VERSION 5.8 ;
BUSBITCHARS "[]" ;
DIVIDERCHAR "/" ;
UNITS
    DATABASE MICRONS 1000 ;
END UNITS

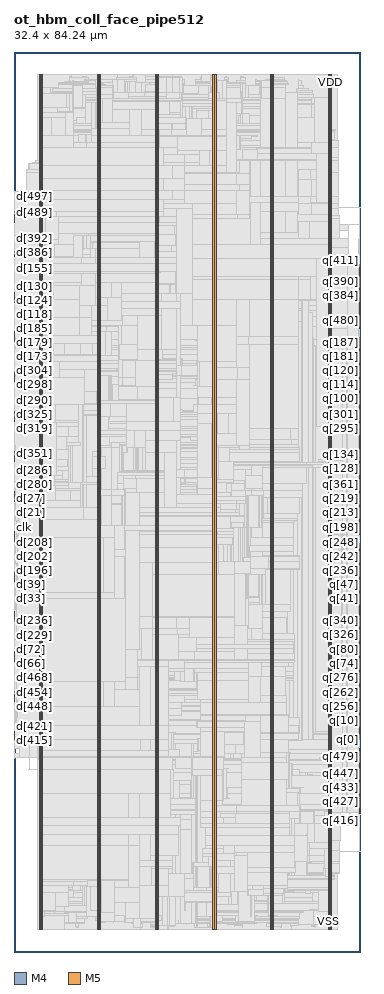
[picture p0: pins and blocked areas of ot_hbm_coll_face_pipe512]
MACRO ot_hbm_coll_face_pipe512
  FOREIGN ot_hbm_coll_face_pipe512 0 0 ;
  CLASS BLOCK ;
  SIZE 32.4 BY 84.24 ;
  PIN clk
    DIRECTION INPUT ;
    USE SIGNAL ;
    PORT
      LAYER M4 ;
        RECT  0 39.024 0.084 39.048 ;
    END
  END clk
  PIN d[0]
    DIRECTION INPUT ;
    USE SIGNAL ;
    PORT
      LAYER M4 ;
        RECT  0 39.12 0.084 39.144 ;
    END
  END d[0]
  PIN d[100]
    DIRECTION INPUT ;
    USE SIGNAL ;
    PORT
      LAYER M4 ;
        RECT  0 58.704 0.084 58.728 ;
    END
  END d[100]
  PIN d[101]
    DIRECTION INPUT ;
    USE SIGNAL ;
    PORT
      LAYER M4 ;
        RECT  0 58.8 0.084 58.824 ;
    END
  END d[101]
  PIN d[102]
    DIRECTION INPUT ;
    USE SIGNAL ;
    PORT
      LAYER M4 ;
        RECT  0 58.896 0.084 58.92 ;
    END
  END d[102]
  PIN d[103]
    DIRECTION INPUT ;
    USE SIGNAL ;
    PORT
      LAYER M4 ;
        RECT  0 58.992 0.084 59.016 ;
    END
  END d[103]
  PIN d[104]
    DIRECTION INPUT ;
    USE SIGNAL ;
    PORT
      LAYER M4 ;
        RECT  0 59.088 0.084 59.112 ;
    END
  END d[104]
  PIN d[105]
    DIRECTION INPUT ;
    USE SIGNAL ;
    PORT
      LAYER M4 ;
        RECT  0 59.184 0.084 59.208 ;
    END
  END d[105]
  PIN d[106]
    DIRECTION INPUT ;
    USE SIGNAL ;
    PORT
      LAYER M4 ;
        RECT  0 59.28 0.084 59.304 ;
    END
  END d[106]
  PIN d[107]
    DIRECTION INPUT ;
    USE SIGNAL ;
    PORT
      LAYER M4 ;
        RECT  0 59.376 0.084 59.4 ;
    END
  END d[107]
  PIN d[108]
    DIRECTION INPUT ;
    USE SIGNAL ;
    PORT
      LAYER M4 ;
        RECT  0 59.472 0.084 59.496 ;
    END
  END d[108]
  PIN d[109]
    DIRECTION INPUT ;
    USE SIGNAL ;
    PORT
      LAYER M4 ;
        RECT  0 59.568 0.084 59.592 ;
    END
  END d[109]
  PIN d[10]
    DIRECTION INPUT ;
    USE SIGNAL ;
    PORT
      LAYER M4 ;
        RECT  0 40.08 0.084 40.104 ;
    END
  END d[10]
  PIN d[110]
    DIRECTION INPUT ;
    USE SIGNAL ;
    PORT
      LAYER M4 ;
        RECT  0 59.664 0.084 59.688 ;
    END
  END d[110]
  PIN d[111]
    DIRECTION INPUT ;
    USE SIGNAL ;
    PORT
      LAYER M4 ;
        RECT  0 59.76 0.084 59.784 ;
    END
  END d[111]
  PIN d[112]
    DIRECTION INPUT ;
    USE SIGNAL ;
    PORT
      LAYER M4 ;
        RECT  0 59.856 0.084 59.88 ;
    END
  END d[112]
  PIN d[113]
    DIRECTION INPUT ;
    USE SIGNAL ;
    PORT
      LAYER M4 ;
        RECT  0 59.952 0.084 59.976 ;
    END
  END d[113]
  PIN d[114]
    DIRECTION INPUT ;
    USE SIGNAL ;
    PORT
      LAYER M4 ;
        RECT  0 60.048 0.084 60.072 ;
    END
  END d[114]
  PIN d[115]
    DIRECTION INPUT ;
    USE SIGNAL ;
    PORT
      LAYER M4 ;
        RECT  0 60.144 0.084 60.168 ;
    END
  END d[115]
  PIN d[116]
    DIRECTION INPUT ;
    USE SIGNAL ;
    PORT
      LAYER M4 ;
        RECT  0 60.24 0.084 60.264 ;
    END
  END d[116]
  PIN d[117]
    DIRECTION INPUT ;
    USE SIGNAL ;
    PORT
      LAYER M4 ;
        RECT  0 60.336 0.084 60.36 ;
    END
  END d[117]
  PIN d[118]
    DIRECTION INPUT ;
    USE SIGNAL ;
    PORT
      LAYER M4 ;
        RECT  0 60.432 0.084 60.456 ;
    END
  END d[118]
  PIN d[119]
    DIRECTION INPUT ;
    USE SIGNAL ;
    PORT
      LAYER M4 ;
        RECT  0 60.528 0.084 60.552 ;
    END
  END d[119]
  PIN d[11]
    DIRECTION INPUT ;
    USE SIGNAL ;
    PORT
      LAYER M4 ;
        RECT  0 40.176 0.084 40.2 ;
    END
  END d[11]
  PIN d[120]
    DIRECTION INPUT ;
    USE SIGNAL ;
    PORT
      LAYER M4 ;
        RECT  0 60.624 0.084 60.648 ;
    END
  END d[120]
  PIN d[121]
    DIRECTION INPUT ;
    USE SIGNAL ;
    PORT
      LAYER M4 ;
        RECT  0 60.72 0.084 60.744 ;
    END
  END d[121]
  PIN d[122]
    DIRECTION INPUT ;
    USE SIGNAL ;
    PORT
      LAYER M4 ;
        RECT  0 60.816 0.084 60.84 ;
    END
  END d[122]
  PIN d[123]
    DIRECTION INPUT ;
    USE SIGNAL ;
    PORT
      LAYER M4 ;
        RECT  0 60.912 0.084 60.936 ;
    END
  END d[123]
  PIN d[124]
    DIRECTION INPUT ;
    USE SIGNAL ;
    PORT
      LAYER M4 ;
        RECT  0 61.008 0.084 61.032 ;
    END
  END d[124]
  PIN d[125]
    DIRECTION INPUT ;
    USE SIGNAL ;
    PORT
      LAYER M4 ;
        RECT  0 61.104 0.084 61.128 ;
    END
  END d[125]
  PIN d[126]
    DIRECTION INPUT ;
    USE SIGNAL ;
    PORT
      LAYER M4 ;
        RECT  0 61.2 0.084 61.224 ;
    END
  END d[126]
  PIN d[127]
    DIRECTION INPUT ;
    USE SIGNAL ;
    PORT
      LAYER M4 ;
        RECT  0 61.296 0.084 61.32 ;
    END
  END d[127]
  PIN d[128]
    DIRECTION INPUT ;
    USE SIGNAL ;
    PORT
      LAYER M4 ;
        RECT  0 61.392 0.084 61.416 ;
    END
  END d[128]
  PIN d[129]
    DIRECTION INPUT ;
    USE SIGNAL ;
    PORT
      LAYER M4 ;
        RECT  0 61.488 0.084 61.512 ;
    END
  END d[129]
  PIN d[12]
    DIRECTION INPUT ;
    USE SIGNAL ;
    PORT
      LAYER M4 ;
        RECT  0 40.272 0.084 40.296 ;
    END
  END d[12]
  PIN d[130]
    DIRECTION INPUT ;
    USE SIGNAL ;
    PORT
      LAYER M4 ;
        RECT  0 61.584 0.084 61.608 ;
    END
  END d[130]
  PIN d[131]
    DIRECTION INPUT ;
    USE SIGNAL ;
    PORT
      LAYER M4 ;
        RECT  0 61.68 0.084 61.704 ;
    END
  END d[131]
  PIN d[132]
    DIRECTION INPUT ;
    USE SIGNAL ;
    PORT
      LAYER M4 ;
        RECT  0 61.776 0.084 61.8 ;
    END
  END d[132]
  PIN d[133]
    DIRECTION INPUT ;
    USE SIGNAL ;
    PORT
      LAYER M4 ;
        RECT  0 61.872 0.084 61.896 ;
    END
  END d[133]
  PIN d[134]
    DIRECTION INPUT ;
    USE SIGNAL ;
    PORT
      LAYER M4 ;
        RECT  0 61.968 0.084 61.992 ;
    END
  END d[134]
  PIN d[135]
    DIRECTION INPUT ;
    USE SIGNAL ;
    PORT
      LAYER M4 ;
        RECT  0 62.064 0.084 62.088 ;
    END
  END d[135]
  PIN d[136]
    DIRECTION INPUT ;
    USE SIGNAL ;
    PORT
      LAYER M4 ;
        RECT  0 62.16 0.084 62.184 ;
    END
  END d[136]
  PIN d[137]
    DIRECTION INPUT ;
    USE SIGNAL ;
    PORT
      LAYER M4 ;
        RECT  0 62.256 0.084 62.28 ;
    END
  END d[137]
  PIN d[138]
    DIRECTION INPUT ;
    USE SIGNAL ;
    PORT
      LAYER M4 ;
        RECT  0 62.352 0.084 62.376 ;
    END
  END d[138]
  PIN d[139]
    DIRECTION INPUT ;
    USE SIGNAL ;
    PORT
      LAYER M4 ;
        RECT  0 62.448 0.084 62.472 ;
    END
  END d[139]
  PIN d[13]
    DIRECTION INPUT ;
    USE SIGNAL ;
    PORT
      LAYER M4 ;
        RECT  0 40.368 0.084 40.392 ;
    END
  END d[13]
  PIN d[140]
    DIRECTION INPUT ;
    USE SIGNAL ;
    PORT
      LAYER M4 ;
        RECT  0 62.544 0.084 62.568 ;
    END
  END d[140]
  PIN d[141]
    DIRECTION INPUT ;
    USE SIGNAL ;
    PORT
      LAYER M4 ;
        RECT  0 62.64 0.084 62.664 ;
    END
  END d[141]
  PIN d[142]
    DIRECTION INPUT ;
    USE SIGNAL ;
    PORT
      LAYER M4 ;
        RECT  0 62.736 0.084 62.76 ;
    END
  END d[142]
  PIN d[143]
    DIRECTION INPUT ;
    USE SIGNAL ;
    PORT
      LAYER M4 ;
        RECT  0 62.832 0.084 62.856 ;
    END
  END d[143]
  PIN d[144]
    DIRECTION INPUT ;
    USE SIGNAL ;
    PORT
      LAYER M4 ;
        RECT  0 62.928 0.084 62.952 ;
    END
  END d[144]
  PIN d[145]
    DIRECTION INPUT ;
    USE SIGNAL ;
    PORT
      LAYER M4 ;
        RECT  0 63.024 0.084 63.048 ;
    END
  END d[145]
  PIN d[146]
    DIRECTION INPUT ;
    USE SIGNAL ;
    PORT
      LAYER M4 ;
        RECT  0 63.12 0.084 63.144 ;
    END
  END d[146]
  PIN d[147]
    DIRECTION INPUT ;
    USE SIGNAL ;
    PORT
      LAYER M4 ;
        RECT  0 63.216 0.084 63.24 ;
    END
  END d[147]
  PIN d[148]
    DIRECTION INPUT ;
    USE SIGNAL ;
    PORT
      LAYER M4 ;
        RECT  0 63.312 0.084 63.336 ;
    END
  END d[148]
  PIN d[149]
    DIRECTION INPUT ;
    USE SIGNAL ;
    PORT
      LAYER M4 ;
        RECT  0 63.408 0.084 63.432 ;
    END
  END d[149]
  PIN d[14]
    DIRECTION INPUT ;
    USE SIGNAL ;
    PORT
      LAYER M4 ;
        RECT  0 40.464 0.084 40.488 ;
    END
  END d[14]
  PIN d[150]
    DIRECTION INPUT ;
    USE SIGNAL ;
    PORT
      LAYER M4 ;
        RECT  0 63.504 0.084 63.528 ;
    END
  END d[150]
  PIN d[151]
    DIRECTION INPUT ;
    USE SIGNAL ;
    PORT
      LAYER M4 ;
        RECT  0 63.6 0.084 63.624 ;
    END
  END d[151]
  PIN d[152]
    DIRECTION INPUT ;
    USE SIGNAL ;
    PORT
      LAYER M4 ;
        RECT  0 63.696 0.084 63.72 ;
    END
  END d[152]
  PIN d[153]
    DIRECTION INPUT ;
    USE SIGNAL ;
    PORT
      LAYER M4 ;
        RECT  0 63.792 0.084 63.816 ;
    END
  END d[153]
  PIN d[154]
    DIRECTION INPUT ;
    USE SIGNAL ;
    PORT
      LAYER M4 ;
        RECT  0 63.888 0.084 63.912 ;
    END
  END d[154]
  PIN d[155]
    DIRECTION INPUT ;
    USE SIGNAL ;
    PORT
      LAYER M4 ;
        RECT  0 63.984 0.084 64.008 ;
    END
  END d[155]
  PIN d[156]
    DIRECTION INPUT ;
    USE SIGNAL ;
    PORT
      LAYER M4 ;
        RECT  0 64.08 0.084 64.104 ;
    END
  END d[156]
  PIN d[157]
    DIRECTION INPUT ;
    USE SIGNAL ;
    PORT
      LAYER M4 ;
        RECT  0 64.176 0.084 64.2 ;
    END
  END d[157]
  PIN d[158]
    DIRECTION INPUT ;
    USE SIGNAL ;
    PORT
      LAYER M4 ;
        RECT  0 64.272 0.084 64.296 ;
    END
  END d[158]
  PIN d[159]
    DIRECTION INPUT ;
    USE SIGNAL ;
    PORT
      LAYER M4 ;
        RECT  0 55.152 0.084 55.176 ;
    END
  END d[159]
  PIN d[15]
    DIRECTION INPUT ;
    USE SIGNAL ;
    PORT
      LAYER M4 ;
        RECT  0 40.56 0.084 40.584 ;
    END
  END d[15]
  PIN d[160]
    DIRECTION INPUT ;
    USE SIGNAL ;
    PORT
      LAYER M4 ;
        RECT  0 55.248 0.084 55.272 ;
    END
  END d[160]
  PIN d[161]
    DIRECTION INPUT ;
    USE SIGNAL ;
    PORT
      LAYER M4 ;
        RECT  0 55.344 0.084 55.368 ;
    END
  END d[161]
  PIN d[162]
    DIRECTION INPUT ;
    USE SIGNAL ;
    PORT
      LAYER M4 ;
        RECT  0 55.44 0.084 55.464 ;
    END
  END d[162]
  PIN d[163]
    DIRECTION INPUT ;
    USE SIGNAL ;
    PORT
      LAYER M4 ;
        RECT  0 55.536 0.084 55.56 ;
    END
  END d[163]
  PIN d[164]
    DIRECTION INPUT ;
    USE SIGNAL ;
    PORT
      LAYER M4 ;
        RECT  0 55.632 0.084 55.656 ;
    END
  END d[164]
  PIN d[165]
    DIRECTION INPUT ;
    USE SIGNAL ;
    PORT
      LAYER M4 ;
        RECT  0 55.728 0.084 55.752 ;
    END
  END d[165]
  PIN d[166]
    DIRECTION INPUT ;
    USE SIGNAL ;
    PORT
      LAYER M4 ;
        RECT  0 55.824 0.084 55.848 ;
    END
  END d[166]
  PIN d[167]
    DIRECTION INPUT ;
    USE SIGNAL ;
    PORT
      LAYER M4 ;
        RECT  0 55.92 0.084 55.944 ;
    END
  END d[167]
  PIN d[168]
    DIRECTION INPUT ;
    USE SIGNAL ;
    PORT
      LAYER M4 ;
        RECT  0 56.016 0.084 56.04 ;
    END
  END d[168]
  PIN d[169]
    DIRECTION INPUT ;
    USE SIGNAL ;
    PORT
      LAYER M4 ;
        RECT  0 56.112 0.084 56.136 ;
    END
  END d[169]
  PIN d[16]
    DIRECTION INPUT ;
    USE SIGNAL ;
    PORT
      LAYER M4 ;
        RECT  0 40.656 0.084 40.68 ;
    END
  END d[16]
  PIN d[170]
    DIRECTION INPUT ;
    USE SIGNAL ;
    PORT
      LAYER M4 ;
        RECT  0 56.208 0.084 56.232 ;
    END
  END d[170]
  PIN d[171]
    DIRECTION INPUT ;
    USE SIGNAL ;
    PORT
      LAYER M4 ;
        RECT  0 56.304 0.084 56.328 ;
    END
  END d[171]
  PIN d[172]
    DIRECTION INPUT ;
    USE SIGNAL ;
    PORT
      LAYER M4 ;
        RECT  0 56.4 0.084 56.424 ;
    END
  END d[172]
  PIN d[173]
    DIRECTION INPUT ;
    USE SIGNAL ;
    PORT
      LAYER M4 ;
        RECT  0 56.496 0.084 56.52 ;
    END
  END d[173]
  PIN d[174]
    DIRECTION INPUT ;
    USE SIGNAL ;
    PORT
      LAYER M4 ;
        RECT  0 56.592 0.084 56.616 ;
    END
  END d[174]
  PIN d[175]
    DIRECTION INPUT ;
    USE SIGNAL ;
    PORT
      LAYER M4 ;
        RECT  0 56.688 0.084 56.712 ;
    END
  END d[175]
  PIN d[176]
    DIRECTION INPUT ;
    USE SIGNAL ;
    PORT
      LAYER M4 ;
        RECT  0 56.784 0.084 56.808 ;
    END
  END d[176]
  PIN d[177]
    DIRECTION INPUT ;
    USE SIGNAL ;
    PORT
      LAYER M4 ;
        RECT  0 56.88 0.084 56.904 ;
    END
  END d[177]
  PIN d[178]
    DIRECTION INPUT ;
    USE SIGNAL ;
    PORT
      LAYER M4 ;
        RECT  0 56.976 0.084 57 ;
    END
  END d[178]
  PIN d[179]
    DIRECTION INPUT ;
    USE SIGNAL ;
    PORT
      LAYER M4 ;
        RECT  0 57.072 0.084 57.096 ;
    END
  END d[179]
  PIN d[17]
    DIRECTION INPUT ;
    USE SIGNAL ;
    PORT
      LAYER M4 ;
        RECT  0 40.752 0.084 40.776 ;
    END
  END d[17]
  PIN d[180]
    DIRECTION INPUT ;
    USE SIGNAL ;
    PORT
      LAYER M4 ;
        RECT  0 57.168 0.084 57.192 ;
    END
  END d[180]
  PIN d[181]
    DIRECTION INPUT ;
    USE SIGNAL ;
    PORT
      LAYER M4 ;
        RECT  0 57.264 0.084 57.288 ;
    END
  END d[181]
  PIN d[182]
    DIRECTION INPUT ;
    USE SIGNAL ;
    PORT
      LAYER M4 ;
        RECT  0 57.36 0.084 57.384 ;
    END
  END d[182]
  PIN d[183]
    DIRECTION INPUT ;
    USE SIGNAL ;
    PORT
      LAYER M4 ;
        RECT  0 57.456 0.084 57.48 ;
    END
  END d[183]
  PIN d[184]
    DIRECTION INPUT ;
    USE SIGNAL ;
    PORT
      LAYER M4 ;
        RECT  0 57.552 0.084 57.576 ;
    END
  END d[184]
  PIN d[185]
    DIRECTION INPUT ;
    USE SIGNAL ;
    PORT
      LAYER M4 ;
        RECT  0 57.648 0.084 57.672 ;
    END
  END d[185]
  PIN d[186]
    DIRECTION INPUT ;
    USE SIGNAL ;
    PORT
      LAYER M4 ;
        RECT  0 57.744 0.084 57.768 ;
    END
  END d[186]
  PIN d[187]
    DIRECTION INPUT ;
    USE SIGNAL ;
    PORT
      LAYER M4 ;
        RECT  0 57.84 0.084 57.864 ;
    END
  END d[187]
  PIN d[188]
    DIRECTION INPUT ;
    USE SIGNAL ;
    PORT
      LAYER M4 ;
        RECT  0 57.936 0.084 57.96 ;
    END
  END d[188]
  PIN d[189]
    DIRECTION INPUT ;
    USE SIGNAL ;
    PORT
      LAYER M4 ;
        RECT  0 58.032 0.084 58.056 ;
    END
  END d[189]
  PIN d[18]
    DIRECTION INPUT ;
    USE SIGNAL ;
    PORT
      LAYER M4 ;
        RECT  0 40.848 0.084 40.872 ;
    END
  END d[18]
  PIN d[190]
    DIRECTION INPUT ;
    USE SIGNAL ;
    PORT
      LAYER M4 ;
        RECT  0 58.128 0.084 58.152 ;
    END
  END d[190]
  PIN d[191]
    DIRECTION INPUT ;
    USE SIGNAL ;
    PORT
      LAYER M4 ;
        RECT  0 35.952 0.084 35.976 ;
    END
  END d[191]
  PIN d[192]
    DIRECTION INPUT ;
    USE SIGNAL ;
    PORT
      LAYER M4 ;
        RECT  0 36.048 0.084 36.072 ;
    END
  END d[192]
  PIN d[193]
    DIRECTION INPUT ;
    USE SIGNAL ;
    PORT
      LAYER M4 ;
        RECT  0 36.144 0.084 36.168 ;
    END
  END d[193]
  PIN d[194]
    DIRECTION INPUT ;
    USE SIGNAL ;
    PORT
      LAYER M4 ;
        RECT  0 36.24 0.084 36.264 ;
    END
  END d[194]
  PIN d[195]
    DIRECTION INPUT ;
    USE SIGNAL ;
    PORT
      LAYER M4 ;
        RECT  0 36.336 0.084 36.36 ;
    END
  END d[195]
  PIN d[196]
    DIRECTION INPUT ;
    USE SIGNAL ;
    PORT
      LAYER M4 ;
        RECT  0 36.432 0.084 36.456 ;
    END
  END d[196]
  PIN d[197]
    DIRECTION INPUT ;
    USE SIGNAL ;
    PORT
      LAYER M4 ;
        RECT  0 36.528 0.084 36.552 ;
    END
  END d[197]
  PIN d[198]
    DIRECTION INPUT ;
    USE SIGNAL ;
    PORT
      LAYER M4 ;
        RECT  0 36.624 0.084 36.648 ;
    END
  END d[198]
  PIN d[199]
    DIRECTION INPUT ;
    USE SIGNAL ;
    PORT
      LAYER M4 ;
        RECT  0 36.72 0.084 36.744 ;
    END
  END d[199]
  PIN d[19]
    DIRECTION INPUT ;
    USE SIGNAL ;
    PORT
      LAYER M4 ;
        RECT  0 40.944 0.084 40.968 ;
    END
  END d[19]
  PIN d[1]
    DIRECTION INPUT ;
    USE SIGNAL ;
    PORT
      LAYER M4 ;
        RECT  0 39.216 0.084 39.24 ;
    END
  END d[1]
  PIN d[200]
    DIRECTION INPUT ;
    USE SIGNAL ;
    PORT
      LAYER M4 ;
        RECT  0 36.816 0.084 36.84 ;
    END
  END d[200]
  PIN d[201]
    DIRECTION INPUT ;
    USE SIGNAL ;
    PORT
      LAYER M4 ;
        RECT  0 36.912 0.084 36.936 ;
    END
  END d[201]
  PIN d[202]
    DIRECTION INPUT ;
    USE SIGNAL ;
    PORT
      LAYER M4 ;
        RECT  0 37.008 0.084 37.032 ;
    END
  END d[202]
  PIN d[203]
    DIRECTION INPUT ;
    USE SIGNAL ;
    PORT
      LAYER M4 ;
        RECT  0 37.104 0.084 37.128 ;
    END
  END d[203]
  PIN d[204]
    DIRECTION INPUT ;
    USE SIGNAL ;
    PORT
      LAYER M4 ;
        RECT  0 37.2 0.084 37.224 ;
    END
  END d[204]
  PIN d[205]
    DIRECTION INPUT ;
    USE SIGNAL ;
    PORT
      LAYER M4 ;
        RECT  0 37.296 0.084 37.32 ;
    END
  END d[205]
  PIN d[206]
    DIRECTION INPUT ;
    USE SIGNAL ;
    PORT
      LAYER M4 ;
        RECT  0 37.392 0.084 37.416 ;
    END
  END d[206]
  PIN d[207]
    DIRECTION INPUT ;
    USE SIGNAL ;
    PORT
      LAYER M4 ;
        RECT  0 37.488 0.084 37.512 ;
    END
  END d[207]
  PIN d[208]
    DIRECTION INPUT ;
    USE SIGNAL ;
    PORT
      LAYER M4 ;
        RECT  0 37.584 0.084 37.608 ;
    END
  END d[208]
  PIN d[209]
    DIRECTION INPUT ;
    USE SIGNAL ;
    PORT
      LAYER M4 ;
        RECT  0 37.68 0.084 37.704 ;
    END
  END d[209]
  PIN d[20]
    DIRECTION INPUT ;
    USE SIGNAL ;
    PORT
      LAYER M4 ;
        RECT  0 41.04 0.084 41.064 ;
    END
  END d[20]
  PIN d[210]
    DIRECTION INPUT ;
    USE SIGNAL ;
    PORT
      LAYER M4 ;
        RECT  0 37.776 0.084 37.8 ;
    END
  END d[210]
  PIN d[211]
    DIRECTION INPUT ;
    USE SIGNAL ;
    PORT
      LAYER M4 ;
        RECT  0 37.872 0.084 37.896 ;
    END
  END d[211]
  PIN d[212]
    DIRECTION INPUT ;
    USE SIGNAL ;
    PORT
      LAYER M4 ;
        RECT  0 37.968 0.084 37.992 ;
    END
  END d[212]
  PIN d[213]
    DIRECTION INPUT ;
    USE SIGNAL ;
    PORT
      LAYER M4 ;
        RECT  0 38.064 0.084 38.088 ;
    END
  END d[213]
  PIN d[214]
    DIRECTION INPUT ;
    USE SIGNAL ;
    PORT
      LAYER M4 ;
        RECT  0 38.16 0.084 38.184 ;
    END
  END d[214]
  PIN d[215]
    DIRECTION INPUT ;
    USE SIGNAL ;
    PORT
      LAYER M4 ;
        RECT  0 38.256 0.084 38.28 ;
    END
  END d[215]
  PIN d[216]
    DIRECTION INPUT ;
    USE SIGNAL ;
    PORT
      LAYER M4 ;
        RECT  0 38.352 0.084 38.376 ;
    END
  END d[216]
  PIN d[217]
    DIRECTION INPUT ;
    USE SIGNAL ;
    PORT
      LAYER M4 ;
        RECT  0 38.448 0.084 38.472 ;
    END
  END d[217]
  PIN d[218]
    DIRECTION INPUT ;
    USE SIGNAL ;
    PORT
      LAYER M4 ;
        RECT  0 38.544 0.084 38.568 ;
    END
  END d[218]
  PIN d[219]
    DIRECTION INPUT ;
    USE SIGNAL ;
    PORT
      LAYER M4 ;
        RECT  0 38.64 0.084 38.664 ;
    END
  END d[219]
  PIN d[21]
    DIRECTION INPUT ;
    USE SIGNAL ;
    PORT
      LAYER M4 ;
        RECT  0 41.136 0.084 41.16 ;
    END
  END d[21]
  PIN d[220]
    DIRECTION INPUT ;
    USE SIGNAL ;
    PORT
      LAYER M4 ;
        RECT  0 38.736 0.084 38.76 ;
    END
  END d[220]
  PIN d[221]
    DIRECTION INPUT ;
    USE SIGNAL ;
    PORT
      LAYER M4 ;
        RECT  0 38.832 0.084 38.856 ;
    END
  END d[221]
  PIN d[222]
    DIRECTION INPUT ;
    USE SIGNAL ;
    PORT
      LAYER M4 ;
        RECT  0 38.928 0.084 38.952 ;
    END
  END d[222]
  PIN d[223]
    DIRECTION INPUT ;
    USE SIGNAL ;
    PORT
      LAYER M4 ;
        RECT  0 29.808 0.084 29.832 ;
    END
  END d[223]
  PIN d[224]
    DIRECTION INPUT ;
    USE SIGNAL ;
    PORT
      LAYER M4 ;
        RECT  0 29.904 0.084 29.928 ;
    END
  END d[224]
  PIN d[225]
    DIRECTION INPUT ;
    USE SIGNAL ;
    PORT
      LAYER M4 ;
        RECT  0 30 0.084 30.024 ;
    END
  END d[225]
  PIN d[226]
    DIRECTION INPUT ;
    USE SIGNAL ;
    PORT
      LAYER M4 ;
        RECT  0 30.096 0.084 30.12 ;
    END
  END d[226]
  PIN d[227]
    DIRECTION INPUT ;
    USE SIGNAL ;
    PORT
      LAYER M4 ;
        RECT  0 30.192 0.084 30.216 ;
    END
  END d[227]
  PIN d[228]
    DIRECTION INPUT ;
    USE SIGNAL ;
    PORT
      LAYER M4 ;
        RECT  0 30.288 0.084 30.312 ;
    END
  END d[228]
  PIN d[229]
    DIRECTION INPUT ;
    USE SIGNAL ;
    PORT
      LAYER M4 ;
        RECT  0 30.384 0.084 30.408 ;
    END
  END d[229]
  PIN d[22]
    DIRECTION INPUT ;
    USE SIGNAL ;
    PORT
      LAYER M4 ;
        RECT  0 41.232 0.084 41.256 ;
    END
  END d[22]
  PIN d[230]
    DIRECTION INPUT ;
    USE SIGNAL ;
    PORT
      LAYER M4 ;
        RECT  0 30.48 0.084 30.504 ;
    END
  END d[230]
  PIN d[231]
    DIRECTION INPUT ;
    USE SIGNAL ;
    PORT
      LAYER M4 ;
        RECT  0 30.576 0.084 30.6 ;
    END
  END d[231]
  PIN d[232]
    DIRECTION INPUT ;
    USE SIGNAL ;
    PORT
      LAYER M4 ;
        RECT  0 30.672 0.084 30.696 ;
    END
  END d[232]
  PIN d[233]
    DIRECTION INPUT ;
    USE SIGNAL ;
    PORT
      LAYER M4 ;
        RECT  0 30.768 0.084 30.792 ;
    END
  END d[233]
  PIN d[234]
    DIRECTION INPUT ;
    USE SIGNAL ;
    PORT
      LAYER M4 ;
        RECT  0 30.864 0.084 30.888 ;
    END
  END d[234]
  PIN d[235]
    DIRECTION INPUT ;
    USE SIGNAL ;
    PORT
      LAYER M4 ;
        RECT  0 30.96 0.084 30.984 ;
    END
  END d[235]
  PIN d[236]
    DIRECTION INPUT ;
    USE SIGNAL ;
    PORT
      LAYER M4 ;
        RECT  0 31.056 0.084 31.08 ;
    END
  END d[236]
  PIN d[237]
    DIRECTION INPUT ;
    USE SIGNAL ;
    PORT
      LAYER M4 ;
        RECT  0 31.152 0.084 31.176 ;
    END
  END d[237]
  PIN d[238]
    DIRECTION INPUT ;
    USE SIGNAL ;
    PORT
      LAYER M4 ;
        RECT  0 31.248 0.084 31.272 ;
    END
  END d[238]
  PIN d[239]
    DIRECTION INPUT ;
    USE SIGNAL ;
    PORT
      LAYER M4 ;
        RECT  0 31.344 0.084 31.368 ;
    END
  END d[239]
  PIN d[23]
    DIRECTION INPUT ;
    USE SIGNAL ;
    PORT
      LAYER M4 ;
        RECT  0 41.328 0.084 41.352 ;
    END
  END d[23]
  PIN d[240]
    DIRECTION INPUT ;
    USE SIGNAL ;
    PORT
      LAYER M4 ;
        RECT  0 31.44 0.084 31.464 ;
    END
  END d[240]
  PIN d[241]
    DIRECTION INPUT ;
    USE SIGNAL ;
    PORT
      LAYER M4 ;
        RECT  0 31.536 0.084 31.56 ;
    END
  END d[241]
  PIN d[242]
    DIRECTION INPUT ;
    USE SIGNAL ;
    PORT
      LAYER M4 ;
        RECT  0 31.632 0.084 31.656 ;
    END
  END d[242]
  PIN d[243]
    DIRECTION INPUT ;
    USE SIGNAL ;
    PORT
      LAYER M4 ;
        RECT  0 31.728 0.084 31.752 ;
    END
  END d[243]
  PIN d[244]
    DIRECTION INPUT ;
    USE SIGNAL ;
    PORT
      LAYER M4 ;
        RECT  0 31.824 0.084 31.848 ;
    END
  END d[244]
  PIN d[245]
    DIRECTION INPUT ;
    USE SIGNAL ;
    PORT
      LAYER M4 ;
        RECT  0 31.92 0.084 31.944 ;
    END
  END d[245]
  PIN d[246]
    DIRECTION INPUT ;
    USE SIGNAL ;
    PORT
      LAYER M4 ;
        RECT  0 32.016 0.084 32.04 ;
    END
  END d[246]
  PIN d[247]
    DIRECTION INPUT ;
    USE SIGNAL ;
    PORT
      LAYER M4 ;
        RECT  0 32.112 0.084 32.136 ;
    END
  END d[247]
  PIN d[248]
    DIRECTION INPUT ;
    USE SIGNAL ;
    PORT
      LAYER M4 ;
        RECT  0 32.208 0.084 32.232 ;
    END
  END d[248]
  PIN d[249]
    DIRECTION INPUT ;
    USE SIGNAL ;
    PORT
      LAYER M4 ;
        RECT  0 32.304 0.084 32.328 ;
    END
  END d[249]
  PIN d[24]
    DIRECTION INPUT ;
    USE SIGNAL ;
    PORT
      LAYER M4 ;
        RECT  0 41.424 0.084 41.448 ;
    END
  END d[24]
  PIN d[250]
    DIRECTION INPUT ;
    USE SIGNAL ;
    PORT
      LAYER M4 ;
        RECT  0 32.4 0.084 32.424 ;
    END
  END d[250]
  PIN d[251]
    DIRECTION INPUT ;
    USE SIGNAL ;
    PORT
      LAYER M4 ;
        RECT  0 32.496 0.084 32.52 ;
    END
  END d[251]
  PIN d[252]
    DIRECTION INPUT ;
    USE SIGNAL ;
    PORT
      LAYER M4 ;
        RECT  0 32.592 0.084 32.616 ;
    END
  END d[252]
  PIN d[253]
    DIRECTION INPUT ;
    USE SIGNAL ;
    PORT
      LAYER M4 ;
        RECT  0 32.688 0.084 32.712 ;
    END
  END d[253]
  PIN d[254]
    DIRECTION INPUT ;
    USE SIGNAL ;
    PORT
      LAYER M4 ;
        RECT  0 32.784 0.084 32.808 ;
    END
  END d[254]
  PIN d[255]
    DIRECTION INPUT ;
    USE SIGNAL ;
    PORT
      LAYER M4 ;
        RECT  0 42.096 0.084 42.12 ;
    END
  END d[255]
  PIN d[256]
    DIRECTION INPUT ;
    USE SIGNAL ;
    PORT
      LAYER M4 ;
        RECT  0 42.192 0.084 42.216 ;
    END
  END d[256]
  PIN d[257]
    DIRECTION INPUT ;
    USE SIGNAL ;
    PORT
      LAYER M4 ;
        RECT  0 42.288 0.084 42.312 ;
    END
  END d[257]
  PIN d[258]
    DIRECTION INPUT ;
    USE SIGNAL ;
    PORT
      LAYER M4 ;
        RECT  0 42.384 0.084 42.408 ;
    END
  END d[258]
  PIN d[259]
    DIRECTION INPUT ;
    USE SIGNAL ;
    PORT
      LAYER M4 ;
        RECT  0 42.48 0.084 42.504 ;
    END
  END d[259]
  PIN d[25]
    DIRECTION INPUT ;
    USE SIGNAL ;
    PORT
      LAYER M4 ;
        RECT  0 41.52 0.084 41.544 ;
    END
  END d[25]
  PIN d[260]
    DIRECTION INPUT ;
    USE SIGNAL ;
    PORT
      LAYER M4 ;
        RECT  0 42.576 0.084 42.6 ;
    END
  END d[260]
  PIN d[261]
    DIRECTION INPUT ;
    USE SIGNAL ;
    PORT
      LAYER M4 ;
        RECT  0 42.672 0.084 42.696 ;
    END
  END d[261]
  PIN d[262]
    DIRECTION INPUT ;
    USE SIGNAL ;
    PORT
      LAYER M4 ;
        RECT  0 42.768 0.084 42.792 ;
    END
  END d[262]
  PIN d[263]
    DIRECTION INPUT ;
    USE SIGNAL ;
    PORT
      LAYER M4 ;
        RECT  0 42.864 0.084 42.888 ;
    END
  END d[263]
  PIN d[264]
    DIRECTION INPUT ;
    USE SIGNAL ;
    PORT
      LAYER M4 ;
        RECT  0 42.96 0.084 42.984 ;
    END
  END d[264]
  PIN d[265]
    DIRECTION INPUT ;
    USE SIGNAL ;
    PORT
      LAYER M4 ;
        RECT  0 43.056 0.084 43.08 ;
    END
  END d[265]
  PIN d[266]
    DIRECTION INPUT ;
    USE SIGNAL ;
    PORT
      LAYER M4 ;
        RECT  0 43.152 0.084 43.176 ;
    END
  END d[266]
  PIN d[267]
    DIRECTION INPUT ;
    USE SIGNAL ;
    PORT
      LAYER M4 ;
        RECT  0 43.248 0.084 43.272 ;
    END
  END d[267]
  PIN d[268]
    DIRECTION INPUT ;
    USE SIGNAL ;
    PORT
      LAYER M4 ;
        RECT  0 43.344 0.084 43.368 ;
    END
  END d[268]
  PIN d[269]
    DIRECTION INPUT ;
    USE SIGNAL ;
    PORT
      LAYER M4 ;
        RECT  0 43.44 0.084 43.464 ;
    END
  END d[269]
  PIN d[26]
    DIRECTION INPUT ;
    USE SIGNAL ;
    PORT
      LAYER M4 ;
        RECT  0 41.616 0.084 41.64 ;
    END
  END d[26]
  PIN d[270]
    DIRECTION INPUT ;
    USE SIGNAL ;
    PORT
      LAYER M4 ;
        RECT  0 43.536 0.084 43.56 ;
    END
  END d[270]
  PIN d[271]
    DIRECTION INPUT ;
    USE SIGNAL ;
    PORT
      LAYER M4 ;
        RECT  0 43.632 0.084 43.656 ;
    END
  END d[271]
  PIN d[272]
    DIRECTION INPUT ;
    USE SIGNAL ;
    PORT
      LAYER M4 ;
        RECT  0 43.728 0.084 43.752 ;
    END
  END d[272]
  PIN d[273]
    DIRECTION INPUT ;
    USE SIGNAL ;
    PORT
      LAYER M4 ;
        RECT  0 43.824 0.084 43.848 ;
    END
  END d[273]
  PIN d[274]
    DIRECTION INPUT ;
    USE SIGNAL ;
    PORT
      LAYER M4 ;
        RECT  0 43.92 0.084 43.944 ;
    END
  END d[274]
  PIN d[275]
    DIRECTION INPUT ;
    USE SIGNAL ;
    PORT
      LAYER M4 ;
        RECT  0 44.016 0.084 44.04 ;
    END
  END d[275]
  PIN d[276]
    DIRECTION INPUT ;
    USE SIGNAL ;
    PORT
      LAYER M4 ;
        RECT  0 44.112 0.084 44.136 ;
    END
  END d[276]
  PIN d[277]
    DIRECTION INPUT ;
    USE SIGNAL ;
    PORT
      LAYER M4 ;
        RECT  0 44.208 0.084 44.232 ;
    END
  END d[277]
  PIN d[278]
    DIRECTION INPUT ;
    USE SIGNAL ;
    PORT
      LAYER M4 ;
        RECT  0 44.304 0.084 44.328 ;
    END
  END d[278]
  PIN d[279]
    DIRECTION INPUT ;
    USE SIGNAL ;
    PORT
      LAYER M4 ;
        RECT  0 44.4 0.084 44.424 ;
    END
  END d[279]
  PIN d[27]
    DIRECTION INPUT ;
    USE SIGNAL ;
    PORT
      LAYER M4 ;
        RECT  0 41.712 0.084 41.736 ;
    END
  END d[27]
  PIN d[280]
    DIRECTION INPUT ;
    USE SIGNAL ;
    PORT
      LAYER M4 ;
        RECT  0 44.496 0.084 44.52 ;
    END
  END d[280]
  PIN d[281]
    DIRECTION INPUT ;
    USE SIGNAL ;
    PORT
      LAYER M4 ;
        RECT  0 44.592 0.084 44.616 ;
    END
  END d[281]
  PIN d[282]
    DIRECTION INPUT ;
    USE SIGNAL ;
    PORT
      LAYER M4 ;
        RECT  0 44.688 0.084 44.712 ;
    END
  END d[282]
  PIN d[283]
    DIRECTION INPUT ;
    USE SIGNAL ;
    PORT
      LAYER M4 ;
        RECT  0 44.784 0.084 44.808 ;
    END
  END d[283]
  PIN d[284]
    DIRECTION INPUT ;
    USE SIGNAL ;
    PORT
      LAYER M4 ;
        RECT  0 44.88 0.084 44.904 ;
    END
  END d[284]
  PIN d[285]
    DIRECTION INPUT ;
    USE SIGNAL ;
    PORT
      LAYER M4 ;
        RECT  0 44.976 0.084 45 ;
    END
  END d[285]
  PIN d[286]
    DIRECTION INPUT ;
    USE SIGNAL ;
    PORT
      LAYER M4 ;
        RECT  0 45.072 0.084 45.096 ;
    END
  END d[286]
  PIN d[287]
    DIRECTION INPUT ;
    USE SIGNAL ;
    PORT
      LAYER M4 ;
        RECT  0 52.08 0.084 52.104 ;
    END
  END d[287]
  PIN d[288]
    DIRECTION INPUT ;
    USE SIGNAL ;
    PORT
      LAYER M4 ;
        RECT  0 52.176 0.084 52.2 ;
    END
  END d[288]
  PIN d[289]
    DIRECTION INPUT ;
    USE SIGNAL ;
    PORT
      LAYER M4 ;
        RECT  0 52.272 0.084 52.296 ;
    END
  END d[289]
  PIN d[28]
    DIRECTION INPUT ;
    USE SIGNAL ;
    PORT
      LAYER M4 ;
        RECT  0 41.808 0.084 41.832 ;
    END
  END d[28]
  PIN d[290]
    DIRECTION INPUT ;
    USE SIGNAL ;
    PORT
      LAYER M4 ;
        RECT  0 52.368 0.084 52.392 ;
    END
  END d[290]
  PIN d[291]
    DIRECTION INPUT ;
    USE SIGNAL ;
    PORT
      LAYER M4 ;
        RECT  0 52.464 0.084 52.488 ;
    END
  END d[291]
  PIN d[292]
    DIRECTION INPUT ;
    USE SIGNAL ;
    PORT
      LAYER M4 ;
        RECT  0 52.56 0.084 52.584 ;
    END
  END d[292]
  PIN d[293]
    DIRECTION INPUT ;
    USE SIGNAL ;
    PORT
      LAYER M4 ;
        RECT  0 52.656 0.084 52.68 ;
    END
  END d[293]
  PIN d[294]
    DIRECTION INPUT ;
    USE SIGNAL ;
    PORT
      LAYER M4 ;
        RECT  0 52.752 0.084 52.776 ;
    END
  END d[294]
  PIN d[295]
    DIRECTION INPUT ;
    USE SIGNAL ;
    PORT
      LAYER M4 ;
        RECT  0 52.848 0.084 52.872 ;
    END
  END d[295]
  PIN d[296]
    DIRECTION INPUT ;
    USE SIGNAL ;
    PORT
      LAYER M4 ;
        RECT  0 52.944 0.084 52.968 ;
    END
  END d[296]
  PIN d[297]
    DIRECTION INPUT ;
    USE SIGNAL ;
    PORT
      LAYER M4 ;
        RECT  0 53.04 0.084 53.064 ;
    END
  END d[297]
  PIN d[298]
    DIRECTION INPUT ;
    USE SIGNAL ;
    PORT
      LAYER M4 ;
        RECT  0 53.136 0.084 53.16 ;
    END
  END d[298]
  PIN d[299]
    DIRECTION INPUT ;
    USE SIGNAL ;
    PORT
      LAYER M4 ;
        RECT  0 53.232 0.084 53.256 ;
    END
  END d[299]
  PIN d[29]
    DIRECTION INPUT ;
    USE SIGNAL ;
    PORT
      LAYER M4 ;
        RECT  0 41.904 0.084 41.928 ;
    END
  END d[29]
  PIN d[2]
    DIRECTION INPUT ;
    USE SIGNAL ;
    PORT
      LAYER M4 ;
        RECT  0 39.312 0.084 39.336 ;
    END
  END d[2]
  PIN d[300]
    DIRECTION INPUT ;
    USE SIGNAL ;
    PORT
      LAYER M4 ;
        RECT  0 53.328 0.084 53.352 ;
    END
  END d[300]
  PIN d[301]
    DIRECTION INPUT ;
    USE SIGNAL ;
    PORT
      LAYER M4 ;
        RECT  0 53.424 0.084 53.448 ;
    END
  END d[301]
  PIN d[302]
    DIRECTION INPUT ;
    USE SIGNAL ;
    PORT
      LAYER M4 ;
        RECT  0 53.52 0.084 53.544 ;
    END
  END d[302]
  PIN d[303]
    DIRECTION INPUT ;
    USE SIGNAL ;
    PORT
      LAYER M4 ;
        RECT  0 53.616 0.084 53.64 ;
    END
  END d[303]
  PIN d[304]
    DIRECTION INPUT ;
    USE SIGNAL ;
    PORT
      LAYER M4 ;
        RECT  0 53.712 0.084 53.736 ;
    END
  END d[304]
  PIN d[305]
    DIRECTION INPUT ;
    USE SIGNAL ;
    PORT
      LAYER M4 ;
        RECT  0 53.808 0.084 53.832 ;
    END
  END d[305]
  PIN d[306]
    DIRECTION INPUT ;
    USE SIGNAL ;
    PORT
      LAYER M4 ;
        RECT  0 53.904 0.084 53.928 ;
    END
  END d[306]
  PIN d[307]
    DIRECTION INPUT ;
    USE SIGNAL ;
    PORT
      LAYER M4 ;
        RECT  0 54 0.084 54.024 ;
    END
  END d[307]
  PIN d[308]
    DIRECTION INPUT ;
    USE SIGNAL ;
    PORT
      LAYER M4 ;
        RECT  0 54.096 0.084 54.12 ;
    END
  END d[308]
  PIN d[309]
    DIRECTION INPUT ;
    USE SIGNAL ;
    PORT
      LAYER M4 ;
        RECT  0 54.192 0.084 54.216 ;
    END
  END d[309]
  PIN d[30]
    DIRECTION INPUT ;
    USE SIGNAL ;
    PORT
      LAYER M4 ;
        RECT  0 42 0.084 42.024 ;
    END
  END d[30]
  PIN d[310]
    DIRECTION INPUT ;
    USE SIGNAL ;
    PORT
      LAYER M4 ;
        RECT  0 54.288 0.084 54.312 ;
    END
  END d[310]
  PIN d[311]
    DIRECTION INPUT ;
    USE SIGNAL ;
    PORT
      LAYER M4 ;
        RECT  0 54.384 0.084 54.408 ;
    END
  END d[311]
  PIN d[312]
    DIRECTION INPUT ;
    USE SIGNAL ;
    PORT
      LAYER M4 ;
        RECT  0 54.48 0.084 54.504 ;
    END
  END d[312]
  PIN d[313]
    DIRECTION INPUT ;
    USE SIGNAL ;
    PORT
      LAYER M4 ;
        RECT  0 54.576 0.084 54.6 ;
    END
  END d[313]
  PIN d[314]
    DIRECTION INPUT ;
    USE SIGNAL ;
    PORT
      LAYER M4 ;
        RECT  0 54.672 0.084 54.696 ;
    END
  END d[314]
  PIN d[315]
    DIRECTION INPUT ;
    USE SIGNAL ;
    PORT
      LAYER M4 ;
        RECT  0 54.768 0.084 54.792 ;
    END
  END d[315]
  PIN d[316]
    DIRECTION INPUT ;
    USE SIGNAL ;
    PORT
      LAYER M4 ;
        RECT  0 54.864 0.084 54.888 ;
    END
  END d[316]
  PIN d[317]
    DIRECTION INPUT ;
    USE SIGNAL ;
    PORT
      LAYER M4 ;
        RECT  0 54.96 0.084 54.984 ;
    END
  END d[317]
  PIN d[318]
    DIRECTION INPUT ;
    USE SIGNAL ;
    PORT
      LAYER M4 ;
        RECT  0 55.056 0.084 55.08 ;
    END
  END d[318]
  PIN d[319]
    DIRECTION INPUT ;
    USE SIGNAL ;
    PORT
      LAYER M4 ;
        RECT  0 49.008 0.084 49.032 ;
    END
  END d[319]
  PIN d[31]
    DIRECTION INPUT ;
    USE SIGNAL ;
    PORT
      LAYER M4 ;
        RECT  0 32.88 0.084 32.904 ;
    END
  END d[31]
  PIN d[320]
    DIRECTION INPUT ;
    USE SIGNAL ;
    PORT
      LAYER M4 ;
        RECT  0 49.104 0.084 49.128 ;
    END
  END d[320]
  PIN d[321]
    DIRECTION INPUT ;
    USE SIGNAL ;
    PORT
      LAYER M4 ;
        RECT  0 49.2 0.084 49.224 ;
    END
  END d[321]
  PIN d[322]
    DIRECTION INPUT ;
    USE SIGNAL ;
    PORT
      LAYER M4 ;
        RECT  0 49.296 0.084 49.32 ;
    END
  END d[322]
  PIN d[323]
    DIRECTION INPUT ;
    USE SIGNAL ;
    PORT
      LAYER M4 ;
        RECT  0 49.392 0.084 49.416 ;
    END
  END d[323]
  PIN d[324]
    DIRECTION INPUT ;
    USE SIGNAL ;
    PORT
      LAYER M4 ;
        RECT  0 49.488 0.084 49.512 ;
    END
  END d[324]
  PIN d[325]
    DIRECTION INPUT ;
    USE SIGNAL ;
    PORT
      LAYER M4 ;
        RECT  0 49.584 0.084 49.608 ;
    END
  END d[325]
  PIN d[326]
    DIRECTION INPUT ;
    USE SIGNAL ;
    PORT
      LAYER M4 ;
        RECT  0 49.68 0.084 49.704 ;
    END
  END d[326]
  PIN d[327]
    DIRECTION INPUT ;
    USE SIGNAL ;
    PORT
      LAYER M4 ;
        RECT  0 49.776 0.084 49.8 ;
    END
  END d[327]
  PIN d[328]
    DIRECTION INPUT ;
    USE SIGNAL ;
    PORT
      LAYER M4 ;
        RECT  0 49.872 0.084 49.896 ;
    END
  END d[328]
  PIN d[329]
    DIRECTION INPUT ;
    USE SIGNAL ;
    PORT
      LAYER M4 ;
        RECT  0 49.968 0.084 49.992 ;
    END
  END d[329]
  PIN d[32]
    DIRECTION INPUT ;
    USE SIGNAL ;
    PORT
      LAYER M4 ;
        RECT  0 32.976 0.084 33 ;
    END
  END d[32]
  PIN d[330]
    DIRECTION INPUT ;
    USE SIGNAL ;
    PORT
      LAYER M4 ;
        RECT  0 50.064 0.084 50.088 ;
    END
  END d[330]
  PIN d[331]
    DIRECTION INPUT ;
    USE SIGNAL ;
    PORT
      LAYER M4 ;
        RECT  0 50.16 0.084 50.184 ;
    END
  END d[331]
  PIN d[332]
    DIRECTION INPUT ;
    USE SIGNAL ;
    PORT
      LAYER M4 ;
        RECT  0 50.256 0.084 50.28 ;
    END
  END d[332]
  PIN d[333]
    DIRECTION INPUT ;
    USE SIGNAL ;
    PORT
      LAYER M4 ;
        RECT  0 50.352 0.084 50.376 ;
    END
  END d[333]
  PIN d[334]
    DIRECTION INPUT ;
    USE SIGNAL ;
    PORT
      LAYER M4 ;
        RECT  0 50.448 0.084 50.472 ;
    END
  END d[334]
  PIN d[335]
    DIRECTION INPUT ;
    USE SIGNAL ;
    PORT
      LAYER M4 ;
        RECT  0 50.544 0.084 50.568 ;
    END
  END d[335]
  PIN d[336]
    DIRECTION INPUT ;
    USE SIGNAL ;
    PORT
      LAYER M4 ;
        RECT  0 50.64 0.084 50.664 ;
    END
  END d[336]
  PIN d[337]
    DIRECTION INPUT ;
    USE SIGNAL ;
    PORT
      LAYER M4 ;
        RECT  0 50.736 0.084 50.76 ;
    END
  END d[337]
  PIN d[338]
    DIRECTION INPUT ;
    USE SIGNAL ;
    PORT
      LAYER M4 ;
        RECT  0 50.832 0.084 50.856 ;
    END
  END d[338]
  PIN d[339]
    DIRECTION INPUT ;
    USE SIGNAL ;
    PORT
      LAYER M4 ;
        RECT  0 50.928 0.084 50.952 ;
    END
  END d[339]
  PIN d[33]
    DIRECTION INPUT ;
    USE SIGNAL ;
    PORT
      LAYER M4 ;
        RECT  0 33.072 0.084 33.096 ;
    END
  END d[33]
  PIN d[340]
    DIRECTION INPUT ;
    USE SIGNAL ;
    PORT
      LAYER M4 ;
        RECT  0 51.024 0.084 51.048 ;
    END
  END d[340]
  PIN d[341]
    DIRECTION INPUT ;
    USE SIGNAL ;
    PORT
      LAYER M4 ;
        RECT  0 51.12 0.084 51.144 ;
    END
  END d[341]
  PIN d[342]
    DIRECTION INPUT ;
    USE SIGNAL ;
    PORT
      LAYER M4 ;
        RECT  0 51.216 0.084 51.24 ;
    END
  END d[342]
  PIN d[343]
    DIRECTION INPUT ;
    USE SIGNAL ;
    PORT
      LAYER M4 ;
        RECT  0 51.312 0.084 51.336 ;
    END
  END d[343]
  PIN d[344]
    DIRECTION INPUT ;
    USE SIGNAL ;
    PORT
      LAYER M4 ;
        RECT  0 51.408 0.084 51.432 ;
    END
  END d[344]
  PIN d[345]
    DIRECTION INPUT ;
    USE SIGNAL ;
    PORT
      LAYER M4 ;
        RECT  0 51.504 0.084 51.528 ;
    END
  END d[345]
  PIN d[346]
    DIRECTION INPUT ;
    USE SIGNAL ;
    PORT
      LAYER M4 ;
        RECT  0 51.6 0.084 51.624 ;
    END
  END d[346]
  PIN d[347]
    DIRECTION INPUT ;
    USE SIGNAL ;
    PORT
      LAYER M4 ;
        RECT  0 51.696 0.084 51.72 ;
    END
  END d[347]
  PIN d[348]
    DIRECTION INPUT ;
    USE SIGNAL ;
    PORT
      LAYER M4 ;
        RECT  0 51.792 0.084 51.816 ;
    END
  END d[348]
  PIN d[349]
    DIRECTION INPUT ;
    USE SIGNAL ;
    PORT
      LAYER M4 ;
        RECT  0 51.888 0.084 51.912 ;
    END
  END d[349]
  PIN d[34]
    DIRECTION INPUT ;
    USE SIGNAL ;
    PORT
      LAYER M4 ;
        RECT  0 33.168 0.084 33.192 ;
    END
  END d[34]
  PIN d[350]
    DIRECTION INPUT ;
    USE SIGNAL ;
    PORT
      LAYER M4 ;
        RECT  0 51.984 0.084 52.008 ;
    END
  END d[350]
  PIN d[351]
    DIRECTION INPUT ;
    USE SIGNAL ;
    PORT
      LAYER M4 ;
        RECT  0 45.936 0.084 45.96 ;
    END
  END d[351]
  PIN d[352]
    DIRECTION INPUT ;
    USE SIGNAL ;
    PORT
      LAYER M4 ;
        RECT  0 46.032 0.084 46.056 ;
    END
  END d[352]
  PIN d[353]
    DIRECTION INPUT ;
    USE SIGNAL ;
    PORT
      LAYER M4 ;
        RECT  0 46.128 0.084 46.152 ;
    END
  END d[353]
  PIN d[354]
    DIRECTION INPUT ;
    USE SIGNAL ;
    PORT
      LAYER M4 ;
        RECT  0 46.224 0.084 46.248 ;
    END
  END d[354]
  PIN d[355]
    DIRECTION INPUT ;
    USE SIGNAL ;
    PORT
      LAYER M4 ;
        RECT  0 46.32 0.084 46.344 ;
    END
  END d[355]
  PIN d[356]
    DIRECTION INPUT ;
    USE SIGNAL ;
    PORT
      LAYER M4 ;
        RECT  0 46.416 0.084 46.44 ;
    END
  END d[356]
  PIN d[357]
    DIRECTION INPUT ;
    USE SIGNAL ;
    PORT
      LAYER M4 ;
        RECT  0 46.512 0.084 46.536 ;
    END
  END d[357]
  PIN d[358]
    DIRECTION INPUT ;
    USE SIGNAL ;
    PORT
      LAYER M4 ;
        RECT  0 46.608 0.084 46.632 ;
    END
  END d[358]
  PIN d[359]
    DIRECTION INPUT ;
    USE SIGNAL ;
    PORT
      LAYER M4 ;
        RECT  0 46.704 0.084 46.728 ;
    END
  END d[359]
  PIN d[35]
    DIRECTION INPUT ;
    USE SIGNAL ;
    PORT
      LAYER M4 ;
        RECT  0 33.264 0.084 33.288 ;
    END
  END d[35]
  PIN d[360]
    DIRECTION INPUT ;
    USE SIGNAL ;
    PORT
      LAYER M4 ;
        RECT  0 46.8 0.084 46.824 ;
    END
  END d[360]
  PIN d[361]
    DIRECTION INPUT ;
    USE SIGNAL ;
    PORT
      LAYER M4 ;
        RECT  0 46.896 0.084 46.92 ;
    END
  END d[361]
  PIN d[362]
    DIRECTION INPUT ;
    USE SIGNAL ;
    PORT
      LAYER M4 ;
        RECT  0 46.992 0.084 47.016 ;
    END
  END d[362]
  PIN d[363]
    DIRECTION INPUT ;
    USE SIGNAL ;
    PORT
      LAYER M4 ;
        RECT  0 47.088 0.084 47.112 ;
    END
  END d[363]
  PIN d[364]
    DIRECTION INPUT ;
    USE SIGNAL ;
    PORT
      LAYER M4 ;
        RECT  0 47.184 0.084 47.208 ;
    END
  END d[364]
  PIN d[365]
    DIRECTION INPUT ;
    USE SIGNAL ;
    PORT
      LAYER M4 ;
        RECT  0 47.28 0.084 47.304 ;
    END
  END d[365]
  PIN d[366]
    DIRECTION INPUT ;
    USE SIGNAL ;
    PORT
      LAYER M4 ;
        RECT  0 47.376 0.084 47.4 ;
    END
  END d[366]
  PIN d[367]
    DIRECTION INPUT ;
    USE SIGNAL ;
    PORT
      LAYER M4 ;
        RECT  0 47.472 0.084 47.496 ;
    END
  END d[367]
  PIN d[368]
    DIRECTION INPUT ;
    USE SIGNAL ;
    PORT
      LAYER M4 ;
        RECT  0 47.568 0.084 47.592 ;
    END
  END d[368]
  PIN d[369]
    DIRECTION INPUT ;
    USE SIGNAL ;
    PORT
      LAYER M4 ;
        RECT  0 47.664 0.084 47.688 ;
    END
  END d[369]
  PIN d[36]
    DIRECTION INPUT ;
    USE SIGNAL ;
    PORT
      LAYER M4 ;
        RECT  0 33.36 0.084 33.384 ;
    END
  END d[36]
  PIN d[370]
    DIRECTION INPUT ;
    USE SIGNAL ;
    PORT
      LAYER M4 ;
        RECT  0 47.76 0.084 47.784 ;
    END
  END d[370]
  PIN d[371]
    DIRECTION INPUT ;
    USE SIGNAL ;
    PORT
      LAYER M4 ;
        RECT  0 47.856 0.084 47.88 ;
    END
  END d[371]
  PIN d[372]
    DIRECTION INPUT ;
    USE SIGNAL ;
    PORT
      LAYER M4 ;
        RECT  0 47.952 0.084 47.976 ;
    END
  END d[372]
  PIN d[373]
    DIRECTION INPUT ;
    USE SIGNAL ;
    PORT
      LAYER M4 ;
        RECT  0 48.048 0.084 48.072 ;
    END
  END d[373]
  PIN d[374]
    DIRECTION INPUT ;
    USE SIGNAL ;
    PORT
      LAYER M4 ;
        RECT  0 48.144 0.084 48.168 ;
    END
  END d[374]
  PIN d[375]
    DIRECTION INPUT ;
    USE SIGNAL ;
    PORT
      LAYER M4 ;
        RECT  0 48.24 0.084 48.264 ;
    END
  END d[375]
  PIN d[376]
    DIRECTION INPUT ;
    USE SIGNAL ;
    PORT
      LAYER M4 ;
        RECT  0 48.336 0.084 48.36 ;
    END
  END d[376]
  PIN d[377]
    DIRECTION INPUT ;
    USE SIGNAL ;
    PORT
      LAYER M4 ;
        RECT  0 48.432 0.084 48.456 ;
    END
  END d[377]
  PIN d[378]
    DIRECTION INPUT ;
    USE SIGNAL ;
    PORT
      LAYER M4 ;
        RECT  0 48.528 0.084 48.552 ;
    END
  END d[378]
  PIN d[379]
    DIRECTION INPUT ;
    USE SIGNAL ;
    PORT
      LAYER M4 ;
        RECT  0 48.624 0.084 48.648 ;
    END
  END d[379]
  PIN d[37]
    DIRECTION INPUT ;
    USE SIGNAL ;
    PORT
      LAYER M4 ;
        RECT  0 33.456 0.084 33.48 ;
    END
  END d[37]
  PIN d[380]
    DIRECTION INPUT ;
    USE SIGNAL ;
    PORT
      LAYER M4 ;
        RECT  0 48.72 0.084 48.744 ;
    END
  END d[380]
  PIN d[381]
    DIRECTION INPUT ;
    USE SIGNAL ;
    PORT
      LAYER M4 ;
        RECT  0 48.816 0.084 48.84 ;
    END
  END d[381]
  PIN d[382]
    DIRECTION INPUT ;
    USE SIGNAL ;
    PORT
      LAYER M4 ;
        RECT  0 48.912 0.084 48.936 ;
    END
  END d[382]
  PIN d[383]
    DIRECTION INPUT ;
    USE SIGNAL ;
    PORT
      LAYER M4 ;
        RECT  0 65.136 0.084 65.16 ;
    END
  END d[383]
  PIN d[384]
    DIRECTION INPUT ;
    USE SIGNAL ;
    PORT
      LAYER M4 ;
        RECT  0 65.232 0.084 65.256 ;
    END
  END d[384]
  PIN d[385]
    DIRECTION INPUT ;
    USE SIGNAL ;
    PORT
      LAYER M4 ;
        RECT  0 65.328 0.084 65.352 ;
    END
  END d[385]
  PIN d[386]
    DIRECTION INPUT ;
    USE SIGNAL ;
    PORT
      LAYER M4 ;
        RECT  0 65.424 0.084 65.448 ;
    END
  END d[386]
  PIN d[387]
    DIRECTION INPUT ;
    USE SIGNAL ;
    PORT
      LAYER M4 ;
        RECT  0 65.52 0.084 65.544 ;
    END
  END d[387]
  PIN d[388]
    DIRECTION INPUT ;
    USE SIGNAL ;
    PORT
      LAYER M4 ;
        RECT  0 65.616 0.084 65.64 ;
    END
  END d[388]
  PIN d[389]
    DIRECTION INPUT ;
    USE SIGNAL ;
    PORT
      LAYER M4 ;
        RECT  0 65.712 0.084 65.736 ;
    END
  END d[389]
  PIN d[38]
    DIRECTION INPUT ;
    USE SIGNAL ;
    PORT
      LAYER M4 ;
        RECT  0 33.552 0.084 33.576 ;
    END
  END d[38]
  PIN d[390]
    DIRECTION INPUT ;
    USE SIGNAL ;
    PORT
      LAYER M4 ;
        RECT  0 65.808 0.084 65.832 ;
    END
  END d[390]
  PIN d[391]
    DIRECTION INPUT ;
    USE SIGNAL ;
    PORT
      LAYER M4 ;
        RECT  0 65.904 0.084 65.928 ;
    END
  END d[391]
  PIN d[392]
    DIRECTION INPUT ;
    USE SIGNAL ;
    PORT
      LAYER M4 ;
        RECT  0 66 0.084 66.024 ;
    END
  END d[392]
  PIN d[393]
    DIRECTION INPUT ;
    USE SIGNAL ;
    PORT
      LAYER M4 ;
        RECT  0 66.096 0.084 66.12 ;
    END
  END d[393]
  PIN d[394]
    DIRECTION INPUT ;
    USE SIGNAL ;
    PORT
      LAYER M4 ;
        RECT  0 66.192 0.084 66.216 ;
    END
  END d[394]
  PIN d[395]
    DIRECTION INPUT ;
    USE SIGNAL ;
    PORT
      LAYER M4 ;
        RECT  0 66.288 0.084 66.312 ;
    END
  END d[395]
  PIN d[396]
    DIRECTION INPUT ;
    USE SIGNAL ;
    PORT
      LAYER M4 ;
        RECT  0 66.384 0.084 66.408 ;
    END
  END d[396]
  PIN d[397]
    DIRECTION INPUT ;
    USE SIGNAL ;
    PORT
      LAYER M4 ;
        RECT  0 66.48 0.084 66.504 ;
    END
  END d[397]
  PIN d[398]
    DIRECTION INPUT ;
    USE SIGNAL ;
    PORT
      LAYER M4 ;
        RECT  0 66.576 0.084 66.6 ;
    END
  END d[398]
  PIN d[399]
    DIRECTION INPUT ;
    USE SIGNAL ;
    PORT
      LAYER M4 ;
        RECT  0 66.672 0.084 66.696 ;
    END
  END d[399]
  PIN d[39]
    DIRECTION INPUT ;
    USE SIGNAL ;
    PORT
      LAYER M4 ;
        RECT  0 33.648 0.084 33.672 ;
    END
  END d[39]
  PIN d[3]
    DIRECTION INPUT ;
    USE SIGNAL ;
    PORT
      LAYER M4 ;
        RECT  0 39.408 0.084 39.432 ;
    END
  END d[3]
  PIN d[400]
    DIRECTION INPUT ;
    USE SIGNAL ;
    PORT
      LAYER M4 ;
        RECT  0 66.768 0.084 66.792 ;
    END
  END d[400]
  PIN d[401]
    DIRECTION INPUT ;
    USE SIGNAL ;
    PORT
      LAYER M4 ;
        RECT  0 66.864 0.084 66.888 ;
    END
  END d[401]
  PIN d[402]
    DIRECTION INPUT ;
    USE SIGNAL ;
    PORT
      LAYER M4 ;
        RECT  0 66.96 0.084 66.984 ;
    END
  END d[402]
  PIN d[403]
    DIRECTION INPUT ;
    USE SIGNAL ;
    PORT
      LAYER M4 ;
        RECT  0 67.056 0.084 67.08 ;
    END
  END d[403]
  PIN d[404]
    DIRECTION INPUT ;
    USE SIGNAL ;
    PORT
      LAYER M4 ;
        RECT  0 67.152 0.084 67.176 ;
    END
  END d[404]
  PIN d[405]
    DIRECTION INPUT ;
    USE SIGNAL ;
    PORT
      LAYER M4 ;
        RECT  0 67.248 0.084 67.272 ;
    END
  END d[405]
  PIN d[406]
    DIRECTION INPUT ;
    USE SIGNAL ;
    PORT
      LAYER M4 ;
        RECT  0 67.344 0.084 67.368 ;
    END
  END d[406]
  PIN d[407]
    DIRECTION INPUT ;
    USE SIGNAL ;
    PORT
      LAYER M4 ;
        RECT  0 67.44 0.084 67.464 ;
    END
  END d[407]
  PIN d[408]
    DIRECTION INPUT ;
    USE SIGNAL ;
    PORT
      LAYER M4 ;
        RECT  0 67.536 0.084 67.56 ;
    END
  END d[408]
  PIN d[409]
    DIRECTION INPUT ;
    USE SIGNAL ;
    PORT
      LAYER M4 ;
        RECT  0 67.632 0.084 67.656 ;
    END
  END d[409]
  PIN d[40]
    DIRECTION INPUT ;
    USE SIGNAL ;
    PORT
      LAYER M4 ;
        RECT  0 33.744 0.084 33.768 ;
    END
  END d[40]
  PIN d[410]
    DIRECTION INPUT ;
    USE SIGNAL ;
    PORT
      LAYER M4 ;
        RECT  0 67.728 0.084 67.752 ;
    END
  END d[410]
  PIN d[411]
    DIRECTION INPUT ;
    USE SIGNAL ;
    PORT
      LAYER M4 ;
        RECT  0 67.824 0.084 67.848 ;
    END
  END d[411]
  PIN d[412]
    DIRECTION INPUT ;
    USE SIGNAL ;
    PORT
      LAYER M4 ;
        RECT  0 67.92 0.084 67.944 ;
    END
  END d[412]
  PIN d[413]
    DIRECTION INPUT ;
    USE SIGNAL ;
    PORT
      LAYER M4 ;
        RECT  0 68.016 0.084 68.04 ;
    END
  END d[413]
  PIN d[414]
    DIRECTION INPUT ;
    USE SIGNAL ;
    PORT
      LAYER M4 ;
        RECT  0 68.112 0.084 68.136 ;
    END
  END d[414]
  PIN d[415]
    DIRECTION INPUT ;
    USE SIGNAL ;
    PORT
      LAYER M4 ;
        RECT  0 19.824 0.084 19.848 ;
    END
  END d[415]
  PIN d[416]
    DIRECTION INPUT ;
    USE SIGNAL ;
    PORT
      LAYER M4 ;
        RECT  0 19.92 0.084 19.944 ;
    END
  END d[416]
  PIN d[417]
    DIRECTION INPUT ;
    USE SIGNAL ;
    PORT
      LAYER M4 ;
        RECT  0 20.016 0.084 20.04 ;
    END
  END d[417]
  PIN d[418]
    DIRECTION INPUT ;
    USE SIGNAL ;
    PORT
      LAYER M4 ;
        RECT  0 20.112 0.084 20.136 ;
    END
  END d[418]
  PIN d[419]
    DIRECTION INPUT ;
    USE SIGNAL ;
    PORT
      LAYER M4 ;
        RECT  0 20.208 0.084 20.232 ;
    END
  END d[419]
  PIN d[41]
    DIRECTION INPUT ;
    USE SIGNAL ;
    PORT
      LAYER M4 ;
        RECT  0 33.84 0.084 33.864 ;
    END
  END d[41]
  PIN d[420]
    DIRECTION INPUT ;
    USE SIGNAL ;
    PORT
      LAYER M4 ;
        RECT  0 20.304 0.084 20.328 ;
    END
  END d[420]
  PIN d[421]
    DIRECTION INPUT ;
    USE SIGNAL ;
    PORT
      LAYER M4 ;
        RECT  0 20.4 0.084 20.424 ;
    END
  END d[421]
  PIN d[422]
    DIRECTION INPUT ;
    USE SIGNAL ;
    PORT
      LAYER M4 ;
        RECT  0 20.496 0.084 20.52 ;
    END
  END d[422]
  PIN d[423]
    DIRECTION INPUT ;
    USE SIGNAL ;
    PORT
      LAYER M4 ;
        RECT  0 20.592 0.084 20.616 ;
    END
  END d[423]
  PIN d[424]
    DIRECTION INPUT ;
    USE SIGNAL ;
    PORT
      LAYER M4 ;
        RECT  0 20.688 0.084 20.712 ;
    END
  END d[424]
  PIN d[425]
    DIRECTION INPUT ;
    USE SIGNAL ;
    PORT
      LAYER M4 ;
        RECT  0 20.784 0.084 20.808 ;
    END
  END d[425]
  PIN d[426]
    DIRECTION INPUT ;
    USE SIGNAL ;
    PORT
      LAYER M4 ;
        RECT  0 20.88 0.084 20.904 ;
    END
  END d[426]
  PIN d[427]
    DIRECTION INPUT ;
    USE SIGNAL ;
    PORT
      LAYER M4 ;
        RECT  0 20.976 0.084 21 ;
    END
  END d[427]
  PIN d[428]
    DIRECTION INPUT ;
    USE SIGNAL ;
    PORT
      LAYER M4 ;
        RECT  0 21.072 0.084 21.096 ;
    END
  END d[428]
  PIN d[429]
    DIRECTION INPUT ;
    USE SIGNAL ;
    PORT
      LAYER M4 ;
        RECT  0 21.168 0.084 21.192 ;
    END
  END d[429]
  PIN d[42]
    DIRECTION INPUT ;
    USE SIGNAL ;
    PORT
      LAYER M4 ;
        RECT  0 33.936 0.084 33.96 ;
    END
  END d[42]
  PIN d[430]
    DIRECTION INPUT ;
    USE SIGNAL ;
    PORT
      LAYER M4 ;
        RECT  0 21.264 0.084 21.288 ;
    END
  END d[430]
  PIN d[431]
    DIRECTION INPUT ;
    USE SIGNAL ;
    PORT
      LAYER M4 ;
        RECT  0 21.36 0.084 21.384 ;
    END
  END d[431]
  PIN d[432]
    DIRECTION INPUT ;
    USE SIGNAL ;
    PORT
      LAYER M4 ;
        RECT  0 21.456 0.084 21.48 ;
    END
  END d[432]
  PIN d[433]
    DIRECTION INPUT ;
    USE SIGNAL ;
    PORT
      LAYER M4 ;
        RECT  0 21.552 0.084 21.576 ;
    END
  END d[433]
  PIN d[434]
    DIRECTION INPUT ;
    USE SIGNAL ;
    PORT
      LAYER M4 ;
        RECT  0 21.648 0.084 21.672 ;
    END
  END d[434]
  PIN d[435]
    DIRECTION INPUT ;
    USE SIGNAL ;
    PORT
      LAYER M4 ;
        RECT  0 21.744 0.084 21.768 ;
    END
  END d[435]
  PIN d[436]
    DIRECTION INPUT ;
    USE SIGNAL ;
    PORT
      LAYER M4 ;
        RECT  0 21.84 0.084 21.864 ;
    END
  END d[436]
  PIN d[437]
    DIRECTION INPUT ;
    USE SIGNAL ;
    PORT
      LAYER M4 ;
        RECT  0 21.936 0.084 21.96 ;
    END
  END d[437]
  PIN d[438]
    DIRECTION INPUT ;
    USE SIGNAL ;
    PORT
      LAYER M4 ;
        RECT  0 22.032 0.084 22.056 ;
    END
  END d[438]
  PIN d[439]
    DIRECTION INPUT ;
    USE SIGNAL ;
    PORT
      LAYER M4 ;
        RECT  0 22.128 0.084 22.152 ;
    END
  END d[439]
  PIN d[43]
    DIRECTION INPUT ;
    USE SIGNAL ;
    PORT
      LAYER M4 ;
        RECT  0 34.032 0.084 34.056 ;
    END
  END d[43]
  PIN d[440]
    DIRECTION INPUT ;
    USE SIGNAL ;
    PORT
      LAYER M4 ;
        RECT  0 22.224 0.084 22.248 ;
    END
  END d[440]
  PIN d[441]
    DIRECTION INPUT ;
    USE SIGNAL ;
    PORT
      LAYER M4 ;
        RECT  0 22.32 0.084 22.344 ;
    END
  END d[441]
  PIN d[442]
    DIRECTION INPUT ;
    USE SIGNAL ;
    PORT
      LAYER M4 ;
        RECT  0 22.416 0.084 22.44 ;
    END
  END d[442]
  PIN d[443]
    DIRECTION INPUT ;
    USE SIGNAL ;
    PORT
      LAYER M4 ;
        RECT  0 22.512 0.084 22.536 ;
    END
  END d[443]
  PIN d[444]
    DIRECTION INPUT ;
    USE SIGNAL ;
    PORT
      LAYER M4 ;
        RECT  0 22.608 0.084 22.632 ;
    END
  END d[444]
  PIN d[445]
    DIRECTION INPUT ;
    USE SIGNAL ;
    PORT
      LAYER M4 ;
        RECT  0 22.704 0.084 22.728 ;
    END
  END d[445]
  PIN d[446]
    DIRECTION INPUT ;
    USE SIGNAL ;
    PORT
      LAYER M4 ;
        RECT  0 22.8 0.084 22.824 ;
    END
  END d[446]
  PIN d[447]
    DIRECTION INPUT ;
    USE SIGNAL ;
    PORT
      LAYER M4 ;
        RECT  0 22.896 0.084 22.92 ;
    END
  END d[447]
  PIN d[448]
    DIRECTION INPUT ;
    USE SIGNAL ;
    PORT
      LAYER M4 ;
        RECT  0 22.992 0.084 23.016 ;
    END
  END d[448]
  PIN d[449]
    DIRECTION INPUT ;
    USE SIGNAL ;
    PORT
      LAYER M4 ;
        RECT  0 23.088 0.084 23.112 ;
    END
  END d[449]
  PIN d[44]
    DIRECTION INPUT ;
    USE SIGNAL ;
    PORT
      LAYER M4 ;
        RECT  0 34.128 0.084 34.152 ;
    END
  END d[44]
  PIN d[450]
    DIRECTION INPUT ;
    USE SIGNAL ;
    PORT
      LAYER M4 ;
        RECT  0 23.184 0.084 23.208 ;
    END
  END d[450]
  PIN d[451]
    DIRECTION INPUT ;
    USE SIGNAL ;
    PORT
      LAYER M4 ;
        RECT  0 23.28 0.084 23.304 ;
    END
  END d[451]
  PIN d[452]
    DIRECTION INPUT ;
    USE SIGNAL ;
    PORT
      LAYER M4 ;
        RECT  0 23.376 0.084 23.4 ;
    END
  END d[452]
  PIN d[453]
    DIRECTION INPUT ;
    USE SIGNAL ;
    PORT
      LAYER M4 ;
        RECT  0 23.472 0.084 23.496 ;
    END
  END d[453]
  PIN d[454]
    DIRECTION INPUT ;
    USE SIGNAL ;
    PORT
      LAYER M4 ;
        RECT  0 23.568 0.084 23.592 ;
    END
  END d[454]
  PIN d[455]
    DIRECTION INPUT ;
    USE SIGNAL ;
    PORT
      LAYER M4 ;
        RECT  0 23.664 0.084 23.688 ;
    END
  END d[455]
  PIN d[456]
    DIRECTION INPUT ;
    USE SIGNAL ;
    PORT
      LAYER M4 ;
        RECT  0 23.76 0.084 23.784 ;
    END
  END d[456]
  PIN d[457]
    DIRECTION INPUT ;
    USE SIGNAL ;
    PORT
      LAYER M4 ;
        RECT  0 23.856 0.084 23.88 ;
    END
  END d[457]
  PIN d[458]
    DIRECTION INPUT ;
    USE SIGNAL ;
    PORT
      LAYER M4 ;
        RECT  0 23.952 0.084 23.976 ;
    END
  END d[458]
  PIN d[459]
    DIRECTION INPUT ;
    USE SIGNAL ;
    PORT
      LAYER M4 ;
        RECT  0 24.048 0.084 24.072 ;
    END
  END d[459]
  PIN d[45]
    DIRECTION INPUT ;
    USE SIGNAL ;
    PORT
      LAYER M4 ;
        RECT  0 34.224 0.084 34.248 ;
    END
  END d[45]
  PIN d[460]
    DIRECTION INPUT ;
    USE SIGNAL ;
    PORT
      LAYER M4 ;
        RECT  0 24.144 0.084 24.168 ;
    END
  END d[460]
  PIN d[461]
    DIRECTION INPUT ;
    USE SIGNAL ;
    PORT
      LAYER M4 ;
        RECT  0 24.24 0.084 24.264 ;
    END
  END d[461]
  PIN d[462]
    DIRECTION INPUT ;
    USE SIGNAL ;
    PORT
      LAYER M4 ;
        RECT  0 24.336 0.084 24.36 ;
    END
  END d[462]
  PIN d[463]
    DIRECTION INPUT ;
    USE SIGNAL ;
    PORT
      LAYER M4 ;
        RECT  0 24.432 0.084 24.456 ;
    END
  END d[463]
  PIN d[464]
    DIRECTION INPUT ;
    USE SIGNAL ;
    PORT
      LAYER M4 ;
        RECT  0 24.528 0.084 24.552 ;
    END
  END d[464]
  PIN d[465]
    DIRECTION INPUT ;
    USE SIGNAL ;
    PORT
      LAYER M4 ;
        RECT  0 24.624 0.084 24.648 ;
    END
  END d[465]
  PIN d[466]
    DIRECTION INPUT ;
    USE SIGNAL ;
    PORT
      LAYER M4 ;
        RECT  0 24.72 0.084 24.744 ;
    END
  END d[466]
  PIN d[467]
    DIRECTION INPUT ;
    USE SIGNAL ;
    PORT
      LAYER M4 ;
        RECT  0 24.816 0.084 24.84 ;
    END
  END d[467]
  PIN d[468]
    DIRECTION INPUT ;
    USE SIGNAL ;
    PORT
      LAYER M4 ;
        RECT  0 24.912 0.084 24.936 ;
    END
  END d[468]
  PIN d[469]
    DIRECTION INPUT ;
    USE SIGNAL ;
    PORT
      LAYER M4 ;
        RECT  0 25.008 0.084 25.032 ;
    END
  END d[469]
  PIN d[46]
    DIRECTION INPUT ;
    USE SIGNAL ;
    PORT
      LAYER M4 ;
        RECT  0 34.32 0.084 34.344 ;
    END
  END d[46]
  PIN d[470]
    DIRECTION INPUT ;
    USE SIGNAL ;
    PORT
      LAYER M4 ;
        RECT  0 25.104 0.084 25.128 ;
    END
  END d[470]
  PIN d[471]
    DIRECTION INPUT ;
    USE SIGNAL ;
    PORT
      LAYER M4 ;
        RECT  0 25.2 0.084 25.224 ;
    END
  END d[471]
  PIN d[472]
    DIRECTION INPUT ;
    USE SIGNAL ;
    PORT
      LAYER M4 ;
        RECT  0 25.296 0.084 25.32 ;
    END
  END d[472]
  PIN d[473]
    DIRECTION INPUT ;
    USE SIGNAL ;
    PORT
      LAYER M4 ;
        RECT  0 25.392 0.084 25.416 ;
    END
  END d[473]
  PIN d[474]
    DIRECTION INPUT ;
    USE SIGNAL ;
    PORT
      LAYER M4 ;
        RECT  0 25.488 0.084 25.512 ;
    END
  END d[474]
  PIN d[475]
    DIRECTION INPUT ;
    USE SIGNAL ;
    PORT
      LAYER M4 ;
        RECT  0 25.584 0.084 25.608 ;
    END
  END d[475]
  PIN d[476]
    DIRECTION INPUT ;
    USE SIGNAL ;
    PORT
      LAYER M4 ;
        RECT  0 25.68 0.084 25.704 ;
    END
  END d[476]
  PIN d[477]
    DIRECTION INPUT ;
    USE SIGNAL ;
    PORT
      LAYER M4 ;
        RECT  0 25.776 0.084 25.8 ;
    END
  END d[477]
  PIN d[478]
    DIRECTION INPUT ;
    USE SIGNAL ;
    PORT
      LAYER M4 ;
        RECT  0 25.872 0.084 25.896 ;
    END
  END d[478]
  PIN d[479]
    DIRECTION INPUT ;
    USE SIGNAL ;
    PORT
      LAYER M4 ;
        RECT  0 68.208 0.084 68.232 ;
    END
  END d[479]
  PIN d[47]
    DIRECTION INPUT ;
    USE SIGNAL ;
    PORT
      LAYER M4 ;
        RECT  0 34.416 0.084 34.44 ;
    END
  END d[47]
  PIN d[480]
    DIRECTION INPUT ;
    USE SIGNAL ;
    PORT
      LAYER M4 ;
        RECT  0 68.304 0.084 68.328 ;
    END
  END d[480]
  PIN d[481]
    DIRECTION INPUT ;
    USE SIGNAL ;
    PORT
      LAYER M4 ;
        RECT  0 68.4 0.084 68.424 ;
    END
  END d[481]
  PIN d[482]
    DIRECTION INPUT ;
    USE SIGNAL ;
    PORT
      LAYER M4 ;
        RECT  0 68.496 0.084 68.52 ;
    END
  END d[482]
  PIN d[483]
    DIRECTION INPUT ;
    USE SIGNAL ;
    PORT
      LAYER M4 ;
        RECT  0 68.592 0.084 68.616 ;
    END
  END d[483]
  PIN d[484]
    DIRECTION INPUT ;
    USE SIGNAL ;
    PORT
      LAYER M4 ;
        RECT  0 68.688 0.084 68.712 ;
    END
  END d[484]
  PIN d[485]
    DIRECTION INPUT ;
    USE SIGNAL ;
    PORT
      LAYER M4 ;
        RECT  0 68.784 0.084 68.808 ;
    END
  END d[485]
  PIN d[486]
    DIRECTION INPUT ;
    USE SIGNAL ;
    PORT
      LAYER M4 ;
        RECT  0 68.88 0.084 68.904 ;
    END
  END d[486]
  PIN d[487]
    DIRECTION INPUT ;
    USE SIGNAL ;
    PORT
      LAYER M4 ;
        RECT  0 68.976 0.084 69 ;
    END
  END d[487]
  PIN d[488]
    DIRECTION INPUT ;
    USE SIGNAL ;
    PORT
      LAYER M4 ;
        RECT  0 69.072 0.084 69.096 ;
    END
  END d[488]
  PIN d[489]
    DIRECTION INPUT ;
    USE SIGNAL ;
    PORT
      LAYER M4 ;
        RECT  0 69.168 0.084 69.192 ;
    END
  END d[489]
  PIN d[48]
    DIRECTION INPUT ;
    USE SIGNAL ;
    PORT
      LAYER M4 ;
        RECT  0 34.512 0.084 34.536 ;
    END
  END d[48]
  PIN d[490]
    DIRECTION INPUT ;
    USE SIGNAL ;
    PORT
      LAYER M4 ;
        RECT  0 69.264 0.084 69.288 ;
    END
  END d[490]
  PIN d[491]
    DIRECTION INPUT ;
    USE SIGNAL ;
    PORT
      LAYER M4 ;
        RECT  0 69.36 0.084 69.384 ;
    END
  END d[491]
  PIN d[492]
    DIRECTION INPUT ;
    USE SIGNAL ;
    PORT
      LAYER M4 ;
        RECT  0 69.456 0.084 69.48 ;
    END
  END d[492]
  PIN d[493]
    DIRECTION INPUT ;
    USE SIGNAL ;
    PORT
      LAYER M4 ;
        RECT  0 69.552 0.084 69.576 ;
    END
  END d[493]
  PIN d[494]
    DIRECTION INPUT ;
    USE SIGNAL ;
    PORT
      LAYER M4 ;
        RECT  0 69.648 0.084 69.672 ;
    END
  END d[494]
  PIN d[495]
    DIRECTION INPUT ;
    USE SIGNAL ;
    PORT
      LAYER M4 ;
        RECT  0 69.744 0.084 69.768 ;
    END
  END d[495]
  PIN d[496]
    DIRECTION INPUT ;
    USE SIGNAL ;
    PORT
      LAYER M4 ;
        RECT  0 69.84 0.084 69.864 ;
    END
  END d[496]
  PIN d[497]
    DIRECTION INPUT ;
    USE SIGNAL ;
    PORT
      LAYER M4 ;
        RECT  0 69.936 0.084 69.96 ;
    END
  END d[497]
  PIN d[498]
    DIRECTION INPUT ;
    USE SIGNAL ;
    PORT
      LAYER M4 ;
        RECT  0 70.032 0.084 70.056 ;
    END
  END d[498]
  PIN d[499]
    DIRECTION INPUT ;
    USE SIGNAL ;
    PORT
      LAYER M4 ;
        RECT  0 70.128 0.084 70.152 ;
    END
  END d[499]
  PIN d[49]
    DIRECTION INPUT ;
    USE SIGNAL ;
    PORT
      LAYER M4 ;
        RECT  0 34.608 0.084 34.632 ;
    END
  END d[49]
  PIN d[4]
    DIRECTION INPUT ;
    USE SIGNAL ;
    PORT
      LAYER M4 ;
        RECT  0 39.504 0.084 39.528 ;
    END
  END d[4]
  PIN d[500]
    DIRECTION INPUT ;
    USE SIGNAL ;
    PORT
      LAYER M4 ;
        RECT  0 70.224 0.084 70.248 ;
    END
  END d[500]
  PIN d[501]
    DIRECTION INPUT ;
    USE SIGNAL ;
    PORT
      LAYER M4 ;
        RECT  0 70.32 0.084 70.344 ;
    END
  END d[501]
  PIN d[502]
    DIRECTION INPUT ;
    USE SIGNAL ;
    PORT
      LAYER M4 ;
        RECT  0 70.416 0.084 70.44 ;
    END
  END d[502]
  PIN d[503]
    DIRECTION INPUT ;
    USE SIGNAL ;
    PORT
      LAYER M4 ;
        RECT  0 70.512 0.084 70.536 ;
    END
  END d[503]
  PIN d[504]
    DIRECTION INPUT ;
    USE SIGNAL ;
    PORT
      LAYER M4 ;
        RECT  0 70.608 0.084 70.632 ;
    END
  END d[504]
  PIN d[505]
    DIRECTION INPUT ;
    USE SIGNAL ;
    PORT
      LAYER M4 ;
        RECT  0 70.704 0.084 70.728 ;
    END
  END d[505]
  PIN d[506]
    DIRECTION INPUT ;
    USE SIGNAL ;
    PORT
      LAYER M4 ;
        RECT  0 70.8 0.084 70.824 ;
    END
  END d[506]
  PIN d[507]
    DIRECTION INPUT ;
    USE SIGNAL ;
    PORT
      LAYER M4 ;
        RECT  0 70.896 0.084 70.92 ;
    END
  END d[507]
  PIN d[508]
    DIRECTION INPUT ;
    USE SIGNAL ;
    PORT
      LAYER M4 ;
        RECT  0 70.992 0.084 71.016 ;
    END
  END d[508]
  PIN d[509]
    DIRECTION INPUT ;
    USE SIGNAL ;
    PORT
      LAYER M4 ;
        RECT  0 71.088 0.084 71.112 ;
    END
  END d[509]
  PIN d[50]
    DIRECTION INPUT ;
    USE SIGNAL ;
    PORT
      LAYER M4 ;
        RECT  0 34.704 0.084 34.728 ;
    END
  END d[50]
  PIN d[510]
    DIRECTION INPUT ;
    USE SIGNAL ;
    PORT
      LAYER M4 ;
        RECT  0 71.184 0.084 71.208 ;
    END
  END d[510]
  PIN d[511]
    DIRECTION INPUT ;
    USE SIGNAL ;
    PORT
      LAYER M4 ;
        RECT  0 26.64 0.084 26.664 ;
    END
  END d[511]
  PIN d[51]
    DIRECTION INPUT ;
    USE SIGNAL ;
    PORT
      LAYER M4 ;
        RECT  0 34.8 0.084 34.824 ;
    END
  END d[51]
  PIN d[52]
    DIRECTION INPUT ;
    USE SIGNAL ;
    PORT
      LAYER M4 ;
        RECT  0 34.896 0.084 34.92 ;
    END
  END d[52]
  PIN d[53]
    DIRECTION INPUT ;
    USE SIGNAL ;
    PORT
      LAYER M4 ;
        RECT  0 34.992 0.084 35.016 ;
    END
  END d[53]
  PIN d[54]
    DIRECTION INPUT ;
    USE SIGNAL ;
    PORT
      LAYER M4 ;
        RECT  0 35.088 0.084 35.112 ;
    END
  END d[54]
  PIN d[55]
    DIRECTION INPUT ;
    USE SIGNAL ;
    PORT
      LAYER M4 ;
        RECT  0 35.184 0.084 35.208 ;
    END
  END d[55]
  PIN d[56]
    DIRECTION INPUT ;
    USE SIGNAL ;
    PORT
      LAYER M4 ;
        RECT  0 35.28 0.084 35.304 ;
    END
  END d[56]
  PIN d[57]
    DIRECTION INPUT ;
    USE SIGNAL ;
    PORT
      LAYER M4 ;
        RECT  0 35.376 0.084 35.4 ;
    END
  END d[57]
  PIN d[58]
    DIRECTION INPUT ;
    USE SIGNAL ;
    PORT
      LAYER M4 ;
        RECT  0 35.472 0.084 35.496 ;
    END
  END d[58]
  PIN d[59]
    DIRECTION INPUT ;
    USE SIGNAL ;
    PORT
      LAYER M4 ;
        RECT  0 35.568 0.084 35.592 ;
    END
  END d[59]
  PIN d[5]
    DIRECTION INPUT ;
    USE SIGNAL ;
    PORT
      LAYER M4 ;
        RECT  0 39.6 0.084 39.624 ;
    END
  END d[5]
  PIN d[60]
    DIRECTION INPUT ;
    USE SIGNAL ;
    PORT
      LAYER M4 ;
        RECT  0 35.664 0.084 35.688 ;
    END
  END d[60]
  PIN d[61]
    DIRECTION INPUT ;
    USE SIGNAL ;
    PORT
      LAYER M4 ;
        RECT  0 35.76 0.084 35.784 ;
    END
  END d[61]
  PIN d[62]
    DIRECTION INPUT ;
    USE SIGNAL ;
    PORT
      LAYER M4 ;
        RECT  0 35.856 0.084 35.88 ;
    END
  END d[62]
  PIN d[63]
    DIRECTION INPUT ;
    USE SIGNAL ;
    PORT
      LAYER M4 ;
        RECT  0 26.736 0.084 26.76 ;
    END
  END d[63]
  PIN d[64]
    DIRECTION INPUT ;
    USE SIGNAL ;
    PORT
      LAYER M4 ;
        RECT  0 26.832 0.084 26.856 ;
    END
  END d[64]
  PIN d[65]
    DIRECTION INPUT ;
    USE SIGNAL ;
    PORT
      LAYER M4 ;
        RECT  0 26.928 0.084 26.952 ;
    END
  END d[65]
  PIN d[66]
    DIRECTION INPUT ;
    USE SIGNAL ;
    PORT
      LAYER M4 ;
        RECT  0 27.024 0.084 27.048 ;
    END
  END d[66]
  PIN d[67]
    DIRECTION INPUT ;
    USE SIGNAL ;
    PORT
      LAYER M4 ;
        RECT  0 27.12 0.084 27.144 ;
    END
  END d[67]
  PIN d[68]
    DIRECTION INPUT ;
    USE SIGNAL ;
    PORT
      LAYER M4 ;
        RECT  0 27.216 0.084 27.24 ;
    END
  END d[68]
  PIN d[69]
    DIRECTION INPUT ;
    USE SIGNAL ;
    PORT
      LAYER M4 ;
        RECT  0 27.312 0.084 27.336 ;
    END
  END d[69]
  PIN d[6]
    DIRECTION INPUT ;
    USE SIGNAL ;
    PORT
      LAYER M4 ;
        RECT  0 39.696 0.084 39.72 ;
    END
  END d[6]
  PIN d[70]
    DIRECTION INPUT ;
    USE SIGNAL ;
    PORT
      LAYER M4 ;
        RECT  0 27.408 0.084 27.432 ;
    END
  END d[70]
  PIN d[71]
    DIRECTION INPUT ;
    USE SIGNAL ;
    PORT
      LAYER M4 ;
        RECT  0 27.504 0.084 27.528 ;
    END
  END d[71]
  PIN d[72]
    DIRECTION INPUT ;
    USE SIGNAL ;
    PORT
      LAYER M4 ;
        RECT  0 27.6 0.084 27.624 ;
    END
  END d[72]
  PIN d[73]
    DIRECTION INPUT ;
    USE SIGNAL ;
    PORT
      LAYER M4 ;
        RECT  0 27.696 0.084 27.72 ;
    END
  END d[73]
  PIN d[74]
    DIRECTION INPUT ;
    USE SIGNAL ;
    PORT
      LAYER M4 ;
        RECT  0 27.792 0.084 27.816 ;
    END
  END d[74]
  PIN d[75]
    DIRECTION INPUT ;
    USE SIGNAL ;
    PORT
      LAYER M4 ;
        RECT  0 27.888 0.084 27.912 ;
    END
  END d[75]
  PIN d[76]
    DIRECTION INPUT ;
    USE SIGNAL ;
    PORT
      LAYER M4 ;
        RECT  0 27.984 0.084 28.008 ;
    END
  END d[76]
  PIN d[77]
    DIRECTION INPUT ;
    USE SIGNAL ;
    PORT
      LAYER M4 ;
        RECT  0 28.08 0.084 28.104 ;
    END
  END d[77]
  PIN d[78]
    DIRECTION INPUT ;
    USE SIGNAL ;
    PORT
      LAYER M4 ;
        RECT  0 28.176 0.084 28.2 ;
    END
  END d[78]
  PIN d[79]
    DIRECTION INPUT ;
    USE SIGNAL ;
    PORT
      LAYER M4 ;
        RECT  0 28.272 0.084 28.296 ;
    END
  END d[79]
  PIN d[7]
    DIRECTION INPUT ;
    USE SIGNAL ;
    PORT
      LAYER M4 ;
        RECT  0 39.792 0.084 39.816 ;
    END
  END d[7]
  PIN d[80]
    DIRECTION INPUT ;
    USE SIGNAL ;
    PORT
      LAYER M4 ;
        RECT  0 28.368 0.084 28.392 ;
    END
  END d[80]
  PIN d[81]
    DIRECTION INPUT ;
    USE SIGNAL ;
    PORT
      LAYER M4 ;
        RECT  0 28.464 0.084 28.488 ;
    END
  END d[81]
  PIN d[82]
    DIRECTION INPUT ;
    USE SIGNAL ;
    PORT
      LAYER M4 ;
        RECT  0 28.56 0.084 28.584 ;
    END
  END d[82]
  PIN d[83]
    DIRECTION INPUT ;
    USE SIGNAL ;
    PORT
      LAYER M4 ;
        RECT  0 28.656 0.084 28.68 ;
    END
  END d[83]
  PIN d[84]
    DIRECTION INPUT ;
    USE SIGNAL ;
    PORT
      LAYER M4 ;
        RECT  0 28.752 0.084 28.776 ;
    END
  END d[84]
  PIN d[85]
    DIRECTION INPUT ;
    USE SIGNAL ;
    PORT
      LAYER M4 ;
        RECT  0 28.848 0.084 28.872 ;
    END
  END d[85]
  PIN d[86]
    DIRECTION INPUT ;
    USE SIGNAL ;
    PORT
      LAYER M4 ;
        RECT  0 28.944 0.084 28.968 ;
    END
  END d[86]
  PIN d[87]
    DIRECTION INPUT ;
    USE SIGNAL ;
    PORT
      LAYER M4 ;
        RECT  0 29.04 0.084 29.064 ;
    END
  END d[87]
  PIN d[88]
    DIRECTION INPUT ;
    USE SIGNAL ;
    PORT
      LAYER M4 ;
        RECT  0 29.136 0.084 29.16 ;
    END
  END d[88]
  PIN d[89]
    DIRECTION INPUT ;
    USE SIGNAL ;
    PORT
      LAYER M4 ;
        RECT  0 29.232 0.084 29.256 ;
    END
  END d[89]
  PIN d[8]
    DIRECTION INPUT ;
    USE SIGNAL ;
    PORT
      LAYER M4 ;
        RECT  0 39.888 0.084 39.912 ;
    END
  END d[8]
  PIN d[90]
    DIRECTION INPUT ;
    USE SIGNAL ;
    PORT
      LAYER M4 ;
        RECT  0 29.328 0.084 29.352 ;
    END
  END d[90]
  PIN d[91]
    DIRECTION INPUT ;
    USE SIGNAL ;
    PORT
      LAYER M4 ;
        RECT  0 29.424 0.084 29.448 ;
    END
  END d[91]
  PIN d[92]
    DIRECTION INPUT ;
    USE SIGNAL ;
    PORT
      LAYER M4 ;
        RECT  0 29.52 0.084 29.544 ;
    END
  END d[92]
  PIN d[93]
    DIRECTION INPUT ;
    USE SIGNAL ;
    PORT
      LAYER M4 ;
        RECT  0 29.616 0.084 29.64 ;
    END
  END d[93]
  PIN d[94]
    DIRECTION INPUT ;
    USE SIGNAL ;
    PORT
      LAYER M4 ;
        RECT  0 29.712 0.084 29.736 ;
    END
  END d[94]
  PIN d[95]
    DIRECTION INPUT ;
    USE SIGNAL ;
    PORT
      LAYER M4 ;
        RECT  0 58.224 0.084 58.248 ;
    END
  END d[95]
  PIN d[96]
    DIRECTION INPUT ;
    USE SIGNAL ;
    PORT
      LAYER M4 ;
        RECT  0 58.32 0.084 58.344 ;
    END
  END d[96]
  PIN d[97]
    DIRECTION INPUT ;
    USE SIGNAL ;
    PORT
      LAYER M4 ;
        RECT  0 58.416 0.084 58.44 ;
    END
  END d[97]
  PIN d[98]
    DIRECTION INPUT ;
    USE SIGNAL ;
    PORT
      LAYER M4 ;
        RECT  0 58.512 0.084 58.536 ;
    END
  END d[98]
  PIN d[99]
    DIRECTION INPUT ;
    USE SIGNAL ;
    PORT
      LAYER M4 ;
        RECT  0 58.608 0.084 58.632 ;
    END
  END d[99]
  PIN d[9]
    DIRECTION INPUT ;
    USE SIGNAL ;
    PORT
      LAYER M4 ;
        RECT  0 39.984 0.084 40.008 ;
    END
  END d[9]
  PIN q[0]
    DIRECTION OUTPUT ;
    USE SIGNAL ;
    PORT
      LAYER M4 ;
        RECT  32.316 19.92 32.4 19.944 ;
    END
  END q[0]
  PIN q[100]
    DIRECTION OUTPUT ;
    USE SIGNAL ;
    PORT
      LAYER M4 ;
        RECT  32.316 51.792 32.4 51.816 ;
    END
  END q[100]
  PIN q[101]
    DIRECTION OUTPUT ;
    USE SIGNAL ;
    PORT
      LAYER M4 ;
        RECT  32.316 51.888 32.4 51.912 ;
    END
  END q[101]
  PIN q[102]
    DIRECTION OUTPUT ;
    USE SIGNAL ;
    PORT
      LAYER M4 ;
        RECT  32.316 51.984 32.4 52.008 ;
    END
  END q[102]
  PIN q[103]
    DIRECTION OUTPUT ;
    USE SIGNAL ;
    PORT
      LAYER M4 ;
        RECT  32.316 52.08 32.4 52.104 ;
    END
  END q[103]
  PIN q[104]
    DIRECTION OUTPUT ;
    USE SIGNAL ;
    PORT
      LAYER M4 ;
        RECT  32.316 52.176 32.4 52.2 ;
    END
  END q[104]
  PIN q[105]
    DIRECTION OUTPUT ;
    USE SIGNAL ;
    PORT
      LAYER M4 ;
        RECT  32.316 52.272 32.4 52.296 ;
    END
  END q[105]
  PIN q[106]
    DIRECTION OUTPUT ;
    USE SIGNAL ;
    PORT
      LAYER M4 ;
        RECT  32.316 52.368 32.4 52.392 ;
    END
  END q[106]
  PIN q[107]
    DIRECTION OUTPUT ;
    USE SIGNAL ;
    PORT
      LAYER M4 ;
        RECT  32.316 52.464 32.4 52.488 ;
    END
  END q[107]
  PIN q[108]
    DIRECTION OUTPUT ;
    USE SIGNAL ;
    PORT
      LAYER M4 ;
        RECT  32.316 52.56 32.4 52.584 ;
    END
  END q[108]
  PIN q[109]
    DIRECTION OUTPUT ;
    USE SIGNAL ;
    PORT
      LAYER M4 ;
        RECT  32.316 52.656 32.4 52.68 ;
    END
  END q[109]
  PIN q[10]
    DIRECTION OUTPUT ;
    USE SIGNAL ;
    PORT
      LAYER M4 ;
        RECT  32.316 20.88 32.4 20.904 ;
    END
  END q[10]
  PIN q[110]
    DIRECTION OUTPUT ;
    USE SIGNAL ;
    PORT
      LAYER M4 ;
        RECT  32.316 52.752 32.4 52.776 ;
    END
  END q[110]
  PIN q[111]
    DIRECTION OUTPUT ;
    USE SIGNAL ;
    PORT
      LAYER M4 ;
        RECT  32.316 52.848 32.4 52.872 ;
    END
  END q[111]
  PIN q[112]
    DIRECTION OUTPUT ;
    USE SIGNAL ;
    PORT
      LAYER M4 ;
        RECT  32.316 52.944 32.4 52.968 ;
    END
  END q[112]
  PIN q[113]
    DIRECTION OUTPUT ;
    USE SIGNAL ;
    PORT
      LAYER M4 ;
        RECT  32.316 53.04 32.4 53.064 ;
    END
  END q[113]
  PIN q[114]
    DIRECTION OUTPUT ;
    USE SIGNAL ;
    PORT
      LAYER M4 ;
        RECT  32.316 53.136 32.4 53.16 ;
    END
  END q[114]
  PIN q[115]
    DIRECTION OUTPUT ;
    USE SIGNAL ;
    PORT
      LAYER M4 ;
        RECT  32.316 53.232 32.4 53.256 ;
    END
  END q[115]
  PIN q[116]
    DIRECTION OUTPUT ;
    USE SIGNAL ;
    PORT
      LAYER M4 ;
        RECT  32.316 53.328 32.4 53.352 ;
    END
  END q[116]
  PIN q[117]
    DIRECTION OUTPUT ;
    USE SIGNAL ;
    PORT
      LAYER M4 ;
        RECT  32.316 53.424 32.4 53.448 ;
    END
  END q[117]
  PIN q[118]
    DIRECTION OUTPUT ;
    USE SIGNAL ;
    PORT
      LAYER M4 ;
        RECT  32.316 53.52 32.4 53.544 ;
    END
  END q[118]
  PIN q[119]
    DIRECTION OUTPUT ;
    USE SIGNAL ;
    PORT
      LAYER M4 ;
        RECT  32.316 53.616 32.4 53.64 ;
    END
  END q[119]
  PIN q[11]
    DIRECTION OUTPUT ;
    USE SIGNAL ;
    PORT
      LAYER M4 ;
        RECT  32.316 20.976 32.4 21 ;
    END
  END q[11]
  PIN q[120]
    DIRECTION OUTPUT ;
    USE SIGNAL ;
    PORT
      LAYER M4 ;
        RECT  32.316 53.712 32.4 53.736 ;
    END
  END q[120]
  PIN q[121]
    DIRECTION OUTPUT ;
    USE SIGNAL ;
    PORT
      LAYER M4 ;
        RECT  32.316 53.808 32.4 53.832 ;
    END
  END q[121]
  PIN q[122]
    DIRECTION OUTPUT ;
    USE SIGNAL ;
    PORT
      LAYER M4 ;
        RECT  32.316 53.904 32.4 53.928 ;
    END
  END q[122]
  PIN q[123]
    DIRECTION OUTPUT ;
    USE SIGNAL ;
    PORT
      LAYER M4 ;
        RECT  32.316 54 32.4 54.024 ;
    END
  END q[123]
  PIN q[124]
    DIRECTION OUTPUT ;
    USE SIGNAL ;
    PORT
      LAYER M4 ;
        RECT  32.316 54.096 32.4 54.12 ;
    END
  END q[124]
  PIN q[125]
    DIRECTION OUTPUT ;
    USE SIGNAL ;
    PORT
      LAYER M4 ;
        RECT  32.316 54.192 32.4 54.216 ;
    END
  END q[125]
  PIN q[126]
    DIRECTION OUTPUT ;
    USE SIGNAL ;
    PORT
      LAYER M4 ;
        RECT  32.316 54.288 32.4 54.312 ;
    END
  END q[126]
  PIN q[127]
    DIRECTION OUTPUT ;
    USE SIGNAL ;
    PORT
      LAYER M4 ;
        RECT  32.316 54.384 32.4 54.408 ;
    END
  END q[127]
  PIN q[128]
    DIRECTION OUTPUT ;
    USE SIGNAL ;
    PORT
      LAYER M4 ;
        RECT  32.316 45.264 32.4 45.288 ;
    END
  END q[128]
  PIN q[129]
    DIRECTION OUTPUT ;
    USE SIGNAL ;
    PORT
      LAYER M4 ;
        RECT  32.316 45.36 32.4 45.384 ;
    END
  END q[129]
  PIN q[12]
    DIRECTION OUTPUT ;
    USE SIGNAL ;
    PORT
      LAYER M4 ;
        RECT  32.316 21.072 32.4 21.096 ;
    END
  END q[12]
  PIN q[130]
    DIRECTION OUTPUT ;
    USE SIGNAL ;
    PORT
      LAYER M4 ;
        RECT  32.316 45.456 32.4 45.48 ;
    END
  END q[130]
  PIN q[131]
    DIRECTION OUTPUT ;
    USE SIGNAL ;
    PORT
      LAYER M4 ;
        RECT  32.316 45.552 32.4 45.576 ;
    END
  END q[131]
  PIN q[132]
    DIRECTION OUTPUT ;
    USE SIGNAL ;
    PORT
      LAYER M4 ;
        RECT  32.316 45.648 32.4 45.672 ;
    END
  END q[132]
  PIN q[133]
    DIRECTION OUTPUT ;
    USE SIGNAL ;
    PORT
      LAYER M4 ;
        RECT  32.316 45.744 32.4 45.768 ;
    END
  END q[133]
  PIN q[134]
    DIRECTION OUTPUT ;
    USE SIGNAL ;
    PORT
      LAYER M4 ;
        RECT  32.316 45.84 32.4 45.864 ;
    END
  END q[134]
  PIN q[135]
    DIRECTION OUTPUT ;
    USE SIGNAL ;
    PORT
      LAYER M4 ;
        RECT  32.316 45.936 32.4 45.96 ;
    END
  END q[135]
  PIN q[136]
    DIRECTION OUTPUT ;
    USE SIGNAL ;
    PORT
      LAYER M4 ;
        RECT  32.316 46.032 32.4 46.056 ;
    END
  END q[136]
  PIN q[137]
    DIRECTION OUTPUT ;
    USE SIGNAL ;
    PORT
      LAYER M4 ;
        RECT  32.316 46.128 32.4 46.152 ;
    END
  END q[137]
  PIN q[138]
    DIRECTION OUTPUT ;
    USE SIGNAL ;
    PORT
      LAYER M4 ;
        RECT  32.316 46.224 32.4 46.248 ;
    END
  END q[138]
  PIN q[139]
    DIRECTION OUTPUT ;
    USE SIGNAL ;
    PORT
      LAYER M4 ;
        RECT  32.316 46.32 32.4 46.344 ;
    END
  END q[139]
  PIN q[13]
    DIRECTION OUTPUT ;
    USE SIGNAL ;
    PORT
      LAYER M4 ;
        RECT  32.316 21.168 32.4 21.192 ;
    END
  END q[13]
  PIN q[140]
    DIRECTION OUTPUT ;
    USE SIGNAL ;
    PORT
      LAYER M4 ;
        RECT  32.316 46.416 32.4 46.44 ;
    END
  END q[140]
  PIN q[141]
    DIRECTION OUTPUT ;
    USE SIGNAL ;
    PORT
      LAYER M4 ;
        RECT  32.316 46.512 32.4 46.536 ;
    END
  END q[141]
  PIN q[142]
    DIRECTION OUTPUT ;
    USE SIGNAL ;
    PORT
      LAYER M4 ;
        RECT  32.316 46.608 32.4 46.632 ;
    END
  END q[142]
  PIN q[143]
    DIRECTION OUTPUT ;
    USE SIGNAL ;
    PORT
      LAYER M4 ;
        RECT  32.316 46.704 32.4 46.728 ;
    END
  END q[143]
  PIN q[144]
    DIRECTION OUTPUT ;
    USE SIGNAL ;
    PORT
      LAYER M4 ;
        RECT  32.316 46.8 32.4 46.824 ;
    END
  END q[144]
  PIN q[145]
    DIRECTION OUTPUT ;
    USE SIGNAL ;
    PORT
      LAYER M4 ;
        RECT  32.316 46.896 32.4 46.92 ;
    END
  END q[145]
  PIN q[146]
    DIRECTION OUTPUT ;
    USE SIGNAL ;
    PORT
      LAYER M4 ;
        RECT  32.316 46.992 32.4 47.016 ;
    END
  END q[146]
  PIN q[147]
    DIRECTION OUTPUT ;
    USE SIGNAL ;
    PORT
      LAYER M4 ;
        RECT  32.316 47.088 32.4 47.112 ;
    END
  END q[147]
  PIN q[148]
    DIRECTION OUTPUT ;
    USE SIGNAL ;
    PORT
      LAYER M4 ;
        RECT  32.316 47.184 32.4 47.208 ;
    END
  END q[148]
  PIN q[149]
    DIRECTION OUTPUT ;
    USE SIGNAL ;
    PORT
      LAYER M4 ;
        RECT  32.316 47.28 32.4 47.304 ;
    END
  END q[149]
  PIN q[14]
    DIRECTION OUTPUT ;
    USE SIGNAL ;
    PORT
      LAYER M4 ;
        RECT  32.316 21.264 32.4 21.288 ;
    END
  END q[14]
  PIN q[150]
    DIRECTION OUTPUT ;
    USE SIGNAL ;
    PORT
      LAYER M4 ;
        RECT  32.316 47.376 32.4 47.4 ;
    END
  END q[150]
  PIN q[151]
    DIRECTION OUTPUT ;
    USE SIGNAL ;
    PORT
      LAYER M4 ;
        RECT  32.316 47.472 32.4 47.496 ;
    END
  END q[151]
  PIN q[152]
    DIRECTION OUTPUT ;
    USE SIGNAL ;
    PORT
      LAYER M4 ;
        RECT  32.316 47.568 32.4 47.592 ;
    END
  END q[152]
  PIN q[153]
    DIRECTION OUTPUT ;
    USE SIGNAL ;
    PORT
      LAYER M4 ;
        RECT  32.316 47.664 32.4 47.688 ;
    END
  END q[153]
  PIN q[154]
    DIRECTION OUTPUT ;
    USE SIGNAL ;
    PORT
      LAYER M4 ;
        RECT  32.316 47.76 32.4 47.784 ;
    END
  END q[154]
  PIN q[155]
    DIRECTION OUTPUT ;
    USE SIGNAL ;
    PORT
      LAYER M4 ;
        RECT  32.316 47.856 32.4 47.88 ;
    END
  END q[155]
  PIN q[156]
    DIRECTION OUTPUT ;
    USE SIGNAL ;
    PORT
      LAYER M4 ;
        RECT  32.316 47.952 32.4 47.976 ;
    END
  END q[156]
  PIN q[157]
    DIRECTION OUTPUT ;
    USE SIGNAL ;
    PORT
      LAYER M4 ;
        RECT  32.316 48.048 32.4 48.072 ;
    END
  END q[157]
  PIN q[158]
    DIRECTION OUTPUT ;
    USE SIGNAL ;
    PORT
      LAYER M4 ;
        RECT  32.316 48.144 32.4 48.168 ;
    END
  END q[158]
  PIN q[159]
    DIRECTION OUTPUT ;
    USE SIGNAL ;
    PORT
      LAYER M4 ;
        RECT  32.316 48.24 32.4 48.264 ;
    END
  END q[159]
  PIN q[15]
    DIRECTION OUTPUT ;
    USE SIGNAL ;
    PORT
      LAYER M4 ;
        RECT  32.316 21.36 32.4 21.384 ;
    END
  END q[15]
  PIN q[160]
    DIRECTION OUTPUT ;
    USE SIGNAL ;
    PORT
      LAYER M4 ;
        RECT  32.316 54.48 32.4 54.504 ;
    END
  END q[160]
  PIN q[161]
    DIRECTION OUTPUT ;
    USE SIGNAL ;
    PORT
      LAYER M4 ;
        RECT  32.316 54.576 32.4 54.6 ;
    END
  END q[161]
  PIN q[162]
    DIRECTION OUTPUT ;
    USE SIGNAL ;
    PORT
      LAYER M4 ;
        RECT  32.316 54.672 32.4 54.696 ;
    END
  END q[162]
  PIN q[163]
    DIRECTION OUTPUT ;
    USE SIGNAL ;
    PORT
      LAYER M4 ;
        RECT  32.316 54.768 32.4 54.792 ;
    END
  END q[163]
  PIN q[164]
    DIRECTION OUTPUT ;
    USE SIGNAL ;
    PORT
      LAYER M4 ;
        RECT  32.316 54.864 32.4 54.888 ;
    END
  END q[164]
  PIN q[165]
    DIRECTION OUTPUT ;
    USE SIGNAL ;
    PORT
      LAYER M4 ;
        RECT  32.316 54.96 32.4 54.984 ;
    END
  END q[165]
  PIN q[166]
    DIRECTION OUTPUT ;
    USE SIGNAL ;
    PORT
      LAYER M4 ;
        RECT  32.316 55.056 32.4 55.08 ;
    END
  END q[166]
  PIN q[167]
    DIRECTION OUTPUT ;
    USE SIGNAL ;
    PORT
      LAYER M4 ;
        RECT  32.316 55.152 32.4 55.176 ;
    END
  END q[167]
  PIN q[168]
    DIRECTION OUTPUT ;
    USE SIGNAL ;
    PORT
      LAYER M4 ;
        RECT  32.316 55.248 32.4 55.272 ;
    END
  END q[168]
  PIN q[169]
    DIRECTION OUTPUT ;
    USE SIGNAL ;
    PORT
      LAYER M4 ;
        RECT  32.316 55.344 32.4 55.368 ;
    END
  END q[169]
  PIN q[16]
    DIRECTION OUTPUT ;
    USE SIGNAL ;
    PORT
      LAYER M4 ;
        RECT  32.316 21.456 32.4 21.48 ;
    END
  END q[16]
  PIN q[170]
    DIRECTION OUTPUT ;
    USE SIGNAL ;
    PORT
      LAYER M4 ;
        RECT  32.316 55.44 32.4 55.464 ;
    END
  END q[170]
  PIN q[171]
    DIRECTION OUTPUT ;
    USE SIGNAL ;
    PORT
      LAYER M4 ;
        RECT  32.316 55.536 32.4 55.56 ;
    END
  END q[171]
  PIN q[172]
    DIRECTION OUTPUT ;
    USE SIGNAL ;
    PORT
      LAYER M4 ;
        RECT  32.316 55.632 32.4 55.656 ;
    END
  END q[172]
  PIN q[173]
    DIRECTION OUTPUT ;
    USE SIGNAL ;
    PORT
      LAYER M4 ;
        RECT  32.316 55.728 32.4 55.752 ;
    END
  END q[173]
  PIN q[174]
    DIRECTION OUTPUT ;
    USE SIGNAL ;
    PORT
      LAYER M4 ;
        RECT  32.316 55.824 32.4 55.848 ;
    END
  END q[174]
  PIN q[175]
    DIRECTION OUTPUT ;
    USE SIGNAL ;
    PORT
      LAYER M4 ;
        RECT  32.316 55.92 32.4 55.944 ;
    END
  END q[175]
  PIN q[176]
    DIRECTION OUTPUT ;
    USE SIGNAL ;
    PORT
      LAYER M4 ;
        RECT  32.316 56.016 32.4 56.04 ;
    END
  END q[176]
  PIN q[177]
    DIRECTION OUTPUT ;
    USE SIGNAL ;
    PORT
      LAYER M4 ;
        RECT  32.316 56.112 32.4 56.136 ;
    END
  END q[177]
  PIN q[178]
    DIRECTION OUTPUT ;
    USE SIGNAL ;
    PORT
      LAYER M4 ;
        RECT  32.316 56.208 32.4 56.232 ;
    END
  END q[178]
  PIN q[179]
    DIRECTION OUTPUT ;
    USE SIGNAL ;
    PORT
      LAYER M4 ;
        RECT  32.316 56.304 32.4 56.328 ;
    END
  END q[179]
  PIN q[17]
    DIRECTION OUTPUT ;
    USE SIGNAL ;
    PORT
      LAYER M4 ;
        RECT  32.316 21.552 32.4 21.576 ;
    END
  END q[17]
  PIN q[180]
    DIRECTION OUTPUT ;
    USE SIGNAL ;
    PORT
      LAYER M4 ;
        RECT  32.316 56.4 32.4 56.424 ;
    END
  END q[180]
  PIN q[181]
    DIRECTION OUTPUT ;
    USE SIGNAL ;
    PORT
      LAYER M4 ;
        RECT  32.316 56.496 32.4 56.52 ;
    END
  END q[181]
  PIN q[182]
    DIRECTION OUTPUT ;
    USE SIGNAL ;
    PORT
      LAYER M4 ;
        RECT  32.316 56.592 32.4 56.616 ;
    END
  END q[182]
  PIN q[183]
    DIRECTION OUTPUT ;
    USE SIGNAL ;
    PORT
      LAYER M4 ;
        RECT  32.316 56.688 32.4 56.712 ;
    END
  END q[183]
  PIN q[184]
    DIRECTION OUTPUT ;
    USE SIGNAL ;
    PORT
      LAYER M4 ;
        RECT  32.316 56.784 32.4 56.808 ;
    END
  END q[184]
  PIN q[185]
    DIRECTION OUTPUT ;
    USE SIGNAL ;
    PORT
      LAYER M4 ;
        RECT  32.316 56.88 32.4 56.904 ;
    END
  END q[185]
  PIN q[186]
    DIRECTION OUTPUT ;
    USE SIGNAL ;
    PORT
      LAYER M4 ;
        RECT  32.316 56.976 32.4 57 ;
    END
  END q[186]
  PIN q[187]
    DIRECTION OUTPUT ;
    USE SIGNAL ;
    PORT
      LAYER M4 ;
        RECT  32.316 57.072 32.4 57.096 ;
    END
  END q[187]
  PIN q[188]
    DIRECTION OUTPUT ;
    USE SIGNAL ;
    PORT
      LAYER M4 ;
        RECT  32.316 57.168 32.4 57.192 ;
    END
  END q[188]
  PIN q[189]
    DIRECTION OUTPUT ;
    USE SIGNAL ;
    PORT
      LAYER M4 ;
        RECT  32.316 57.264 32.4 57.288 ;
    END
  END q[189]
  PIN q[18]
    DIRECTION OUTPUT ;
    USE SIGNAL ;
    PORT
      LAYER M4 ;
        RECT  32.316 21.648 32.4 21.672 ;
    END
  END q[18]
  PIN q[190]
    DIRECTION OUTPUT ;
    USE SIGNAL ;
    PORT
      LAYER M4 ;
        RECT  32.316 57.36 32.4 57.384 ;
    END
  END q[190]
  PIN q[191]
    DIRECTION OUTPUT ;
    USE SIGNAL ;
    PORT
      LAYER M4 ;
        RECT  32.316 57.456 32.4 57.48 ;
    END
  END q[191]
  PIN q[192]
    DIRECTION OUTPUT ;
    USE SIGNAL ;
    PORT
      LAYER M4 ;
        RECT  32.316 39.12 32.4 39.144 ;
    END
  END q[192]
  PIN q[193]
    DIRECTION OUTPUT ;
    USE SIGNAL ;
    PORT
      LAYER M4 ;
        RECT  32.316 39.216 32.4 39.24 ;
    END
  END q[193]
  PIN q[194]
    DIRECTION OUTPUT ;
    USE SIGNAL ;
    PORT
      LAYER M4 ;
        RECT  32.316 39.312 32.4 39.336 ;
    END
  END q[194]
  PIN q[195]
    DIRECTION OUTPUT ;
    USE SIGNAL ;
    PORT
      LAYER M4 ;
        RECT  32.316 39.408 32.4 39.432 ;
    END
  END q[195]
  PIN q[196]
    DIRECTION OUTPUT ;
    USE SIGNAL ;
    PORT
      LAYER M4 ;
        RECT  32.316 39.504 32.4 39.528 ;
    END
  END q[196]
  PIN q[197]
    DIRECTION OUTPUT ;
    USE SIGNAL ;
    PORT
      LAYER M4 ;
        RECT  32.316 39.6 32.4 39.624 ;
    END
  END q[197]
  PIN q[198]
    DIRECTION OUTPUT ;
    USE SIGNAL ;
    PORT
      LAYER M4 ;
        RECT  32.316 39.696 32.4 39.72 ;
    END
  END q[198]
  PIN q[199]
    DIRECTION OUTPUT ;
    USE SIGNAL ;
    PORT
      LAYER M4 ;
        RECT  32.316 39.792 32.4 39.816 ;
    END
  END q[199]
  PIN q[19]
    DIRECTION OUTPUT ;
    USE SIGNAL ;
    PORT
      LAYER M4 ;
        RECT  32.316 21.744 32.4 21.768 ;
    END
  END q[19]
  PIN q[1]
    DIRECTION OUTPUT ;
    USE SIGNAL ;
    PORT
      LAYER M4 ;
        RECT  32.316 20.016 32.4 20.04 ;
    END
  END q[1]
  PIN q[200]
    DIRECTION OUTPUT ;
    USE SIGNAL ;
    PORT
      LAYER M4 ;
        RECT  32.316 39.888 32.4 39.912 ;
    END
  END q[200]
  PIN q[201]
    DIRECTION OUTPUT ;
    USE SIGNAL ;
    PORT
      LAYER M4 ;
        RECT  32.316 39.984 32.4 40.008 ;
    END
  END q[201]
  PIN q[202]
    DIRECTION OUTPUT ;
    USE SIGNAL ;
    PORT
      LAYER M4 ;
        RECT  32.316 40.08 32.4 40.104 ;
    END
  END q[202]
  PIN q[203]
    DIRECTION OUTPUT ;
    USE SIGNAL ;
    PORT
      LAYER M4 ;
        RECT  32.316 40.176 32.4 40.2 ;
    END
  END q[203]
  PIN q[204]
    DIRECTION OUTPUT ;
    USE SIGNAL ;
    PORT
      LAYER M4 ;
        RECT  32.316 40.272 32.4 40.296 ;
    END
  END q[204]
  PIN q[205]
    DIRECTION OUTPUT ;
    USE SIGNAL ;
    PORT
      LAYER M4 ;
        RECT  32.316 40.368 32.4 40.392 ;
    END
  END q[205]
  PIN q[206]
    DIRECTION OUTPUT ;
    USE SIGNAL ;
    PORT
      LAYER M4 ;
        RECT  32.316 40.464 32.4 40.488 ;
    END
  END q[206]
  PIN q[207]
    DIRECTION OUTPUT ;
    USE SIGNAL ;
    PORT
      LAYER M4 ;
        RECT  32.316 40.56 32.4 40.584 ;
    END
  END q[207]
  PIN q[208]
    DIRECTION OUTPUT ;
    USE SIGNAL ;
    PORT
      LAYER M4 ;
        RECT  32.316 40.656 32.4 40.68 ;
    END
  END q[208]
  PIN q[209]
    DIRECTION OUTPUT ;
    USE SIGNAL ;
    PORT
      LAYER M4 ;
        RECT  32.316 40.752 32.4 40.776 ;
    END
  END q[209]
  PIN q[20]
    DIRECTION OUTPUT ;
    USE SIGNAL ;
    PORT
      LAYER M4 ;
        RECT  32.316 21.84 32.4 21.864 ;
    END
  END q[20]
  PIN q[210]
    DIRECTION OUTPUT ;
    USE SIGNAL ;
    PORT
      LAYER M4 ;
        RECT  32.316 40.848 32.4 40.872 ;
    END
  END q[210]
  PIN q[211]
    DIRECTION OUTPUT ;
    USE SIGNAL ;
    PORT
      LAYER M4 ;
        RECT  32.316 40.944 32.4 40.968 ;
    END
  END q[211]
  PIN q[212]
    DIRECTION OUTPUT ;
    USE SIGNAL ;
    PORT
      LAYER M4 ;
        RECT  32.316 41.04 32.4 41.064 ;
    END
  END q[212]
  PIN q[213]
    DIRECTION OUTPUT ;
    USE SIGNAL ;
    PORT
      LAYER M4 ;
        RECT  32.316 41.136 32.4 41.16 ;
    END
  END q[213]
  PIN q[214]
    DIRECTION OUTPUT ;
    USE SIGNAL ;
    PORT
      LAYER M4 ;
        RECT  32.316 41.232 32.4 41.256 ;
    END
  END q[214]
  PIN q[215]
    DIRECTION OUTPUT ;
    USE SIGNAL ;
    PORT
      LAYER M4 ;
        RECT  32.316 41.328 32.4 41.352 ;
    END
  END q[215]
  PIN q[216]
    DIRECTION OUTPUT ;
    USE SIGNAL ;
    PORT
      LAYER M4 ;
        RECT  32.316 41.424 32.4 41.448 ;
    END
  END q[216]
  PIN q[217]
    DIRECTION OUTPUT ;
    USE SIGNAL ;
    PORT
      LAYER M4 ;
        RECT  32.316 41.52 32.4 41.544 ;
    END
  END q[217]
  PIN q[218]
    DIRECTION OUTPUT ;
    USE SIGNAL ;
    PORT
      LAYER M4 ;
        RECT  32.316 41.616 32.4 41.64 ;
    END
  END q[218]
  PIN q[219]
    DIRECTION OUTPUT ;
    USE SIGNAL ;
    PORT
      LAYER M4 ;
        RECT  32.316 41.712 32.4 41.736 ;
    END
  END q[219]
  PIN q[21]
    DIRECTION OUTPUT ;
    USE SIGNAL ;
    PORT
      LAYER M4 ;
        RECT  32.316 21.936 32.4 21.96 ;
    END
  END q[21]
  PIN q[220]
    DIRECTION OUTPUT ;
    USE SIGNAL ;
    PORT
      LAYER M4 ;
        RECT  32.316 41.808 32.4 41.832 ;
    END
  END q[220]
  PIN q[221]
    DIRECTION OUTPUT ;
    USE SIGNAL ;
    PORT
      LAYER M4 ;
        RECT  32.316 41.904 32.4 41.928 ;
    END
  END q[221]
  PIN q[222]
    DIRECTION OUTPUT ;
    USE SIGNAL ;
    PORT
      LAYER M4 ;
        RECT  32.316 42 32.4 42.024 ;
    END
  END q[222]
  PIN q[223]
    DIRECTION OUTPUT ;
    USE SIGNAL ;
    PORT
      LAYER M4 ;
        RECT  32.316 42.096 32.4 42.12 ;
    END
  END q[223]
  PIN q[224]
    DIRECTION OUTPUT ;
    USE SIGNAL ;
    PORT
      LAYER M4 ;
        RECT  32.316 35.28 32.4 35.304 ;
    END
  END q[224]
  PIN q[225]
    DIRECTION OUTPUT ;
    USE SIGNAL ;
    PORT
      LAYER M4 ;
        RECT  32.316 35.376 32.4 35.4 ;
    END
  END q[225]
  PIN q[226]
    DIRECTION OUTPUT ;
    USE SIGNAL ;
    PORT
      LAYER M4 ;
        RECT  32.316 35.472 32.4 35.496 ;
    END
  END q[226]
  PIN q[227]
    DIRECTION OUTPUT ;
    USE SIGNAL ;
    PORT
      LAYER M4 ;
        RECT  32.316 35.568 32.4 35.592 ;
    END
  END q[227]
  PIN q[228]
    DIRECTION OUTPUT ;
    USE SIGNAL ;
    PORT
      LAYER M4 ;
        RECT  32.316 35.664 32.4 35.688 ;
    END
  END q[228]
  PIN q[229]
    DIRECTION OUTPUT ;
    USE SIGNAL ;
    PORT
      LAYER M4 ;
        RECT  32.316 35.76 32.4 35.784 ;
    END
  END q[229]
  PIN q[22]
    DIRECTION OUTPUT ;
    USE SIGNAL ;
    PORT
      LAYER M4 ;
        RECT  32.316 22.032 32.4 22.056 ;
    END
  END q[22]
  PIN q[230]
    DIRECTION OUTPUT ;
    USE SIGNAL ;
    PORT
      LAYER M4 ;
        RECT  32.316 35.856 32.4 35.88 ;
    END
  END q[230]
  PIN q[231]
    DIRECTION OUTPUT ;
    USE SIGNAL ;
    PORT
      LAYER M4 ;
        RECT  32.316 35.952 32.4 35.976 ;
    END
  END q[231]
  PIN q[232]
    DIRECTION OUTPUT ;
    USE SIGNAL ;
    PORT
      LAYER M4 ;
        RECT  32.316 36.048 32.4 36.072 ;
    END
  END q[232]
  PIN q[233]
    DIRECTION OUTPUT ;
    USE SIGNAL ;
    PORT
      LAYER M4 ;
        RECT  32.316 36.144 32.4 36.168 ;
    END
  END q[233]
  PIN q[234]
    DIRECTION OUTPUT ;
    USE SIGNAL ;
    PORT
      LAYER M4 ;
        RECT  32.316 36.24 32.4 36.264 ;
    END
  END q[234]
  PIN q[235]
    DIRECTION OUTPUT ;
    USE SIGNAL ;
    PORT
      LAYER M4 ;
        RECT  32.316 36.336 32.4 36.36 ;
    END
  END q[235]
  PIN q[236]
    DIRECTION OUTPUT ;
    USE SIGNAL ;
    PORT
      LAYER M4 ;
        RECT  32.316 36.432 32.4 36.456 ;
    END
  END q[236]
  PIN q[237]
    DIRECTION OUTPUT ;
    USE SIGNAL ;
    PORT
      LAYER M4 ;
        RECT  32.316 36.528 32.4 36.552 ;
    END
  END q[237]
  PIN q[238]
    DIRECTION OUTPUT ;
    USE SIGNAL ;
    PORT
      LAYER M4 ;
        RECT  32.316 36.624 32.4 36.648 ;
    END
  END q[238]
  PIN q[239]
    DIRECTION OUTPUT ;
    USE SIGNAL ;
    PORT
      LAYER M4 ;
        RECT  32.316 36.72 32.4 36.744 ;
    END
  END q[239]
  PIN q[23]
    DIRECTION OUTPUT ;
    USE SIGNAL ;
    PORT
      LAYER M4 ;
        RECT  32.316 22.128 32.4 22.152 ;
    END
  END q[23]
  PIN q[240]
    DIRECTION OUTPUT ;
    USE SIGNAL ;
    PORT
      LAYER M4 ;
        RECT  32.316 36.816 32.4 36.84 ;
    END
  END q[240]
  PIN q[241]
    DIRECTION OUTPUT ;
    USE SIGNAL ;
    PORT
      LAYER M4 ;
        RECT  32.316 36.912 32.4 36.936 ;
    END
  END q[241]
  PIN q[242]
    DIRECTION OUTPUT ;
    USE SIGNAL ;
    PORT
      LAYER M4 ;
        RECT  32.316 37.008 32.4 37.032 ;
    END
  END q[242]
  PIN q[243]
    DIRECTION OUTPUT ;
    USE SIGNAL ;
    PORT
      LAYER M4 ;
        RECT  32.316 37.104 32.4 37.128 ;
    END
  END q[243]
  PIN q[244]
    DIRECTION OUTPUT ;
    USE SIGNAL ;
    PORT
      LAYER M4 ;
        RECT  32.316 37.2 32.4 37.224 ;
    END
  END q[244]
  PIN q[245]
    DIRECTION OUTPUT ;
    USE SIGNAL ;
    PORT
      LAYER M4 ;
        RECT  32.316 37.296 32.4 37.32 ;
    END
  END q[245]
  PIN q[246]
    DIRECTION OUTPUT ;
    USE SIGNAL ;
    PORT
      LAYER M4 ;
        RECT  32.316 37.392 32.4 37.416 ;
    END
  END q[246]
  PIN q[247]
    DIRECTION OUTPUT ;
    USE SIGNAL ;
    PORT
      LAYER M4 ;
        RECT  32.316 37.488 32.4 37.512 ;
    END
  END q[247]
  PIN q[248]
    DIRECTION OUTPUT ;
    USE SIGNAL ;
    PORT
      LAYER M4 ;
        RECT  32.316 37.584 32.4 37.608 ;
    END
  END q[248]
  PIN q[249]
    DIRECTION OUTPUT ;
    USE SIGNAL ;
    PORT
      LAYER M4 ;
        RECT  32.316 37.68 32.4 37.704 ;
    END
  END q[249]
  PIN q[24]
    DIRECTION OUTPUT ;
    USE SIGNAL ;
    PORT
      LAYER M4 ;
        RECT  32.316 22.224 32.4 22.248 ;
    END
  END q[24]
  PIN q[250]
    DIRECTION OUTPUT ;
    USE SIGNAL ;
    PORT
      LAYER M4 ;
        RECT  32.316 37.776 32.4 37.8 ;
    END
  END q[250]
  PIN q[251]
    DIRECTION OUTPUT ;
    USE SIGNAL ;
    PORT
      LAYER M4 ;
        RECT  32.316 37.872 32.4 37.896 ;
    END
  END q[251]
  PIN q[252]
    DIRECTION OUTPUT ;
    USE SIGNAL ;
    PORT
      LAYER M4 ;
        RECT  32.316 37.968 32.4 37.992 ;
    END
  END q[252]
  PIN q[253]
    DIRECTION OUTPUT ;
    USE SIGNAL ;
    PORT
      LAYER M4 ;
        RECT  32.316 38.064 32.4 38.088 ;
    END
  END q[253]
  PIN q[254]
    DIRECTION OUTPUT ;
    USE SIGNAL ;
    PORT
      LAYER M4 ;
        RECT  32.316 38.16 32.4 38.184 ;
    END
  END q[254]
  PIN q[255]
    DIRECTION OUTPUT ;
    USE SIGNAL ;
    PORT
      LAYER M4 ;
        RECT  32.316 38.256 32.4 38.28 ;
    END
  END q[255]
  PIN q[256]
    DIRECTION OUTPUT ;
    USE SIGNAL ;
    PORT
      LAYER M4 ;
        RECT  32.316 22.992 32.4 23.016 ;
    END
  END q[256]
  PIN q[257]
    DIRECTION OUTPUT ;
    USE SIGNAL ;
    PORT
      LAYER M4 ;
        RECT  32.316 23.088 32.4 23.112 ;
    END
  END q[257]
  PIN q[258]
    DIRECTION OUTPUT ;
    USE SIGNAL ;
    PORT
      LAYER M4 ;
        RECT  32.316 23.184 32.4 23.208 ;
    END
  END q[258]
  PIN q[259]
    DIRECTION OUTPUT ;
    USE SIGNAL ;
    PORT
      LAYER M4 ;
        RECT  32.316 23.28 32.4 23.304 ;
    END
  END q[259]
  PIN q[25]
    DIRECTION OUTPUT ;
    USE SIGNAL ;
    PORT
      LAYER M4 ;
        RECT  32.316 22.32 32.4 22.344 ;
    END
  END q[25]
  PIN q[260]
    DIRECTION OUTPUT ;
    USE SIGNAL ;
    PORT
      LAYER M4 ;
        RECT  32.316 23.376 32.4 23.4 ;
    END
  END q[260]
  PIN q[261]
    DIRECTION OUTPUT ;
    USE SIGNAL ;
    PORT
      LAYER M4 ;
        RECT  32.316 23.472 32.4 23.496 ;
    END
  END q[261]
  PIN q[262]
    DIRECTION OUTPUT ;
    USE SIGNAL ;
    PORT
      LAYER M4 ;
        RECT  32.316 23.568 32.4 23.592 ;
    END
  END q[262]
  PIN q[263]
    DIRECTION OUTPUT ;
    USE SIGNAL ;
    PORT
      LAYER M4 ;
        RECT  32.316 23.664 32.4 23.688 ;
    END
  END q[263]
  PIN q[264]
    DIRECTION OUTPUT ;
    USE SIGNAL ;
    PORT
      LAYER M4 ;
        RECT  32.316 23.76 32.4 23.784 ;
    END
  END q[264]
  PIN q[265]
    DIRECTION OUTPUT ;
    USE SIGNAL ;
    PORT
      LAYER M4 ;
        RECT  32.316 23.856 32.4 23.88 ;
    END
  END q[265]
  PIN q[266]
    DIRECTION OUTPUT ;
    USE SIGNAL ;
    PORT
      LAYER M4 ;
        RECT  32.316 23.952 32.4 23.976 ;
    END
  END q[266]
  PIN q[267]
    DIRECTION OUTPUT ;
    USE SIGNAL ;
    PORT
      LAYER M4 ;
        RECT  32.316 24.048 32.4 24.072 ;
    END
  END q[267]
  PIN q[268]
    DIRECTION OUTPUT ;
    USE SIGNAL ;
    PORT
      LAYER M4 ;
        RECT  32.316 24.144 32.4 24.168 ;
    END
  END q[268]
  PIN q[269]
    DIRECTION OUTPUT ;
    USE SIGNAL ;
    PORT
      LAYER M4 ;
        RECT  32.316 24.24 32.4 24.264 ;
    END
  END q[269]
  PIN q[26]
    DIRECTION OUTPUT ;
    USE SIGNAL ;
    PORT
      LAYER M4 ;
        RECT  32.316 22.416 32.4 22.44 ;
    END
  END q[26]
  PIN q[270]
    DIRECTION OUTPUT ;
    USE SIGNAL ;
    PORT
      LAYER M4 ;
        RECT  32.316 24.336 32.4 24.36 ;
    END
  END q[270]
  PIN q[271]
    DIRECTION OUTPUT ;
    USE SIGNAL ;
    PORT
      LAYER M4 ;
        RECT  32.316 24.432 32.4 24.456 ;
    END
  END q[271]
  PIN q[272]
    DIRECTION OUTPUT ;
    USE SIGNAL ;
    PORT
      LAYER M4 ;
        RECT  32.316 24.528 32.4 24.552 ;
    END
  END q[272]
  PIN q[273]
    DIRECTION OUTPUT ;
    USE SIGNAL ;
    PORT
      LAYER M4 ;
        RECT  32.316 24.624 32.4 24.648 ;
    END
  END q[273]
  PIN q[274]
    DIRECTION OUTPUT ;
    USE SIGNAL ;
    PORT
      LAYER M4 ;
        RECT  32.316 24.72 32.4 24.744 ;
    END
  END q[274]
  PIN q[275]
    DIRECTION OUTPUT ;
    USE SIGNAL ;
    PORT
      LAYER M4 ;
        RECT  32.316 24.816 32.4 24.84 ;
    END
  END q[275]
  PIN q[276]
    DIRECTION OUTPUT ;
    USE SIGNAL ;
    PORT
      LAYER M4 ;
        RECT  32.316 24.912 32.4 24.936 ;
    END
  END q[276]
  PIN q[277]
    DIRECTION OUTPUT ;
    USE SIGNAL ;
    PORT
      LAYER M4 ;
        RECT  32.316 25.008 32.4 25.032 ;
    END
  END q[277]
  PIN q[278]
    DIRECTION OUTPUT ;
    USE SIGNAL ;
    PORT
      LAYER M4 ;
        RECT  32.316 25.104 32.4 25.128 ;
    END
  END q[278]
  PIN q[279]
    DIRECTION OUTPUT ;
    USE SIGNAL ;
    PORT
      LAYER M4 ;
        RECT  32.316 25.2 32.4 25.224 ;
    END
  END q[279]
  PIN q[27]
    DIRECTION OUTPUT ;
    USE SIGNAL ;
    PORT
      LAYER M4 ;
        RECT  32.316 22.512 32.4 22.536 ;
    END
  END q[27]
  PIN q[280]
    DIRECTION OUTPUT ;
    USE SIGNAL ;
    PORT
      LAYER M4 ;
        RECT  32.316 25.296 32.4 25.32 ;
    END
  END q[280]
  PIN q[281]
    DIRECTION OUTPUT ;
    USE SIGNAL ;
    PORT
      LAYER M4 ;
        RECT  32.316 25.392 32.4 25.416 ;
    END
  END q[281]
  PIN q[282]
    DIRECTION OUTPUT ;
    USE SIGNAL ;
    PORT
      LAYER M4 ;
        RECT  32.316 25.488 32.4 25.512 ;
    END
  END q[282]
  PIN q[283]
    DIRECTION OUTPUT ;
    USE SIGNAL ;
    PORT
      LAYER M4 ;
        RECT  32.316 25.584 32.4 25.608 ;
    END
  END q[283]
  PIN q[284]
    DIRECTION OUTPUT ;
    USE SIGNAL ;
    PORT
      LAYER M4 ;
        RECT  32.316 25.68 32.4 25.704 ;
    END
  END q[284]
  PIN q[285]
    DIRECTION OUTPUT ;
    USE SIGNAL ;
    PORT
      LAYER M4 ;
        RECT  32.316 25.776 32.4 25.8 ;
    END
  END q[285]
  PIN q[286]
    DIRECTION OUTPUT ;
    USE SIGNAL ;
    PORT
      LAYER M4 ;
        RECT  32.316 25.872 32.4 25.896 ;
    END
  END q[286]
  PIN q[287]
    DIRECTION OUTPUT ;
    USE SIGNAL ;
    PORT
      LAYER M4 ;
        RECT  32.316 25.968 32.4 25.992 ;
    END
  END q[287]
  PIN q[288]
    DIRECTION OUTPUT ;
    USE SIGNAL ;
    PORT
      LAYER M4 ;
        RECT  32.316 48.336 32.4 48.36 ;
    END
  END q[288]
  PIN q[289]
    DIRECTION OUTPUT ;
    USE SIGNAL ;
    PORT
      LAYER M4 ;
        RECT  32.316 48.432 32.4 48.456 ;
    END
  END q[289]
  PIN q[28]
    DIRECTION OUTPUT ;
    USE SIGNAL ;
    PORT
      LAYER M4 ;
        RECT  32.316 22.608 32.4 22.632 ;
    END
  END q[28]
  PIN q[290]
    DIRECTION OUTPUT ;
    USE SIGNAL ;
    PORT
      LAYER M4 ;
        RECT  32.316 48.528 32.4 48.552 ;
    END
  END q[290]
  PIN q[291]
    DIRECTION OUTPUT ;
    USE SIGNAL ;
    PORT
      LAYER M4 ;
        RECT  32.316 48.624 32.4 48.648 ;
    END
  END q[291]
  PIN q[292]
    DIRECTION OUTPUT ;
    USE SIGNAL ;
    PORT
      LAYER M4 ;
        RECT  32.316 48.72 32.4 48.744 ;
    END
  END q[292]
  PIN q[293]
    DIRECTION OUTPUT ;
    USE SIGNAL ;
    PORT
      LAYER M4 ;
        RECT  32.316 48.816 32.4 48.84 ;
    END
  END q[293]
  PIN q[294]
    DIRECTION OUTPUT ;
    USE SIGNAL ;
    PORT
      LAYER M4 ;
        RECT  32.316 48.912 32.4 48.936 ;
    END
  END q[294]
  PIN q[295]
    DIRECTION OUTPUT ;
    USE SIGNAL ;
    PORT
      LAYER M4 ;
        RECT  32.316 49.008 32.4 49.032 ;
    END
  END q[295]
  PIN q[296]
    DIRECTION OUTPUT ;
    USE SIGNAL ;
    PORT
      LAYER M4 ;
        RECT  32.316 49.104 32.4 49.128 ;
    END
  END q[296]
  PIN q[297]
    DIRECTION OUTPUT ;
    USE SIGNAL ;
    PORT
      LAYER M4 ;
        RECT  32.316 49.2 32.4 49.224 ;
    END
  END q[297]
  PIN q[298]
    DIRECTION OUTPUT ;
    USE SIGNAL ;
    PORT
      LAYER M4 ;
        RECT  32.316 49.296 32.4 49.32 ;
    END
  END q[298]
  PIN q[299]
    DIRECTION OUTPUT ;
    USE SIGNAL ;
    PORT
      LAYER M4 ;
        RECT  32.316 49.392 32.4 49.416 ;
    END
  END q[299]
  PIN q[29]
    DIRECTION OUTPUT ;
    USE SIGNAL ;
    PORT
      LAYER M4 ;
        RECT  32.316 22.704 32.4 22.728 ;
    END
  END q[29]
  PIN q[2]
    DIRECTION OUTPUT ;
    USE SIGNAL ;
    PORT
      LAYER M4 ;
        RECT  32.316 20.112 32.4 20.136 ;
    END
  END q[2]
  PIN q[300]
    DIRECTION OUTPUT ;
    USE SIGNAL ;
    PORT
      LAYER M4 ;
        RECT  32.316 49.488 32.4 49.512 ;
    END
  END q[300]
  PIN q[301]
    DIRECTION OUTPUT ;
    USE SIGNAL ;
    PORT
      LAYER M4 ;
        RECT  32.316 49.584 32.4 49.608 ;
    END
  END q[301]
  PIN q[302]
    DIRECTION OUTPUT ;
    USE SIGNAL ;
    PORT
      LAYER M4 ;
        RECT  32.316 49.68 32.4 49.704 ;
    END
  END q[302]
  PIN q[303]
    DIRECTION OUTPUT ;
    USE SIGNAL ;
    PORT
      LAYER M4 ;
        RECT  32.316 49.776 32.4 49.8 ;
    END
  END q[303]
  PIN q[304]
    DIRECTION OUTPUT ;
    USE SIGNAL ;
    PORT
      LAYER M4 ;
        RECT  32.316 49.872 32.4 49.896 ;
    END
  END q[304]
  PIN q[305]
    DIRECTION OUTPUT ;
    USE SIGNAL ;
    PORT
      LAYER M4 ;
        RECT  32.316 49.968 32.4 49.992 ;
    END
  END q[305]
  PIN q[306]
    DIRECTION OUTPUT ;
    USE SIGNAL ;
    PORT
      LAYER M4 ;
        RECT  32.316 50.064 32.4 50.088 ;
    END
  END q[306]
  PIN q[307]
    DIRECTION OUTPUT ;
    USE SIGNAL ;
    PORT
      LAYER M4 ;
        RECT  32.316 50.16 32.4 50.184 ;
    END
  END q[307]
  PIN q[308]
    DIRECTION OUTPUT ;
    USE SIGNAL ;
    PORT
      LAYER M4 ;
        RECT  32.316 50.256 32.4 50.28 ;
    END
  END q[308]
  PIN q[309]
    DIRECTION OUTPUT ;
    USE SIGNAL ;
    PORT
      LAYER M4 ;
        RECT  32.316 50.352 32.4 50.376 ;
    END
  END q[309]
  PIN q[30]
    DIRECTION OUTPUT ;
    USE SIGNAL ;
    PORT
      LAYER M4 ;
        RECT  32.316 22.8 32.4 22.824 ;
    END
  END q[30]
  PIN q[310]
    DIRECTION OUTPUT ;
    USE SIGNAL ;
    PORT
      LAYER M4 ;
        RECT  32.316 50.448 32.4 50.472 ;
    END
  END q[310]
  PIN q[311]
    DIRECTION OUTPUT ;
    USE SIGNAL ;
    PORT
      LAYER M4 ;
        RECT  32.316 50.544 32.4 50.568 ;
    END
  END q[311]
  PIN q[312]
    DIRECTION OUTPUT ;
    USE SIGNAL ;
    PORT
      LAYER M4 ;
        RECT  32.316 50.64 32.4 50.664 ;
    END
  END q[312]
  PIN q[313]
    DIRECTION OUTPUT ;
    USE SIGNAL ;
    PORT
      LAYER M4 ;
        RECT  32.316 50.736 32.4 50.76 ;
    END
  END q[313]
  PIN q[314]
    DIRECTION OUTPUT ;
    USE SIGNAL ;
    PORT
      LAYER M4 ;
        RECT  32.316 50.832 32.4 50.856 ;
    END
  END q[314]
  PIN q[315]
    DIRECTION OUTPUT ;
    USE SIGNAL ;
    PORT
      LAYER M4 ;
        RECT  32.316 50.928 32.4 50.952 ;
    END
  END q[315]
  PIN q[316]
    DIRECTION OUTPUT ;
    USE SIGNAL ;
    PORT
      LAYER M4 ;
        RECT  32.316 51.024 32.4 51.048 ;
    END
  END q[316]
  PIN q[317]
    DIRECTION OUTPUT ;
    USE SIGNAL ;
    PORT
      LAYER M4 ;
        RECT  32.316 51.12 32.4 51.144 ;
    END
  END q[317]
  PIN q[318]
    DIRECTION OUTPUT ;
    USE SIGNAL ;
    PORT
      LAYER M4 ;
        RECT  32.316 51.216 32.4 51.24 ;
    END
  END q[318]
  PIN q[319]
    DIRECTION OUTPUT ;
    USE SIGNAL ;
    PORT
      LAYER M4 ;
        RECT  32.316 51.312 32.4 51.336 ;
    END
  END q[319]
  PIN q[31]
    DIRECTION OUTPUT ;
    USE SIGNAL ;
    PORT
      LAYER M4 ;
        RECT  32.316 22.896 32.4 22.92 ;
    END
  END q[31]
  PIN q[320]
    DIRECTION OUTPUT ;
    USE SIGNAL ;
    PORT
      LAYER M4 ;
        RECT  32.316 29.136 32.4 29.16 ;
    END
  END q[320]
  PIN q[321]
    DIRECTION OUTPUT ;
    USE SIGNAL ;
    PORT
      LAYER M4 ;
        RECT  32.316 29.232 32.4 29.256 ;
    END
  END q[321]
  PIN q[322]
    DIRECTION OUTPUT ;
    USE SIGNAL ;
    PORT
      LAYER M4 ;
        RECT  32.316 29.328 32.4 29.352 ;
    END
  END q[322]
  PIN q[323]
    DIRECTION OUTPUT ;
    USE SIGNAL ;
    PORT
      LAYER M4 ;
        RECT  32.316 29.424 32.4 29.448 ;
    END
  END q[323]
  PIN q[324]
    DIRECTION OUTPUT ;
    USE SIGNAL ;
    PORT
      LAYER M4 ;
        RECT  32.316 29.52 32.4 29.544 ;
    END
  END q[324]
  PIN q[325]
    DIRECTION OUTPUT ;
    USE SIGNAL ;
    PORT
      LAYER M4 ;
        RECT  32.316 29.616 32.4 29.64 ;
    END
  END q[325]
  PIN q[326]
    DIRECTION OUTPUT ;
    USE SIGNAL ;
    PORT
      LAYER M4 ;
        RECT  32.316 29.712 32.4 29.736 ;
    END
  END q[326]
  PIN q[327]
    DIRECTION OUTPUT ;
    USE SIGNAL ;
    PORT
      LAYER M4 ;
        RECT  32.316 29.808 32.4 29.832 ;
    END
  END q[327]
  PIN q[328]
    DIRECTION OUTPUT ;
    USE SIGNAL ;
    PORT
      LAYER M4 ;
        RECT  32.316 29.904 32.4 29.928 ;
    END
  END q[328]
  PIN q[329]
    DIRECTION OUTPUT ;
    USE SIGNAL ;
    PORT
      LAYER M4 ;
        RECT  32.316 30 32.4 30.024 ;
    END
  END q[329]
  PIN q[32]
    DIRECTION OUTPUT ;
    USE SIGNAL ;
    PORT
      LAYER M4 ;
        RECT  32.316 32.208 32.4 32.232 ;
    END
  END q[32]
  PIN q[330]
    DIRECTION OUTPUT ;
    USE SIGNAL ;
    PORT
      LAYER M4 ;
        RECT  32.316 30.096 32.4 30.12 ;
    END
  END q[330]
  PIN q[331]
    DIRECTION OUTPUT ;
    USE SIGNAL ;
    PORT
      LAYER M4 ;
        RECT  32.316 30.192 32.4 30.216 ;
    END
  END q[331]
  PIN q[332]
    DIRECTION OUTPUT ;
    USE SIGNAL ;
    PORT
      LAYER M4 ;
        RECT  32.316 30.288 32.4 30.312 ;
    END
  END q[332]
  PIN q[333]
    DIRECTION OUTPUT ;
    USE SIGNAL ;
    PORT
      LAYER M4 ;
        RECT  32.316 30.384 32.4 30.408 ;
    END
  END q[333]
  PIN q[334]
    DIRECTION OUTPUT ;
    USE SIGNAL ;
    PORT
      LAYER M4 ;
        RECT  32.316 30.48 32.4 30.504 ;
    END
  END q[334]
  PIN q[335]
    DIRECTION OUTPUT ;
    USE SIGNAL ;
    PORT
      LAYER M4 ;
        RECT  32.316 30.576 32.4 30.6 ;
    END
  END q[335]
  PIN q[336]
    DIRECTION OUTPUT ;
    USE SIGNAL ;
    PORT
      LAYER M4 ;
        RECT  32.316 30.672 32.4 30.696 ;
    END
  END q[336]
  PIN q[337]
    DIRECTION OUTPUT ;
    USE SIGNAL ;
    PORT
      LAYER M4 ;
        RECT  32.316 30.768 32.4 30.792 ;
    END
  END q[337]
  PIN q[338]
    DIRECTION OUTPUT ;
    USE SIGNAL ;
    PORT
      LAYER M4 ;
        RECT  32.316 30.864 32.4 30.888 ;
    END
  END q[338]
  PIN q[339]
    DIRECTION OUTPUT ;
    USE SIGNAL ;
    PORT
      LAYER M4 ;
        RECT  32.316 30.96 32.4 30.984 ;
    END
  END q[339]
  PIN q[33]
    DIRECTION OUTPUT ;
    USE SIGNAL ;
    PORT
      LAYER M4 ;
        RECT  32.316 32.304 32.4 32.328 ;
    END
  END q[33]
  PIN q[340]
    DIRECTION OUTPUT ;
    USE SIGNAL ;
    PORT
      LAYER M4 ;
        RECT  32.316 31.056 32.4 31.08 ;
    END
  END q[340]
  PIN q[341]
    DIRECTION OUTPUT ;
    USE SIGNAL ;
    PORT
      LAYER M4 ;
        RECT  32.316 31.152 32.4 31.176 ;
    END
  END q[341]
  PIN q[342]
    DIRECTION OUTPUT ;
    USE SIGNAL ;
    PORT
      LAYER M4 ;
        RECT  32.316 31.248 32.4 31.272 ;
    END
  END q[342]
  PIN q[343]
    DIRECTION OUTPUT ;
    USE SIGNAL ;
    PORT
      LAYER M4 ;
        RECT  32.316 31.344 32.4 31.368 ;
    END
  END q[343]
  PIN q[344]
    DIRECTION OUTPUT ;
    USE SIGNAL ;
    PORT
      LAYER M4 ;
        RECT  32.316 31.44 32.4 31.464 ;
    END
  END q[344]
  PIN q[345]
    DIRECTION OUTPUT ;
    USE SIGNAL ;
    PORT
      LAYER M4 ;
        RECT  32.316 31.536 32.4 31.56 ;
    END
  END q[345]
  PIN q[346]
    DIRECTION OUTPUT ;
    USE SIGNAL ;
    PORT
      LAYER M4 ;
        RECT  32.316 31.632 32.4 31.656 ;
    END
  END q[346]
  PIN q[347]
    DIRECTION OUTPUT ;
    USE SIGNAL ;
    PORT
      LAYER M4 ;
        RECT  32.316 31.728 32.4 31.752 ;
    END
  END q[347]
  PIN q[348]
    DIRECTION OUTPUT ;
    USE SIGNAL ;
    PORT
      LAYER M4 ;
        RECT  32.316 31.824 32.4 31.848 ;
    END
  END q[348]
  PIN q[349]
    DIRECTION OUTPUT ;
    USE SIGNAL ;
    PORT
      LAYER M4 ;
        RECT  32.316 31.92 32.4 31.944 ;
    END
  END q[349]
  PIN q[34]
    DIRECTION OUTPUT ;
    USE SIGNAL ;
    PORT
      LAYER M4 ;
        RECT  32.316 32.4 32.4 32.424 ;
    END
  END q[34]
  PIN q[350]
    DIRECTION OUTPUT ;
    USE SIGNAL ;
    PORT
      LAYER M4 ;
        RECT  32.316 32.016 32.4 32.04 ;
    END
  END q[350]
  PIN q[351]
    DIRECTION OUTPUT ;
    USE SIGNAL ;
    PORT
      LAYER M4 ;
        RECT  32.316 32.112 32.4 32.136 ;
    END
  END q[351]
  PIN q[352]
    DIRECTION OUTPUT ;
    USE SIGNAL ;
    PORT
      LAYER M4 ;
        RECT  32.316 42.192 32.4 42.216 ;
    END
  END q[352]
  PIN q[353]
    DIRECTION OUTPUT ;
    USE SIGNAL ;
    PORT
      LAYER M4 ;
        RECT  32.316 42.288 32.4 42.312 ;
    END
  END q[353]
  PIN q[354]
    DIRECTION OUTPUT ;
    USE SIGNAL ;
    PORT
      LAYER M4 ;
        RECT  32.316 42.384 32.4 42.408 ;
    END
  END q[354]
  PIN q[355]
    DIRECTION OUTPUT ;
    USE SIGNAL ;
    PORT
      LAYER M4 ;
        RECT  32.316 42.48 32.4 42.504 ;
    END
  END q[355]
  PIN q[356]
    DIRECTION OUTPUT ;
    USE SIGNAL ;
    PORT
      LAYER M4 ;
        RECT  32.316 42.576 32.4 42.6 ;
    END
  END q[356]
  PIN q[357]
    DIRECTION OUTPUT ;
    USE SIGNAL ;
    PORT
      LAYER M4 ;
        RECT  32.316 42.672 32.4 42.696 ;
    END
  END q[357]
  PIN q[358]
    DIRECTION OUTPUT ;
    USE SIGNAL ;
    PORT
      LAYER M4 ;
        RECT  32.316 42.768 32.4 42.792 ;
    END
  END q[358]
  PIN q[359]
    DIRECTION OUTPUT ;
    USE SIGNAL ;
    PORT
      LAYER M4 ;
        RECT  32.316 42.864 32.4 42.888 ;
    END
  END q[359]
  PIN q[35]
    DIRECTION OUTPUT ;
    USE SIGNAL ;
    PORT
      LAYER M4 ;
        RECT  32.316 32.496 32.4 32.52 ;
    END
  END q[35]
  PIN q[360]
    DIRECTION OUTPUT ;
    USE SIGNAL ;
    PORT
      LAYER M4 ;
        RECT  32.316 42.96 32.4 42.984 ;
    END
  END q[360]
  PIN q[361]
    DIRECTION OUTPUT ;
    USE SIGNAL ;
    PORT
      LAYER M4 ;
        RECT  32.316 43.056 32.4 43.08 ;
    END
  END q[361]
  PIN q[362]
    DIRECTION OUTPUT ;
    USE SIGNAL ;
    PORT
      LAYER M4 ;
        RECT  32.316 43.152 32.4 43.176 ;
    END
  END q[362]
  PIN q[363]
    DIRECTION OUTPUT ;
    USE SIGNAL ;
    PORT
      LAYER M4 ;
        RECT  32.316 43.248 32.4 43.272 ;
    END
  END q[363]
  PIN q[364]
    DIRECTION OUTPUT ;
    USE SIGNAL ;
    PORT
      LAYER M4 ;
        RECT  32.316 43.344 32.4 43.368 ;
    END
  END q[364]
  PIN q[365]
    DIRECTION OUTPUT ;
    USE SIGNAL ;
    PORT
      LAYER M4 ;
        RECT  32.316 43.44 32.4 43.464 ;
    END
  END q[365]
  PIN q[366]
    DIRECTION OUTPUT ;
    USE SIGNAL ;
    PORT
      LAYER M4 ;
        RECT  32.316 43.536 32.4 43.56 ;
    END
  END q[366]
  PIN q[367]
    DIRECTION OUTPUT ;
    USE SIGNAL ;
    PORT
      LAYER M4 ;
        RECT  32.316 43.632 32.4 43.656 ;
    END
  END q[367]
  PIN q[368]
    DIRECTION OUTPUT ;
    USE SIGNAL ;
    PORT
      LAYER M4 ;
        RECT  32.316 43.728 32.4 43.752 ;
    END
  END q[368]
  PIN q[369]
    DIRECTION OUTPUT ;
    USE SIGNAL ;
    PORT
      LAYER M4 ;
        RECT  32.316 43.824 32.4 43.848 ;
    END
  END q[369]
  PIN q[36]
    DIRECTION OUTPUT ;
    USE SIGNAL ;
    PORT
      LAYER M4 ;
        RECT  32.316 32.592 32.4 32.616 ;
    END
  END q[36]
  PIN q[370]
    DIRECTION OUTPUT ;
    USE SIGNAL ;
    PORT
      LAYER M4 ;
        RECT  32.316 43.92 32.4 43.944 ;
    END
  END q[370]
  PIN q[371]
    DIRECTION OUTPUT ;
    USE SIGNAL ;
    PORT
      LAYER M4 ;
        RECT  32.316 44.016 32.4 44.04 ;
    END
  END q[371]
  PIN q[372]
    DIRECTION OUTPUT ;
    USE SIGNAL ;
    PORT
      LAYER M4 ;
        RECT  32.316 44.112 32.4 44.136 ;
    END
  END q[372]
  PIN q[373]
    DIRECTION OUTPUT ;
    USE SIGNAL ;
    PORT
      LAYER M4 ;
        RECT  32.316 44.208 32.4 44.232 ;
    END
  END q[373]
  PIN q[374]
    DIRECTION OUTPUT ;
    USE SIGNAL ;
    PORT
      LAYER M4 ;
        RECT  32.316 44.304 32.4 44.328 ;
    END
  END q[374]
  PIN q[375]
    DIRECTION OUTPUT ;
    USE SIGNAL ;
    PORT
      LAYER M4 ;
        RECT  32.316 44.4 32.4 44.424 ;
    END
  END q[375]
  PIN q[376]
    DIRECTION OUTPUT ;
    USE SIGNAL ;
    PORT
      LAYER M4 ;
        RECT  32.316 44.496 32.4 44.52 ;
    END
  END q[376]
  PIN q[377]
    DIRECTION OUTPUT ;
    USE SIGNAL ;
    PORT
      LAYER M4 ;
        RECT  32.316 44.592 32.4 44.616 ;
    END
  END q[377]
  PIN q[378]
    DIRECTION OUTPUT ;
    USE SIGNAL ;
    PORT
      LAYER M4 ;
        RECT  32.316 44.688 32.4 44.712 ;
    END
  END q[378]
  PIN q[379]
    DIRECTION OUTPUT ;
    USE SIGNAL ;
    PORT
      LAYER M4 ;
        RECT  32.316 44.784 32.4 44.808 ;
    END
  END q[379]
  PIN q[37]
    DIRECTION OUTPUT ;
    USE SIGNAL ;
    PORT
      LAYER M4 ;
        RECT  32.316 32.688 32.4 32.712 ;
    END
  END q[37]
  PIN q[380]
    DIRECTION OUTPUT ;
    USE SIGNAL ;
    PORT
      LAYER M4 ;
        RECT  32.316 44.88 32.4 44.904 ;
    END
  END q[380]
  PIN q[381]
    DIRECTION OUTPUT ;
    USE SIGNAL ;
    PORT
      LAYER M4 ;
        RECT  32.316 44.976 32.4 45 ;
    END
  END q[381]
  PIN q[382]
    DIRECTION OUTPUT ;
    USE SIGNAL ;
    PORT
      LAYER M4 ;
        RECT  32.316 45.072 32.4 45.096 ;
    END
  END q[382]
  PIN q[383]
    DIRECTION OUTPUT ;
    USE SIGNAL ;
    PORT
      LAYER M4 ;
        RECT  32.316 45.168 32.4 45.192 ;
    END
  END q[383]
  PIN q[384]
    DIRECTION OUTPUT ;
    USE SIGNAL ;
    PORT
      LAYER M4 ;
        RECT  32.316 61.392 32.4 61.416 ;
    END
  END q[384]
  PIN q[385]
    DIRECTION OUTPUT ;
    USE SIGNAL ;
    PORT
      LAYER M4 ;
        RECT  32.316 61.488 32.4 61.512 ;
    END
  END q[385]
  PIN q[386]
    DIRECTION OUTPUT ;
    USE SIGNAL ;
    PORT
      LAYER M4 ;
        RECT  32.316 61.584 32.4 61.608 ;
    END
  END q[386]
  PIN q[387]
    DIRECTION OUTPUT ;
    USE SIGNAL ;
    PORT
      LAYER M4 ;
        RECT  32.316 61.68 32.4 61.704 ;
    END
  END q[387]
  PIN q[388]
    DIRECTION OUTPUT ;
    USE SIGNAL ;
    PORT
      LAYER M4 ;
        RECT  32.316 61.776 32.4 61.8 ;
    END
  END q[388]
  PIN q[389]
    DIRECTION OUTPUT ;
    USE SIGNAL ;
    PORT
      LAYER M4 ;
        RECT  32.316 61.872 32.4 61.896 ;
    END
  END q[389]
  PIN q[38]
    DIRECTION OUTPUT ;
    USE SIGNAL ;
    PORT
      LAYER M4 ;
        RECT  32.316 32.784 32.4 32.808 ;
    END
  END q[38]
  PIN q[390]
    DIRECTION OUTPUT ;
    USE SIGNAL ;
    PORT
      LAYER M4 ;
        RECT  32.316 61.968 32.4 61.992 ;
    END
  END q[390]
  PIN q[391]
    DIRECTION OUTPUT ;
    USE SIGNAL ;
    PORT
      LAYER M4 ;
        RECT  32.316 62.064 32.4 62.088 ;
    END
  END q[391]
  PIN q[392]
    DIRECTION OUTPUT ;
    USE SIGNAL ;
    PORT
      LAYER M4 ;
        RECT  32.316 62.16 32.4 62.184 ;
    END
  END q[392]
  PIN q[393]
    DIRECTION OUTPUT ;
    USE SIGNAL ;
    PORT
      LAYER M4 ;
        RECT  32.316 62.256 32.4 62.28 ;
    END
  END q[393]
  PIN q[394]
    DIRECTION OUTPUT ;
    USE SIGNAL ;
    PORT
      LAYER M4 ;
        RECT  32.316 62.352 32.4 62.376 ;
    END
  END q[394]
  PIN q[395]
    DIRECTION OUTPUT ;
    USE SIGNAL ;
    PORT
      LAYER M4 ;
        RECT  32.316 62.448 32.4 62.472 ;
    END
  END q[395]
  PIN q[396]
    DIRECTION OUTPUT ;
    USE SIGNAL ;
    PORT
      LAYER M4 ;
        RECT  32.316 62.544 32.4 62.568 ;
    END
  END q[396]
  PIN q[397]
    DIRECTION OUTPUT ;
    USE SIGNAL ;
    PORT
      LAYER M4 ;
        RECT  32.316 62.64 32.4 62.664 ;
    END
  END q[397]
  PIN q[398]
    DIRECTION OUTPUT ;
    USE SIGNAL ;
    PORT
      LAYER M4 ;
        RECT  32.316 62.736 32.4 62.76 ;
    END
  END q[398]
  PIN q[399]
    DIRECTION OUTPUT ;
    USE SIGNAL ;
    PORT
      LAYER M4 ;
        RECT  32.316 62.832 32.4 62.856 ;
    END
  END q[399]
  PIN q[39]
    DIRECTION OUTPUT ;
    USE SIGNAL ;
    PORT
      LAYER M4 ;
        RECT  32.316 32.88 32.4 32.904 ;
    END
  END q[39]
  PIN q[3]
    DIRECTION OUTPUT ;
    USE SIGNAL ;
    PORT
      LAYER M4 ;
        RECT  32.316 20.208 32.4 20.232 ;
    END
  END q[3]
  PIN q[400]
    DIRECTION OUTPUT ;
    USE SIGNAL ;
    PORT
      LAYER M4 ;
        RECT  32.316 62.928 32.4 62.952 ;
    END
  END q[400]
  PIN q[401]
    DIRECTION OUTPUT ;
    USE SIGNAL ;
    PORT
      LAYER M4 ;
        RECT  32.316 63.024 32.4 63.048 ;
    END
  END q[401]
  PIN q[402]
    DIRECTION OUTPUT ;
    USE SIGNAL ;
    PORT
      LAYER M4 ;
        RECT  32.316 63.12 32.4 63.144 ;
    END
  END q[402]
  PIN q[403]
    DIRECTION OUTPUT ;
    USE SIGNAL ;
    PORT
      LAYER M4 ;
        RECT  32.316 63.216 32.4 63.24 ;
    END
  END q[403]
  PIN q[404]
    DIRECTION OUTPUT ;
    USE SIGNAL ;
    PORT
      LAYER M4 ;
        RECT  32.316 63.312 32.4 63.336 ;
    END
  END q[404]
  PIN q[405]
    DIRECTION OUTPUT ;
    USE SIGNAL ;
    PORT
      LAYER M4 ;
        RECT  32.316 63.408 32.4 63.432 ;
    END
  END q[405]
  PIN q[406]
    DIRECTION OUTPUT ;
    USE SIGNAL ;
    PORT
      LAYER M4 ;
        RECT  32.316 63.504 32.4 63.528 ;
    END
  END q[406]
  PIN q[407]
    DIRECTION OUTPUT ;
    USE SIGNAL ;
    PORT
      LAYER M4 ;
        RECT  32.316 63.6 32.4 63.624 ;
    END
  END q[407]
  PIN q[408]
    DIRECTION OUTPUT ;
    USE SIGNAL ;
    PORT
      LAYER M4 ;
        RECT  32.316 63.696 32.4 63.72 ;
    END
  END q[408]
  PIN q[409]
    DIRECTION OUTPUT ;
    USE SIGNAL ;
    PORT
      LAYER M4 ;
        RECT  32.316 63.792 32.4 63.816 ;
    END
  END q[409]
  PIN q[40]
    DIRECTION OUTPUT ;
    USE SIGNAL ;
    PORT
      LAYER M4 ;
        RECT  32.316 32.976 32.4 33 ;
    END
  END q[40]
  PIN q[410]
    DIRECTION OUTPUT ;
    USE SIGNAL ;
    PORT
      LAYER M4 ;
        RECT  32.316 63.888 32.4 63.912 ;
    END
  END q[410]
  PIN q[411]
    DIRECTION OUTPUT ;
    USE SIGNAL ;
    PORT
      LAYER M4 ;
        RECT  32.316 63.984 32.4 64.008 ;
    END
  END q[411]
  PIN q[412]
    DIRECTION OUTPUT ;
    USE SIGNAL ;
    PORT
      LAYER M4 ;
        RECT  32.316 64.08 32.4 64.104 ;
    END
  END q[412]
  PIN q[413]
    DIRECTION OUTPUT ;
    USE SIGNAL ;
    PORT
      LAYER M4 ;
        RECT  32.316 64.176 32.4 64.2 ;
    END
  END q[413]
  PIN q[414]
    DIRECTION OUTPUT ;
    USE SIGNAL ;
    PORT
      LAYER M4 ;
        RECT  32.316 64.272 32.4 64.296 ;
    END
  END q[414]
  PIN q[415]
    DIRECTION OUTPUT ;
    USE SIGNAL ;
    PORT
      LAYER M4 ;
        RECT  32.316 64.368 32.4 64.392 ;
    END
  END q[415]
  PIN q[416]
    DIRECTION OUTPUT ;
    USE SIGNAL ;
    PORT
      LAYER M4 ;
        RECT  32.316 13.008 32.4 13.032 ;
    END
  END q[416]
  PIN q[417]
    DIRECTION OUTPUT ;
    USE SIGNAL ;
    PORT
      LAYER M4 ;
        RECT  32.316 13.104 32.4 13.128 ;
    END
  END q[417]
  PIN q[418]
    DIRECTION OUTPUT ;
    USE SIGNAL ;
    PORT
      LAYER M4 ;
        RECT  32.316 13.2 32.4 13.224 ;
    END
  END q[418]
  PIN q[419]
    DIRECTION OUTPUT ;
    USE SIGNAL ;
    PORT
      LAYER M4 ;
        RECT  32.316 13.296 32.4 13.32 ;
    END
  END q[419]
  PIN q[41]
    DIRECTION OUTPUT ;
    USE SIGNAL ;
    PORT
      LAYER M4 ;
        RECT  32.316 33.072 32.4 33.096 ;
    END
  END q[41]
  PIN q[420]
    DIRECTION OUTPUT ;
    USE SIGNAL ;
    PORT
      LAYER M4 ;
        RECT  32.316 13.392 32.4 13.416 ;
    END
  END q[420]
  PIN q[421]
    DIRECTION OUTPUT ;
    USE SIGNAL ;
    PORT
      LAYER M4 ;
        RECT  32.316 13.488 32.4 13.512 ;
    END
  END q[421]
  PIN q[422]
    DIRECTION OUTPUT ;
    USE SIGNAL ;
    PORT
      LAYER M4 ;
        RECT  32.316 13.584 32.4 13.608 ;
    END
  END q[422]
  PIN q[423]
    DIRECTION OUTPUT ;
    USE SIGNAL ;
    PORT
      LAYER M4 ;
        RECT  32.316 13.68 32.4 13.704 ;
    END
  END q[423]
  PIN q[424]
    DIRECTION OUTPUT ;
    USE SIGNAL ;
    PORT
      LAYER M4 ;
        RECT  32.316 13.776 32.4 13.8 ;
    END
  END q[424]
  PIN q[425]
    DIRECTION OUTPUT ;
    USE SIGNAL ;
    PORT
      LAYER M4 ;
        RECT  32.316 13.872 32.4 13.896 ;
    END
  END q[425]
  PIN q[426]
    DIRECTION OUTPUT ;
    USE SIGNAL ;
    PORT
      LAYER M4 ;
        RECT  32.316 13.968 32.4 13.992 ;
    END
  END q[426]
  PIN q[427]
    DIRECTION OUTPUT ;
    USE SIGNAL ;
    PORT
      LAYER M4 ;
        RECT  32.316 14.064 32.4 14.088 ;
    END
  END q[427]
  PIN q[428]
    DIRECTION OUTPUT ;
    USE SIGNAL ;
    PORT
      LAYER M4 ;
        RECT  32.316 14.16 32.4 14.184 ;
    END
  END q[428]
  PIN q[429]
    DIRECTION OUTPUT ;
    USE SIGNAL ;
    PORT
      LAYER M4 ;
        RECT  32.316 14.256 32.4 14.28 ;
    END
  END q[429]
  PIN q[42]
    DIRECTION OUTPUT ;
    USE SIGNAL ;
    PORT
      LAYER M4 ;
        RECT  32.316 33.168 32.4 33.192 ;
    END
  END q[42]
  PIN q[430]
    DIRECTION OUTPUT ;
    USE SIGNAL ;
    PORT
      LAYER M4 ;
        RECT  32.316 14.352 32.4 14.376 ;
    END
  END q[430]
  PIN q[431]
    DIRECTION OUTPUT ;
    USE SIGNAL ;
    PORT
      LAYER M4 ;
        RECT  32.316 14.448 32.4 14.472 ;
    END
  END q[431]
  PIN q[432]
    DIRECTION OUTPUT ;
    USE SIGNAL ;
    PORT
      LAYER M4 ;
        RECT  32.316 14.544 32.4 14.568 ;
    END
  END q[432]
  PIN q[433]
    DIRECTION OUTPUT ;
    USE SIGNAL ;
    PORT
      LAYER M4 ;
        RECT  32.316 14.64 32.4 14.664 ;
    END
  END q[433]
  PIN q[434]
    DIRECTION OUTPUT ;
    USE SIGNAL ;
    PORT
      LAYER M4 ;
        RECT  32.316 14.736 32.4 14.76 ;
    END
  END q[434]
  PIN q[435]
    DIRECTION OUTPUT ;
    USE SIGNAL ;
    PORT
      LAYER M4 ;
        RECT  32.316 14.832 32.4 14.856 ;
    END
  END q[435]
  PIN q[436]
    DIRECTION OUTPUT ;
    USE SIGNAL ;
    PORT
      LAYER M4 ;
        RECT  32.316 14.928 32.4 14.952 ;
    END
  END q[436]
  PIN q[437]
    DIRECTION OUTPUT ;
    USE SIGNAL ;
    PORT
      LAYER M4 ;
        RECT  32.316 15.024 32.4 15.048 ;
    END
  END q[437]
  PIN q[438]
    DIRECTION OUTPUT ;
    USE SIGNAL ;
    PORT
      LAYER M4 ;
        RECT  32.316 15.12 32.4 15.144 ;
    END
  END q[438]
  PIN q[439]
    DIRECTION OUTPUT ;
    USE SIGNAL ;
    PORT
      LAYER M4 ;
        RECT  32.316 15.216 32.4 15.24 ;
    END
  END q[439]
  PIN q[43]
    DIRECTION OUTPUT ;
    USE SIGNAL ;
    PORT
      LAYER M4 ;
        RECT  32.316 33.264 32.4 33.288 ;
    END
  END q[43]
  PIN q[440]
    DIRECTION OUTPUT ;
    USE SIGNAL ;
    PORT
      LAYER M4 ;
        RECT  32.316 15.312 32.4 15.336 ;
    END
  END q[440]
  PIN q[441]
    DIRECTION OUTPUT ;
    USE SIGNAL ;
    PORT
      LAYER M4 ;
        RECT  32.316 15.408 32.4 15.432 ;
    END
  END q[441]
  PIN q[442]
    DIRECTION OUTPUT ;
    USE SIGNAL ;
    PORT
      LAYER M4 ;
        RECT  32.316 15.504 32.4 15.528 ;
    END
  END q[442]
  PIN q[443]
    DIRECTION OUTPUT ;
    USE SIGNAL ;
    PORT
      LAYER M4 ;
        RECT  32.316 15.6 32.4 15.624 ;
    END
  END q[443]
  PIN q[444]
    DIRECTION OUTPUT ;
    USE SIGNAL ;
    PORT
      LAYER M4 ;
        RECT  32.316 15.696 32.4 15.72 ;
    END
  END q[444]
  PIN q[445]
    DIRECTION OUTPUT ;
    USE SIGNAL ;
    PORT
      LAYER M4 ;
        RECT  32.316 15.792 32.4 15.816 ;
    END
  END q[445]
  PIN q[446]
    DIRECTION OUTPUT ;
    USE SIGNAL ;
    PORT
      LAYER M4 ;
        RECT  32.316 15.888 32.4 15.912 ;
    END
  END q[446]
  PIN q[447]
    DIRECTION OUTPUT ;
    USE SIGNAL ;
    PORT
      LAYER M4 ;
        RECT  32.316 15.984 32.4 16.008 ;
    END
  END q[447]
  PIN q[448]
    DIRECTION OUTPUT ;
    USE SIGNAL ;
    PORT
      LAYER M4 ;
        RECT  32.316 16.08 32.4 16.104 ;
    END
  END q[448]
  PIN q[449]
    DIRECTION OUTPUT ;
    USE SIGNAL ;
    PORT
      LAYER M4 ;
        RECT  32.316 16.176 32.4 16.2 ;
    END
  END q[449]
  PIN q[44]
    DIRECTION OUTPUT ;
    USE SIGNAL ;
    PORT
      LAYER M4 ;
        RECT  32.316 33.36 32.4 33.384 ;
    END
  END q[44]
  PIN q[450]
    DIRECTION OUTPUT ;
    USE SIGNAL ;
    PORT
      LAYER M4 ;
        RECT  32.316 16.272 32.4 16.296 ;
    END
  END q[450]
  PIN q[451]
    DIRECTION OUTPUT ;
    USE SIGNAL ;
    PORT
      LAYER M4 ;
        RECT  32.316 16.368 32.4 16.392 ;
    END
  END q[451]
  PIN q[452]
    DIRECTION OUTPUT ;
    USE SIGNAL ;
    PORT
      LAYER M4 ;
        RECT  32.316 16.464 32.4 16.488 ;
    END
  END q[452]
  PIN q[453]
    DIRECTION OUTPUT ;
    USE SIGNAL ;
    PORT
      LAYER M4 ;
        RECT  32.316 16.56 32.4 16.584 ;
    END
  END q[453]
  PIN q[454]
    DIRECTION OUTPUT ;
    USE SIGNAL ;
    PORT
      LAYER M4 ;
        RECT  32.316 16.656 32.4 16.68 ;
    END
  END q[454]
  PIN q[455]
    DIRECTION OUTPUT ;
    USE SIGNAL ;
    PORT
      LAYER M4 ;
        RECT  32.316 16.752 32.4 16.776 ;
    END
  END q[455]
  PIN q[456]
    DIRECTION OUTPUT ;
    USE SIGNAL ;
    PORT
      LAYER M4 ;
        RECT  32.316 16.848 32.4 16.872 ;
    END
  END q[456]
  PIN q[457]
    DIRECTION OUTPUT ;
    USE SIGNAL ;
    PORT
      LAYER M4 ;
        RECT  32.316 16.944 32.4 16.968 ;
    END
  END q[457]
  PIN q[458]
    DIRECTION OUTPUT ;
    USE SIGNAL ;
    PORT
      LAYER M4 ;
        RECT  32.316 17.04 32.4 17.064 ;
    END
  END q[458]
  PIN q[459]
    DIRECTION OUTPUT ;
    USE SIGNAL ;
    PORT
      LAYER M4 ;
        RECT  32.316 17.136 32.4 17.16 ;
    END
  END q[459]
  PIN q[45]
    DIRECTION OUTPUT ;
    USE SIGNAL ;
    PORT
      LAYER M4 ;
        RECT  32.316 33.456 32.4 33.48 ;
    END
  END q[45]
  PIN q[460]
    DIRECTION OUTPUT ;
    USE SIGNAL ;
    PORT
      LAYER M4 ;
        RECT  32.316 17.232 32.4 17.256 ;
    END
  END q[460]
  PIN q[461]
    DIRECTION OUTPUT ;
    USE SIGNAL ;
    PORT
      LAYER M4 ;
        RECT  32.316 17.328 32.4 17.352 ;
    END
  END q[461]
  PIN q[462]
    DIRECTION OUTPUT ;
    USE SIGNAL ;
    PORT
      LAYER M4 ;
        RECT  32.316 17.424 32.4 17.448 ;
    END
  END q[462]
  PIN q[463]
    DIRECTION OUTPUT ;
    USE SIGNAL ;
    PORT
      LAYER M4 ;
        RECT  32.316 17.52 32.4 17.544 ;
    END
  END q[463]
  PIN q[464]
    DIRECTION OUTPUT ;
    USE SIGNAL ;
    PORT
      LAYER M4 ;
        RECT  32.316 17.616 32.4 17.64 ;
    END
  END q[464]
  PIN q[465]
    DIRECTION OUTPUT ;
    USE SIGNAL ;
    PORT
      LAYER M4 ;
        RECT  32.316 17.712 32.4 17.736 ;
    END
  END q[465]
  PIN q[466]
    DIRECTION OUTPUT ;
    USE SIGNAL ;
    PORT
      LAYER M4 ;
        RECT  32.316 17.808 32.4 17.832 ;
    END
  END q[466]
  PIN q[467]
    DIRECTION OUTPUT ;
    USE SIGNAL ;
    PORT
      LAYER M4 ;
        RECT  32.316 17.904 32.4 17.928 ;
    END
  END q[467]
  PIN q[468]
    DIRECTION OUTPUT ;
    USE SIGNAL ;
    PORT
      LAYER M4 ;
        RECT  32.316 18 32.4 18.024 ;
    END
  END q[468]
  PIN q[469]
    DIRECTION OUTPUT ;
    USE SIGNAL ;
    PORT
      LAYER M4 ;
        RECT  32.316 18.096 32.4 18.12 ;
    END
  END q[469]
  PIN q[46]
    DIRECTION OUTPUT ;
    USE SIGNAL ;
    PORT
      LAYER M4 ;
        RECT  32.316 33.552 32.4 33.576 ;
    END
  END q[46]
  PIN q[470]
    DIRECTION OUTPUT ;
    USE SIGNAL ;
    PORT
      LAYER M4 ;
        RECT  32.316 18.192 32.4 18.216 ;
    END
  END q[470]
  PIN q[471]
    DIRECTION OUTPUT ;
    USE SIGNAL ;
    PORT
      LAYER M4 ;
        RECT  32.316 18.288 32.4 18.312 ;
    END
  END q[471]
  PIN q[472]
    DIRECTION OUTPUT ;
    USE SIGNAL ;
    PORT
      LAYER M4 ;
        RECT  32.316 18.384 32.4 18.408 ;
    END
  END q[472]
  PIN q[473]
    DIRECTION OUTPUT ;
    USE SIGNAL ;
    PORT
      LAYER M4 ;
        RECT  32.316 18.48 32.4 18.504 ;
    END
  END q[473]
  PIN q[474]
    DIRECTION OUTPUT ;
    USE SIGNAL ;
    PORT
      LAYER M4 ;
        RECT  32.316 18.576 32.4 18.6 ;
    END
  END q[474]
  PIN q[475]
    DIRECTION OUTPUT ;
    USE SIGNAL ;
    PORT
      LAYER M4 ;
        RECT  32.316 18.672 32.4 18.696 ;
    END
  END q[475]
  PIN q[476]
    DIRECTION OUTPUT ;
    USE SIGNAL ;
    PORT
      LAYER M4 ;
        RECT  32.316 18.768 32.4 18.792 ;
    END
  END q[476]
  PIN q[477]
    DIRECTION OUTPUT ;
    USE SIGNAL ;
    PORT
      LAYER M4 ;
        RECT  32.316 18.864 32.4 18.888 ;
    END
  END q[477]
  PIN q[478]
    DIRECTION OUTPUT ;
    USE SIGNAL ;
    PORT
      LAYER M4 ;
        RECT  32.316 18.96 32.4 18.984 ;
    END
  END q[478]
  PIN q[479]
    DIRECTION OUTPUT ;
    USE SIGNAL ;
    PORT
      LAYER M4 ;
        RECT  32.316 19.056 32.4 19.08 ;
    END
  END q[479]
  PIN q[47]
    DIRECTION OUTPUT ;
    USE SIGNAL ;
    PORT
      LAYER M4 ;
        RECT  32.316 33.648 32.4 33.672 ;
    END
  END q[47]
  PIN q[480]
    DIRECTION OUTPUT ;
    USE SIGNAL ;
    PORT
      LAYER M4 ;
        RECT  32.316 58.32 32.4 58.344 ;
    END
  END q[480]
  PIN q[481]
    DIRECTION OUTPUT ;
    USE SIGNAL ;
    PORT
      LAYER M4 ;
        RECT  32.316 58.416 32.4 58.44 ;
    END
  END q[481]
  PIN q[482]
    DIRECTION OUTPUT ;
    USE SIGNAL ;
    PORT
      LAYER M4 ;
        RECT  32.316 58.512 32.4 58.536 ;
    END
  END q[482]
  PIN q[483]
    DIRECTION OUTPUT ;
    USE SIGNAL ;
    PORT
      LAYER M4 ;
        RECT  32.316 58.608 32.4 58.632 ;
    END
  END q[483]
  PIN q[484]
    DIRECTION OUTPUT ;
    USE SIGNAL ;
    PORT
      LAYER M4 ;
        RECT  32.316 58.704 32.4 58.728 ;
    END
  END q[484]
  PIN q[485]
    DIRECTION OUTPUT ;
    USE SIGNAL ;
    PORT
      LAYER M4 ;
        RECT  32.316 58.8 32.4 58.824 ;
    END
  END q[485]
  PIN q[486]
    DIRECTION OUTPUT ;
    USE SIGNAL ;
    PORT
      LAYER M4 ;
        RECT  32.316 58.896 32.4 58.92 ;
    END
  END q[486]
  PIN q[487]
    DIRECTION OUTPUT ;
    USE SIGNAL ;
    PORT
      LAYER M4 ;
        RECT  32.316 58.992 32.4 59.016 ;
    END
  END q[487]
  PIN q[488]
    DIRECTION OUTPUT ;
    USE SIGNAL ;
    PORT
      LAYER M4 ;
        RECT  32.316 59.088 32.4 59.112 ;
    END
  END q[488]
  PIN q[489]
    DIRECTION OUTPUT ;
    USE SIGNAL ;
    PORT
      LAYER M4 ;
        RECT  32.316 59.184 32.4 59.208 ;
    END
  END q[489]
  PIN q[48]
    DIRECTION OUTPUT ;
    USE SIGNAL ;
    PORT
      LAYER M4 ;
        RECT  32.316 33.744 32.4 33.768 ;
    END
  END q[48]
  PIN q[490]
    DIRECTION OUTPUT ;
    USE SIGNAL ;
    PORT
      LAYER M4 ;
        RECT  32.316 59.28 32.4 59.304 ;
    END
  END q[490]
  PIN q[491]
    DIRECTION OUTPUT ;
    USE SIGNAL ;
    PORT
      LAYER M4 ;
        RECT  32.316 59.376 32.4 59.4 ;
    END
  END q[491]
  PIN q[492]
    DIRECTION OUTPUT ;
    USE SIGNAL ;
    PORT
      LAYER M4 ;
        RECT  32.316 59.472 32.4 59.496 ;
    END
  END q[492]
  PIN q[493]
    DIRECTION OUTPUT ;
    USE SIGNAL ;
    PORT
      LAYER M4 ;
        RECT  32.316 59.568 32.4 59.592 ;
    END
  END q[493]
  PIN q[494]
    DIRECTION OUTPUT ;
    USE SIGNAL ;
    PORT
      LAYER M4 ;
        RECT  32.316 59.664 32.4 59.688 ;
    END
  END q[494]
  PIN q[495]
    DIRECTION OUTPUT ;
    USE SIGNAL ;
    PORT
      LAYER M4 ;
        RECT  32.316 59.76 32.4 59.784 ;
    END
  END q[495]
  PIN q[496]
    DIRECTION OUTPUT ;
    USE SIGNAL ;
    PORT
      LAYER M4 ;
        RECT  32.316 59.856 32.4 59.88 ;
    END
  END q[496]
  PIN q[497]
    DIRECTION OUTPUT ;
    USE SIGNAL ;
    PORT
      LAYER M4 ;
        RECT  32.316 59.952 32.4 59.976 ;
    END
  END q[497]
  PIN q[498]
    DIRECTION OUTPUT ;
    USE SIGNAL ;
    PORT
      LAYER M4 ;
        RECT  32.316 60.048 32.4 60.072 ;
    END
  END q[498]
  PIN q[499]
    DIRECTION OUTPUT ;
    USE SIGNAL ;
    PORT
      LAYER M4 ;
        RECT  32.316 60.144 32.4 60.168 ;
    END
  END q[499]
  PIN q[49]
    DIRECTION OUTPUT ;
    USE SIGNAL ;
    PORT
      LAYER M4 ;
        RECT  32.316 33.84 32.4 33.864 ;
    END
  END q[49]
  PIN q[4]
    DIRECTION OUTPUT ;
    USE SIGNAL ;
    PORT
      LAYER M4 ;
        RECT  32.316 20.304 32.4 20.328 ;
    END
  END q[4]
  PIN q[500]
    DIRECTION OUTPUT ;
    USE SIGNAL ;
    PORT
      LAYER M4 ;
        RECT  32.316 60.24 32.4 60.264 ;
    END
  END q[500]
  PIN q[501]
    DIRECTION OUTPUT ;
    USE SIGNAL ;
    PORT
      LAYER M4 ;
        RECT  32.316 60.336 32.4 60.36 ;
    END
  END q[501]
  PIN q[502]
    DIRECTION OUTPUT ;
    USE SIGNAL ;
    PORT
      LAYER M4 ;
        RECT  32.316 60.432 32.4 60.456 ;
    END
  END q[502]
  PIN q[503]
    DIRECTION OUTPUT ;
    USE SIGNAL ;
    PORT
      LAYER M4 ;
        RECT  32.316 60.528 32.4 60.552 ;
    END
  END q[503]
  PIN q[504]
    DIRECTION OUTPUT ;
    USE SIGNAL ;
    PORT
      LAYER M4 ;
        RECT  32.316 60.624 32.4 60.648 ;
    END
  END q[504]
  PIN q[505]
    DIRECTION OUTPUT ;
    USE SIGNAL ;
    PORT
      LAYER M4 ;
        RECT  32.316 60.72 32.4 60.744 ;
    END
  END q[505]
  PIN q[506]
    DIRECTION OUTPUT ;
    USE SIGNAL ;
    PORT
      LAYER M4 ;
        RECT  32.316 60.816 32.4 60.84 ;
    END
  END q[506]
  PIN q[507]
    DIRECTION OUTPUT ;
    USE SIGNAL ;
    PORT
      LAYER M4 ;
        RECT  32.316 60.912 32.4 60.936 ;
    END
  END q[507]
  PIN q[508]
    DIRECTION OUTPUT ;
    USE SIGNAL ;
    PORT
      LAYER M4 ;
        RECT  32.316 61.008 32.4 61.032 ;
    END
  END q[508]
  PIN q[509]
    DIRECTION OUTPUT ;
    USE SIGNAL ;
    PORT
      LAYER M4 ;
        RECT  32.316 61.104 32.4 61.128 ;
    END
  END q[509]
  PIN q[50]
    DIRECTION OUTPUT ;
    USE SIGNAL ;
    PORT
      LAYER M4 ;
        RECT  32.316 33.936 32.4 33.96 ;
    END
  END q[50]
  PIN q[510]
    DIRECTION OUTPUT ;
    USE SIGNAL ;
    PORT
      LAYER M4 ;
        RECT  32.316 61.2 32.4 61.224 ;
    END
  END q[510]
  PIN q[511]
    DIRECTION OUTPUT ;
    USE SIGNAL ;
    PORT
      LAYER M4 ;
        RECT  32.316 61.296 32.4 61.32 ;
    END
  END q[511]
  PIN q[51]
    DIRECTION OUTPUT ;
    USE SIGNAL ;
    PORT
      LAYER M4 ;
        RECT  32.316 34.032 32.4 34.056 ;
    END
  END q[51]
  PIN q[52]
    DIRECTION OUTPUT ;
    USE SIGNAL ;
    PORT
      LAYER M4 ;
        RECT  32.316 34.128 32.4 34.152 ;
    END
  END q[52]
  PIN q[53]
    DIRECTION OUTPUT ;
    USE SIGNAL ;
    PORT
      LAYER M4 ;
        RECT  32.316 34.224 32.4 34.248 ;
    END
  END q[53]
  PIN q[54]
    DIRECTION OUTPUT ;
    USE SIGNAL ;
    PORT
      LAYER M4 ;
        RECT  32.316 34.32 32.4 34.344 ;
    END
  END q[54]
  PIN q[55]
    DIRECTION OUTPUT ;
    USE SIGNAL ;
    PORT
      LAYER M4 ;
        RECT  32.316 34.416 32.4 34.44 ;
    END
  END q[55]
  PIN q[56]
    DIRECTION OUTPUT ;
    USE SIGNAL ;
    PORT
      LAYER M4 ;
        RECT  32.316 34.512 32.4 34.536 ;
    END
  END q[56]
  PIN q[57]
    DIRECTION OUTPUT ;
    USE SIGNAL ;
    PORT
      LAYER M4 ;
        RECT  32.316 34.608 32.4 34.632 ;
    END
  END q[57]
  PIN q[58]
    DIRECTION OUTPUT ;
    USE SIGNAL ;
    PORT
      LAYER M4 ;
        RECT  32.316 34.704 32.4 34.728 ;
    END
  END q[58]
  PIN q[59]
    DIRECTION OUTPUT ;
    USE SIGNAL ;
    PORT
      LAYER M4 ;
        RECT  32.316 34.8 32.4 34.824 ;
    END
  END q[59]
  PIN q[5]
    DIRECTION OUTPUT ;
    USE SIGNAL ;
    PORT
      LAYER M4 ;
        RECT  32.316 20.4 32.4 20.424 ;
    END
  END q[5]
  PIN q[60]
    DIRECTION OUTPUT ;
    USE SIGNAL ;
    PORT
      LAYER M4 ;
        RECT  32.316 34.896 32.4 34.92 ;
    END
  END q[60]
  PIN q[61]
    DIRECTION OUTPUT ;
    USE SIGNAL ;
    PORT
      LAYER M4 ;
        RECT  32.316 34.992 32.4 35.016 ;
    END
  END q[61]
  PIN q[62]
    DIRECTION OUTPUT ;
    USE SIGNAL ;
    PORT
      LAYER M4 ;
        RECT  32.316 35.088 32.4 35.112 ;
    END
  END q[62]
  PIN q[63]
    DIRECTION OUTPUT ;
    USE SIGNAL ;
    PORT
      LAYER M4 ;
        RECT  32.316 35.184 32.4 35.208 ;
    END
  END q[63]
  PIN q[64]
    DIRECTION OUTPUT ;
    USE SIGNAL ;
    PORT
      LAYER M4 ;
        RECT  32.316 26.064 32.4 26.088 ;
    END
  END q[64]
  PIN q[65]
    DIRECTION OUTPUT ;
    USE SIGNAL ;
    PORT
      LAYER M4 ;
        RECT  32.316 26.16 32.4 26.184 ;
    END
  END q[65]
  PIN q[66]
    DIRECTION OUTPUT ;
    USE SIGNAL ;
    PORT
      LAYER M4 ;
        RECT  32.316 26.256 32.4 26.28 ;
    END
  END q[66]
  PIN q[67]
    DIRECTION OUTPUT ;
    USE SIGNAL ;
    PORT
      LAYER M4 ;
        RECT  32.316 26.352 32.4 26.376 ;
    END
  END q[67]
  PIN q[68]
    DIRECTION OUTPUT ;
    USE SIGNAL ;
    PORT
      LAYER M4 ;
        RECT  32.316 26.448 32.4 26.472 ;
    END
  END q[68]
  PIN q[69]
    DIRECTION OUTPUT ;
    USE SIGNAL ;
    PORT
      LAYER M4 ;
        RECT  32.316 26.544 32.4 26.568 ;
    END
  END q[69]
  PIN q[6]
    DIRECTION OUTPUT ;
    USE SIGNAL ;
    PORT
      LAYER M4 ;
        RECT  32.316 20.496 32.4 20.52 ;
    END
  END q[6]
  PIN q[70]
    DIRECTION OUTPUT ;
    USE SIGNAL ;
    PORT
      LAYER M4 ;
        RECT  32.316 26.64 32.4 26.664 ;
    END
  END q[70]
  PIN q[71]
    DIRECTION OUTPUT ;
    USE SIGNAL ;
    PORT
      LAYER M4 ;
        RECT  32.316 26.736 32.4 26.76 ;
    END
  END q[71]
  PIN q[72]
    DIRECTION OUTPUT ;
    USE SIGNAL ;
    PORT
      LAYER M4 ;
        RECT  32.316 26.832 32.4 26.856 ;
    END
  END q[72]
  PIN q[73]
    DIRECTION OUTPUT ;
    USE SIGNAL ;
    PORT
      LAYER M4 ;
        RECT  32.316 26.928 32.4 26.952 ;
    END
  END q[73]
  PIN q[74]
    DIRECTION OUTPUT ;
    USE SIGNAL ;
    PORT
      LAYER M4 ;
        RECT  32.316 27.024 32.4 27.048 ;
    END
  END q[74]
  PIN q[75]
    DIRECTION OUTPUT ;
    USE SIGNAL ;
    PORT
      LAYER M4 ;
        RECT  32.316 27.12 32.4 27.144 ;
    END
  END q[75]
  PIN q[76]
    DIRECTION OUTPUT ;
    USE SIGNAL ;
    PORT
      LAYER M4 ;
        RECT  32.316 27.216 32.4 27.24 ;
    END
  END q[76]
  PIN q[77]
    DIRECTION OUTPUT ;
    USE SIGNAL ;
    PORT
      LAYER M4 ;
        RECT  32.316 27.312 32.4 27.336 ;
    END
  END q[77]
  PIN q[78]
    DIRECTION OUTPUT ;
    USE SIGNAL ;
    PORT
      LAYER M4 ;
        RECT  32.316 27.408 32.4 27.432 ;
    END
  END q[78]
  PIN q[79]
    DIRECTION OUTPUT ;
    USE SIGNAL ;
    PORT
      LAYER M4 ;
        RECT  32.316 27.504 32.4 27.528 ;
    END
  END q[79]
  PIN q[7]
    DIRECTION OUTPUT ;
    USE SIGNAL ;
    PORT
      LAYER M4 ;
        RECT  32.316 20.592 32.4 20.616 ;
    END
  END q[7]
  PIN q[80]
    DIRECTION OUTPUT ;
    USE SIGNAL ;
    PORT
      LAYER M4 ;
        RECT  32.316 27.6 32.4 27.624 ;
    END
  END q[80]
  PIN q[81]
    DIRECTION OUTPUT ;
    USE SIGNAL ;
    PORT
      LAYER M4 ;
        RECT  32.316 27.696 32.4 27.72 ;
    END
  END q[81]
  PIN q[82]
    DIRECTION OUTPUT ;
    USE SIGNAL ;
    PORT
      LAYER M4 ;
        RECT  32.316 27.792 32.4 27.816 ;
    END
  END q[82]
  PIN q[83]
    DIRECTION OUTPUT ;
    USE SIGNAL ;
    PORT
      LAYER M4 ;
        RECT  32.316 27.888 32.4 27.912 ;
    END
  END q[83]
  PIN q[84]
    DIRECTION OUTPUT ;
    USE SIGNAL ;
    PORT
      LAYER M4 ;
        RECT  32.316 27.984 32.4 28.008 ;
    END
  END q[84]
  PIN q[85]
    DIRECTION OUTPUT ;
    USE SIGNAL ;
    PORT
      LAYER M4 ;
        RECT  32.316 28.08 32.4 28.104 ;
    END
  END q[85]
  PIN q[86]
    DIRECTION OUTPUT ;
    USE SIGNAL ;
    PORT
      LAYER M4 ;
        RECT  32.316 28.176 32.4 28.2 ;
    END
  END q[86]
  PIN q[87]
    DIRECTION OUTPUT ;
    USE SIGNAL ;
    PORT
      LAYER M4 ;
        RECT  32.316 28.272 32.4 28.296 ;
    END
  END q[87]
  PIN q[88]
    DIRECTION OUTPUT ;
    USE SIGNAL ;
    PORT
      LAYER M4 ;
        RECT  32.316 28.368 32.4 28.392 ;
    END
  END q[88]
  PIN q[89]
    DIRECTION OUTPUT ;
    USE SIGNAL ;
    PORT
      LAYER M4 ;
        RECT  32.316 28.464 32.4 28.488 ;
    END
  END q[89]
  PIN q[8]
    DIRECTION OUTPUT ;
    USE SIGNAL ;
    PORT
      LAYER M4 ;
        RECT  32.316 20.688 32.4 20.712 ;
    END
  END q[8]
  PIN q[90]
    DIRECTION OUTPUT ;
    USE SIGNAL ;
    PORT
      LAYER M4 ;
        RECT  32.316 28.56 32.4 28.584 ;
    END
  END q[90]
  PIN q[91]
    DIRECTION OUTPUT ;
    USE SIGNAL ;
    PORT
      LAYER M4 ;
        RECT  32.316 28.656 32.4 28.68 ;
    END
  END q[91]
  PIN q[92]
    DIRECTION OUTPUT ;
    USE SIGNAL ;
    PORT
      LAYER M4 ;
        RECT  32.316 28.752 32.4 28.776 ;
    END
  END q[92]
  PIN q[93]
    DIRECTION OUTPUT ;
    USE SIGNAL ;
    PORT
      LAYER M4 ;
        RECT  32.316 28.848 32.4 28.872 ;
    END
  END q[93]
  PIN q[94]
    DIRECTION OUTPUT ;
    USE SIGNAL ;
    PORT
      LAYER M4 ;
        RECT  32.316 28.944 32.4 28.968 ;
    END
  END q[94]
  PIN q[95]
    DIRECTION OUTPUT ;
    USE SIGNAL ;
    PORT
      LAYER M4 ;
        RECT  32.316 29.04 32.4 29.064 ;
    END
  END q[95]
  PIN q[96]
    DIRECTION OUTPUT ;
    USE SIGNAL ;
    PORT
      LAYER M4 ;
        RECT  32.316 51.408 32.4 51.432 ;
    END
  END q[96]
  PIN q[97]
    DIRECTION OUTPUT ;
    USE SIGNAL ;
    PORT
      LAYER M4 ;
        RECT  32.316 51.504 32.4 51.528 ;
    END
  END q[97]
  PIN q[98]
    DIRECTION OUTPUT ;
    USE SIGNAL ;
    PORT
      LAYER M4 ;
        RECT  32.316 51.6 32.4 51.624 ;
    END
  END q[98]
  PIN q[99]
    DIRECTION OUTPUT ;
    USE SIGNAL ;
    PORT
      LAYER M4 ;
        RECT  32.316 51.696 32.4 51.72 ;
    END
  END q[99]
  PIN q[9]
    DIRECTION OUTPUT ;
    USE SIGNAL ;
    PORT
      LAYER M4 ;
        RECT  32.316 20.784 32.4 20.808 ;
    END
  END q[9]
  PIN VDD
    DIRECTION INOUT ;
    USE POWER ;
    PORT
      LAYER M5 ;
        RECT  29.592 2.151 29.712 82.089 ;
        RECT  24.192 2.151 24.312 82.089 ;
        RECT  18.792 2.151 18.912 82.089 ;
        RECT  13.392 2.151 13.512 82.089 ;
        RECT  7.992 2.151 8.112 82.089 ;
        RECT  2.592 2.151 2.712 82.089 ;
    END
  END VDD
  PIN VSS
    DIRECTION INOUT ;
    USE GROUND ;
    PORT
      LAYER M5 ;
        RECT  29.4 2.137 29.52 82.103 ;
        RECT  24 2.137 24.12 82.103 ;
        RECT  18.6 2.137 18.72 82.103 ;
        RECT  13.2 2.137 13.32 82.103 ;
        RECT  7.8 2.137 7.92 82.103 ;
        RECT  2.4 2.137 2.52 82.103 ;
    END
  END VSS
  # OT_OBS_CLOSED layer=M5 d_um=1.536 added=292
  OBS
    LAYER RVTN ;
     RECT  2.16 2.16 30.24 2.295 ;
     RECT  2.16 2.565 30.24 2.835 ;
     RECT  2.16 3.105 30.24 3.375 ;
     RECT  2.16 3.645 30.24 3.915 ;
     RECT  2.16 4.185 30.24 4.455 ;
     RECT  2.16 4.725 30.24 4.995 ;
     RECT  2.16 5.265 30.24 5.535 ;
     RECT  2.16 5.805 30.24 6.075 ;
     RECT  2.16 6.345 30.24 6.615 ;
     RECT  2.16 6.885 30.24 7.155 ;
     RECT  2.16 7.425 30.24 7.695 ;
     RECT  2.16 7.965 30.24 8.235 ;
     RECT  2.16 8.505 30.24 8.775 ;
     RECT  2.16 9.045 30.24 9.315 ;
     RECT  2.16 9.585 30.24 9.855 ;
     RECT  2.16 10.125 30.24 10.395 ;
     RECT  2.16 10.665 30.24 10.935 ;
     RECT  2.16 11.205 30.24 11.475 ;
     RECT  2.16 11.745 30.24 12.015 ;
     RECT  2.16 12.285 30.24 12.555 ;
     RECT  2.16 12.825 30.24 13.095 ;
     RECT  2.16 13.365 30.24 13.635 ;
     RECT  2.16 13.905 30.24 14.175 ;
     RECT  2.16 14.445 30.24 14.715 ;
     RECT  2.16 14.985 30.24 15.255 ;
     RECT  2.16 15.525 30.24 15.795 ;
     RECT  2.16 16.065 30.24 16.335 ;
     RECT  2.16 16.605 30.24 16.875 ;
     RECT  2.16 17.145 30.24 17.415 ;
     RECT  2.16 17.685 30.24 17.955 ;
     RECT  2.16 18.225 30.24 18.495 ;
     RECT  2.16 18.765 30.24 19.035 ;
     RECT  2.16 19.305 30.24 19.575 ;
     RECT  2.16 19.845 30.24 20.115 ;
     RECT  2.16 20.385 30.24 20.655 ;
     RECT  2.16 20.925 30.24 21.195 ;
     RECT  2.16 21.465 30.24 21.735 ;
     RECT  2.16 22.005 30.24 22.275 ;
     RECT  2.16 22.545 30.24 22.815 ;
     RECT  2.16 23.085 30.24 23.355 ;
     RECT  2.16 23.625 30.24 23.895 ;
     RECT  2.16 24.165 30.24 24.435 ;
     RECT  2.16 24.705 30.24 24.975 ;
     RECT  2.16 25.245 30.24 25.515 ;
     RECT  2.16 25.785 30.24 26.055 ;
     RECT  2.16 26.325 30.24 26.595 ;
     RECT  2.16 26.865 30.24 27.135 ;
     RECT  2.16 27.405 30.24 27.675 ;
     RECT  2.16 27.945 30.24 28.215 ;
     RECT  2.16 28.485 30.24 28.755 ;
     RECT  2.16 29.025 30.24 29.295 ;
     RECT  2.16 29.565 30.24 29.835 ;
     RECT  2.16 30.105 30.24 30.375 ;
     RECT  2.16 30.645 30.24 30.915 ;
     RECT  2.16 31.185 30.24 31.455 ;
     RECT  2.16 31.725 30.24 31.995 ;
     RECT  2.16 32.265 30.24 32.535 ;
     RECT  2.16 32.805 30.24 33.075 ;
     RECT  2.16 33.345 30.24 33.615 ;
     RECT  2.16 33.885 30.24 34.155 ;
     RECT  2.16 34.425 30.24 34.695 ;
     RECT  2.16 34.965 30.24 35.235 ;
     RECT  2.16 35.505 30.24 35.775 ;
     RECT  2.16 36.045 30.24 36.315 ;
     RECT  2.16 36.585 30.24 36.855 ;
     RECT  2.16 37.125 30.24 37.395 ;
     RECT  2.16 37.665 30.24 37.935 ;
     RECT  2.16 38.205 30.24 38.475 ;
     RECT  2.16 38.745 30.24 39.015 ;
     RECT  2.16 39.285 30.24 39.555 ;
     RECT  2.16 39.825 30.24 40.095 ;
     RECT  2.16 40.365 30.24 40.635 ;
     RECT  2.16 40.905 30.24 41.175 ;
     RECT  2.16 41.445 30.24 41.715 ;
     RECT  2.16 41.985 30.24 42.255 ;
     RECT  2.16 42.525 30.24 42.795 ;
     RECT  2.16 43.065 30.24 43.335 ;
     RECT  2.16 43.605 30.24 43.875 ;
     RECT  2.16 44.145 30.24 44.415 ;
     RECT  2.16 44.685 30.24 44.955 ;
     RECT  2.16 45.225 30.24 45.495 ;
     RECT  2.16 45.765 30.24 46.035 ;
     RECT  2.16 46.305 30.24 46.575 ;
     RECT  2.16 46.845 30.24 47.115 ;
     RECT  2.16 47.385 30.24 47.655 ;
     RECT  2.16 47.925 30.24 48.195 ;
     RECT  2.16 48.465 30.24 48.735 ;
     RECT  2.16 49.005 30.24 49.275 ;
     RECT  2.16 49.545 30.24 49.815 ;
     RECT  2.16 50.085 30.24 50.355 ;
     RECT  2.16 50.625 30.24 50.895 ;
     RECT  2.16 51.165 30.24 51.435 ;
     RECT  2.16 51.705 30.24 51.975 ;
     RECT  2.16 52.245 30.24 52.515 ;
     RECT  2.16 52.785 30.24 53.055 ;
     RECT  2.16 53.325 30.24 53.595 ;
     RECT  2.16 53.865 30.24 54.135 ;
     RECT  2.16 54.405 30.24 54.675 ;
     RECT  2.16 54.945 30.24 55.215 ;
     RECT  2.16 55.485 30.24 55.755 ;
     RECT  2.16 56.025 30.24 56.295 ;
     RECT  2.16 56.565 30.24 56.835 ;
     RECT  2.16 57.105 30.24 57.375 ;
     RECT  2.16 57.645 30.24 57.915 ;
     RECT  2.16 58.185 30.24 58.455 ;
     RECT  2.16 58.725 30.24 58.995 ;
     RECT  2.16 59.265 30.24 59.535 ;
     RECT  2.16 59.805 30.24 60.075 ;
     RECT  2.16 60.345 30.24 60.615 ;
     RECT  2.16 60.885 30.24 61.155 ;
     RECT  2.16 61.425 30.24 61.695 ;
     RECT  2.16 61.965 30.24 62.235 ;
     RECT  2.16 62.505 30.24 62.775 ;
     RECT  2.16 63.045 30.24 63.315 ;
     RECT  2.16 63.585 30.24 63.855 ;
     RECT  2.16 64.125 30.24 64.395 ;
     RECT  2.16 64.665 30.24 64.935 ;
     RECT  2.16 65.205 30.24 65.475 ;
     RECT  2.16 65.745 30.24 66.015 ;
     RECT  2.16 66.285 30.24 66.555 ;
     RECT  2.16 66.825 30.24 67.095 ;
     RECT  2.16 67.365 30.24 67.635 ;
     RECT  2.16 67.905 30.24 68.175 ;
     RECT  2.16 68.445 30.24 68.715 ;
     RECT  2.16 68.985 30.24 69.255 ;
     RECT  2.16 69.525 30.24 69.795 ;
     RECT  2.16 70.065 30.24 70.335 ;
     RECT  2.16 70.605 30.24 70.875 ;
     RECT  2.16 71.145 30.24 71.415 ;
     RECT  2.16 71.685 30.24 71.955 ;
     RECT  2.16 72.225 30.24 72.495 ;
     RECT  2.16 72.765 30.24 73.035 ;
     RECT  2.16 73.305 30.24 73.575 ;
     RECT  2.16 73.845 30.24 74.115 ;
     RECT  2.16 74.385 30.24 74.655 ;
     RECT  2.16 74.925 30.24 75.195 ;
     RECT  2.16 75.465 30.24 75.735 ;
     RECT  2.16 76.005 30.24 76.275 ;
     RECT  2.16 76.545 30.24 76.815 ;
     RECT  2.16 77.085 30.24 77.355 ;
     RECT  2.16 77.625 30.24 77.895 ;
     RECT  2.16 78.165 30.24 78.435 ;
     RECT  2.16 78.705 30.24 78.975 ;
     RECT  2.16 79.245 30.24 79.515 ;
     RECT  2.16 79.785 30.24 80.055 ;
     RECT  2.16 80.325 30.24 80.595 ;
     RECT  2.16 80.865 30.24 81.135 ;
     RECT  2.16 81.405 30.24 81.675 ;
     RECT  2.16 81.945 30.24 82.08 ;
    LAYER RVTP ;
     RECT  2.16 2.295 30.24 2.565 ;
     RECT  2.16 2.835 30.24 3.105 ;
     RECT  2.16 3.375 30.24 3.645 ;
     RECT  2.16 3.915 30.24 4.185 ;
     RECT  2.16 4.455 30.24 4.725 ;
     RECT  2.16 4.995 30.24 5.265 ;
     RECT  2.16 5.535 30.24 5.805 ;
     RECT  2.16 6.075 30.24 6.345 ;
     RECT  2.16 6.615 30.24 6.885 ;
     RECT  2.16 7.155 30.24 7.425 ;
     RECT  2.16 7.695 30.24 7.965 ;
     RECT  2.16 8.235 30.24 8.505 ;
     RECT  2.16 8.775 30.24 9.045 ;
     RECT  2.16 9.315 30.24 9.585 ;
     RECT  2.16 9.855 30.24 10.125 ;
     RECT  2.16 10.395 30.24 10.665 ;
     RECT  2.16 10.935 30.24 11.205 ;
     RECT  2.16 11.475 30.24 11.745 ;
     RECT  2.16 12.015 30.24 12.285 ;
     RECT  2.16 12.555 30.24 12.825 ;
     RECT  2.16 13.095 30.24 13.365 ;
     RECT  2.16 13.635 30.24 13.905 ;
     RECT  2.16 14.175 30.24 14.445 ;
     RECT  2.16 14.715 30.24 14.985 ;
     RECT  2.16 15.255 30.24 15.525 ;
     RECT  2.16 15.795 30.24 16.065 ;
     RECT  2.16 16.335 30.24 16.605 ;
     RECT  2.16 16.875 30.24 17.145 ;
     RECT  2.16 17.415 30.24 17.685 ;
     RECT  2.16 17.955 30.24 18.225 ;
     RECT  2.16 18.495 30.24 18.765 ;
     RECT  2.16 19.035 30.24 19.305 ;
     RECT  2.16 19.575 30.24 19.845 ;
     RECT  2.16 20.115 30.24 20.385 ;
     RECT  2.16 20.655 30.24 20.925 ;
     RECT  2.16 21.195 30.24 21.465 ;
     RECT  2.16 21.735 30.24 22.005 ;
     RECT  2.16 22.275 30.24 22.545 ;
     RECT  2.16 22.815 30.24 23.085 ;
     RECT  2.16 23.355 30.24 23.625 ;
     RECT  2.16 23.895 30.24 24.165 ;
     RECT  2.16 24.435 30.24 24.705 ;
     RECT  2.16 24.975 30.24 25.245 ;
     RECT  2.16 25.515 30.24 25.785 ;
     RECT  2.16 26.055 30.24 26.325 ;
     RECT  2.16 26.595 30.24 26.865 ;
     RECT  2.16 27.135 30.24 27.405 ;
     RECT  2.16 27.675 30.24 27.945 ;
     RECT  2.16 28.215 30.24 28.485 ;
     RECT  2.16 28.755 30.24 29.025 ;
     RECT  2.16 29.295 30.24 29.565 ;
     RECT  2.16 29.835 30.24 30.105 ;
     RECT  2.16 30.375 30.24 30.645 ;
     RECT  2.16 30.915 30.24 31.185 ;
     RECT  2.16 31.455 30.24 31.725 ;
     RECT  2.16 31.995 30.24 32.265 ;
     RECT  2.16 32.535 30.24 32.805 ;
     RECT  2.16 33.075 30.24 33.345 ;
     RECT  2.16 33.615 30.24 33.885 ;
     RECT  2.16 34.155 30.24 34.425 ;
     RECT  2.16 34.695 30.24 34.965 ;
     RECT  2.16 35.235 30.24 35.505 ;
     RECT  2.16 35.775 30.24 36.045 ;
     RECT  2.16 36.315 30.24 36.585 ;
     RECT  2.16 36.855 30.24 37.125 ;
     RECT  2.16 37.395 30.24 37.665 ;
     RECT  2.16 37.935 30.24 38.205 ;
     RECT  2.16 38.475 30.24 38.745 ;
     RECT  2.16 39.015 30.24 39.285 ;
     RECT  2.16 39.555 30.24 39.825 ;
     RECT  2.16 40.095 30.24 40.365 ;
     RECT  2.16 40.635 30.24 40.905 ;
     RECT  2.16 41.175 30.24 41.445 ;
     RECT  2.16 41.715 30.24 41.985 ;
     RECT  2.16 42.255 30.24 42.525 ;
     RECT  2.16 42.795 30.24 43.065 ;
     RECT  2.16 43.335 30.24 43.605 ;
     RECT  2.16 43.875 30.24 44.145 ;
     RECT  2.16 44.415 30.24 44.685 ;
     RECT  2.16 44.955 30.24 45.225 ;
     RECT  2.16 45.495 30.24 45.765 ;
     RECT  2.16 46.035 30.24 46.305 ;
     RECT  2.16 46.575 30.24 46.845 ;
     RECT  2.16 47.115 30.24 47.385 ;
     RECT  2.16 47.655 30.24 47.925 ;
     RECT  2.16 48.195 30.24 48.465 ;
     RECT  2.16 48.735 30.24 49.005 ;
     RECT  2.16 49.275 30.24 49.545 ;
     RECT  2.16 49.815 30.24 50.085 ;
     RECT  2.16 50.355 30.24 50.625 ;
     RECT  2.16 50.895 30.24 51.165 ;
     RECT  2.16 51.435 30.24 51.705 ;
     RECT  2.16 51.975 30.24 52.245 ;
     RECT  2.16 52.515 30.24 52.785 ;
     RECT  2.16 53.055 30.24 53.325 ;
     RECT  2.16 53.595 30.24 53.865 ;
     RECT  2.16 54.135 30.24 54.405 ;
     RECT  2.16 54.675 30.24 54.945 ;
     RECT  2.16 55.215 30.24 55.485 ;
     RECT  2.16 55.755 30.24 56.025 ;
     RECT  2.16 56.295 30.24 56.565 ;
     RECT  2.16 56.835 30.24 57.105 ;
     RECT  2.16 57.375 30.24 57.645 ;
     RECT  2.16 57.915 30.24 58.185 ;
     RECT  2.16 58.455 30.24 58.725 ;
     RECT  2.16 58.995 30.24 59.265 ;
     RECT  2.16 59.535 30.24 59.805 ;
     RECT  2.16 60.075 30.24 60.345 ;
     RECT  2.16 60.615 30.24 60.885 ;
     RECT  2.16 61.155 30.24 61.425 ;
     RECT  2.16 61.695 30.24 61.965 ;
     RECT  2.16 62.235 30.24 62.505 ;
     RECT  2.16 62.775 30.24 63.045 ;
     RECT  2.16 63.315 30.24 63.585 ;
     RECT  2.16 63.855 30.24 64.125 ;
     RECT  2.16 64.395 30.24 64.665 ;
     RECT  2.16 64.935 30.24 65.205 ;
     RECT  2.16 65.475 30.24 65.745 ;
     RECT  2.16 66.015 30.24 66.285 ;
     RECT  2.16 66.555 30.24 66.825 ;
     RECT  2.16 67.095 30.24 67.365 ;
     RECT  2.16 67.635 30.24 67.905 ;
     RECT  2.16 68.175 30.24 68.445 ;
     RECT  2.16 68.715 30.24 68.985 ;
     RECT  2.16 69.255 30.24 69.525 ;
     RECT  2.16 69.795 30.24 70.065 ;
     RECT  2.16 70.335 30.24 70.605 ;
     RECT  2.16 70.875 30.24 71.145 ;
     RECT  2.16 71.415 30.24 71.685 ;
     RECT  2.16 71.955 30.24 72.225 ;
     RECT  2.16 72.495 30.24 72.765 ;
     RECT  2.16 73.035 30.24 73.305 ;
     RECT  2.16 73.575 30.24 73.845 ;
     RECT  2.16 74.115 30.24 74.385 ;
     RECT  2.16 74.655 30.24 74.925 ;
     RECT  2.16 75.195 30.24 75.465 ;
     RECT  2.16 75.735 30.24 76.005 ;
     RECT  2.16 76.275 30.24 76.545 ;
     RECT  2.16 76.815 30.24 77.085 ;
     RECT  2.16 77.355 30.24 77.625 ;
     RECT  2.16 77.895 30.24 78.165 ;
     RECT  2.16 78.435 30.24 78.705 ;
     RECT  2.16 78.975 30.24 79.245 ;
     RECT  2.16 79.515 30.24 79.785 ;
     RECT  2.16 80.055 30.24 80.325 ;
     RECT  2.16 80.595 30.24 80.865 ;
     RECT  2.16 81.135 30.24 81.405 ;
     RECT  2.16 81.675 30.24 81.945 ;
    LAYER M1 ;
     RECT  2.16 2.151 30.24 82.089 ;
    LAYER M2 ;
     RECT  0.031 18.162 0.067 18.18 ;
     RECT  0.031 20.286 0.103 20.304 ;
     RECT  0.067 21.24 0.103 21.258 ;
     RECT  0.103 19.62 0.139 21.258 ;
     RECT  0.103 34.74 0.139 34.758 ;
     RECT  0.103 37.602 0.139 37.62 ;
     RECT  0.103 46.08 0.139 46.098 ;
     RECT  0.103 47.862 0.139 48.15 ;
     RECT  0.103 48.942 0.139 48.96 ;
     RECT  0.103 50.904 0.139 50.922 ;
     RECT  0.103 58.662 0.139 58.68 ;
     RECT  0.103 65.412 0.139 65.43 ;
     RECT  0.139 19.548 0.167 21.258 ;
     RECT  0.103 22.212 0.175 22.572 ;
     RECT  0.103 26.1 0.175 26.118 ;
     RECT  0.103 29.61 0.175 29.628 ;
     RECT  0.139 47.862 0.175 48.96 ;
     RECT  0.139 58.662 0.175 59.256 ;
     RECT  0.103 60.39 0.175 60.408 ;
     RECT  0.139 65.412 0.175 65.502 ;
     RECT  0.175 26.028 0.211 26.118 ;
     RECT  0.103 27.18 0.211 27.936 ;
     RECT  0.175 58.662 0.247 60.408 ;
     RECT  0.103 31.23 0.283 31.716 ;
     RECT  0.175 57.312 0.283 57.33 ;
     RECT  0.283 30.69 0.319 31.716 ;
     RECT  0.139 50.904 0.347 51.156 ;
     RECT  0.347 51.138 0.383 51.156 ;
     RECT  0.139 34.704 0.463 34.758 ;
     RECT  0.283 57.312 0.463 57.438 ;
     RECT  0.175 22.131 0.499 22.572 ;
     RECT  0.139 37.602 0.499 38.16 ;
     RECT  0.463 51.21 0.499 51.264 ;
     RECT  0.067 18.162 0.535 18.558 ;
     RECT  0.167 19.548 0.535 21.186 ;
     RECT  0.103 23.328 0.535 23.346 ;
     RECT  0.319 30.654 0.535 31.716 ;
     RECT  0.103 32.472 0.535 33.174 ;
     RECT  0.499 37.602 0.535 38.196 ;
     RECT  0.175 47.862 0.535 48.996 ;
     RECT  0.499 51.21 0.535 51.534 ;
     RECT  0.499 53.91 0.535 53.928 ;
     RECT  0.499 55.26 0.535 55.278 ;
     RECT  0.463 56.304 0.535 57.438 ;
     RECT  0.247 58.662 0.535 60.606 ;
     RECT  0.175 65.412 0.535 65.7 ;
     RECT  0.535 55.26 0.563 57.438 ;
     RECT  1.147 72.972 1.183 72.99 ;
     RECT  1.183 72.972 1.399 73.26 ;
     RECT  1.471 72.162 1.723 72.18 ;
     RECT  1.399 72.972 1.759 73.8 ;
     RECT  1.723 71.73 1.975 72.18 ;
     RECT  1.759 72.972 1.975 73.872 ;
     RECT  1.975 71.73 2.011 73.872 ;
     RECT  1.399 17.082 2.16 17.1 ;
     RECT  0.535 18.162 2.16 21.186 ;
     RECT  0.499 21.942 2.16 22.572 ;
     RECT  0.535 23.328 2.16 23.922 ;
     RECT  0.211 26.028 2.16 27.936 ;
     RECT  0.175 29.034 2.16 29.628 ;
     RECT  0.535 30.654 2.16 33.174 ;
     RECT  0.463 33.966 2.16 34.758 ;
     RECT  0.535 37.602 2.16 38.7 ;
     RECT  0.535 41.76 2.16 41.778 ;
     RECT  0.535 42.534 2.16 42.552 ;
     RECT  0.139 45.972 2.16 46.098 ;
     RECT  0.535 47.736 2.16 49.572 ;
     RECT  0.535 51.21 2.16 51.768 ;
     RECT  0.211 52.758 2.16 52.776 ;
     RECT  0.535 53.532 2.16 54.468 ;
     RECT  0.563 55.26 2.16 56.322 ;
     RECT  0.563 57.312 2.16 57.438 ;
     RECT  0.535 58.536 2.16 61.218 ;
     RECT  0.535 61.974 2.16 61.992 ;
     RECT  0.535 63.252 2.16 63.27 ;
     RECT  0.535 65.412 2.16 65.772 ;
     RECT  0.103 66.87 2.16 66.888 ;
     RECT  0.103 68.382 2.16 68.4 ;
     RECT  0.103 70.074 2.16 70.092 ;
     RECT  2.011 71.73 2.16 74.07 ;
     RECT  2.16 2.151 30.24 82.089 ;
     RECT  30.24 11.556 30.263 12.474 ;
     RECT  30.24 69.696 30.299 69.822 ;
     RECT  30.24 66.258 30.335 68.094 ;
     RECT  30.24 75.906 30.371 75.924 ;
     RECT  30.335 66.258 30.407 66.744 ;
     RECT  30.24 7.398 30.479 7.416 ;
     RECT  30.24 68.886 30.479 68.904 ;
     RECT  30.24 10.476 30.551 10.494 ;
     RECT  30.24 13.41 30.695 65.124 ;
     RECT  30.695 64.566 30.731 65.124 ;
     RECT  30.695 13.41 30.767 63.774 ;
     RECT  30.731 64.566 30.767 64.584 ;
     RECT  30.767 13.41 30.803 61.884 ;
     RECT  30.803 19.854 30.839 44.172 ;
     RECT  30.407 66.726 31.055 66.744 ;
     RECT  30.839 20.322 31.271 44.172 ;
     RECT  31.271 20.322 31.307 42.174 ;
     RECT  30.803 45 31.307 61.884 ;
     RECT  30.803 13.41 31.343 18.954 ;
     RECT  31.307 20.322 31.343 26.514 ;
     RECT  31.307 27.306 31.343 42.174 ;
     RECT  31.271 42.966 31.343 44.172 ;
     RECT  31.307 45 31.343 48.114 ;
     RECT  31.307 48.978 31.343 56.826 ;
     RECT  31.307 57.996 31.343 61.884 ;
     RECT  30.767 62.676 31.343 63.774 ;
     RECT  30.335 67.536 31.343 68.094 ;
     RECT  31.343 14.922 31.379 15.516 ;
     RECT  31.343 16.506 31.379 18.216 ;
     RECT  31.343 20.322 31.379 24.696 ;
     RECT  31.343 25.488 31.379 26.28 ;
     RECT  31.343 30.186 31.379 36.414 ;
     RECT  31.343 37.206 31.379 37.62 ;
     RECT  31.343 39.294 31.379 39.312 ;
     RECT  31.343 40.068 31.379 42.129 ;
     RECT  31.343 43.416 31.379 44.172 ;
     RECT  31.343 45.126 31.379 45.288 ;
     RECT  31.343 46.044 31.379 47.88 ;
     RECT  31.343 51.516 31.379 54.324 ;
     RECT  31.343 55.116 31.379 55.134 ;
     RECT  31.343 55.962 31.379 56.826 ;
     RECT  31.343 57.996 31.379 58.986 ;
     RECT  31.343 59.814 31.379 61.884 ;
     RECT  30.263 11.826 31.415 12.474 ;
     RECT  31.343 13.536 31.415 14.094 ;
     RECT  31.379 16.506 31.415 16.794 ;
     RECT  31.379 20.322 31.415 20.34 ;
     RECT  31.379 25.524 31.415 26.082 ;
     RECT  31.343 27.378 31.415 29.016 ;
     RECT  31.379 30.186 31.415 31.284 ;
     RECT  31.379 32.472 31.415 32.832 ;
     RECT  31.379 40.608 31.415 42.129 ;
     RECT  31.379 43.416 31.415 43.524 ;
     RECT  31.379 47.088 31.415 47.88 ;
     RECT  31.415 11.826 31.451 12.384 ;
     RECT  31.379 17.586 31.451 18.216 ;
     RECT  31.379 22.212 31.451 22.734 ;
     RECT  31.415 25.524 31.451 25.542 ;
     RECT  31.451 11.826 31.487 11.844 ;
     RECT  31.415 27.684 32.215 27.864 ;
     RECT  31.415 30.186 32.215 30.366 ;
     RECT  31.379 33.588 32.215 35.226 ;
     RECT  31.379 36.018 32.215 36.234 ;
     RECT  31.379 14.922 32.243 15.354 ;
     RECT  31.379 23.67 32.243 24.264 ;
     RECT  32.215 30.186 32.243 30.438 ;
     RECT  31.379 51.516 32.243 52.776 ;
     RECT  31.379 60.588 32.243 61.884 ;
     RECT  32.243 15.192 32.279 15.354 ;
     RECT  32.215 33.588 32.279 36.234 ;
     RECT  31.343 49.176 32.279 50.616 ;
     RECT  32.243 51.606 32.279 52.776 ;
     RECT  31.379 54.108 32.279 54.324 ;
     RECT  32.243 60.588 32.279 61.794 ;
     RECT  32.279 54.108 32.287 54.126 ;
     RECT  31.415 13.536 32.315 13.554 ;
     RECT  32.279 15.336 32.315 15.354 ;
     RECT  31.415 16.506 32.315 16.524 ;
     RECT  31.451 18.198 32.315 18.216 ;
     RECT  31.379 21.096 32.315 21.114 ;
     RECT  31.451 22.212 32.315 22.23 ;
     RECT  32.243 23.796 32.315 24.264 ;
     RECT  32.215 27.216 32.315 27.864 ;
     RECT  31.415 28.998 32.315 29.016 ;
     RECT  32.243 30.348 32.315 30.438 ;
     RECT  31.415 31.266 32.315 31.284 ;
     RECT  31.415 32.814 32.315 32.832 ;
     RECT  32.279 33.588 32.315 36.036 ;
     RECT  31.379 37.206 32.315 37.224 ;
     RECT  31.415 41.148 32.315 42.129 ;
     RECT  31.415 43.416 32.315 43.434 ;
     RECT  31.379 46.044 32.315 46.332 ;
     RECT  31.415 47.196 32.315 47.682 ;
     RECT  32.279 49.176 32.315 50.418 ;
     RECT  32.279 52.02 32.315 52.776 ;
     RECT  32.287 53.64 32.315 54.126 ;
     RECT  31.379 55.962 32.315 56.358 ;
     RECT  31.379 57.996 32.315 58.554 ;
     RECT  32.279 61.128 32.315 61.146 ;
     RECT  31.343 62.748 32.315 62.766 ;
     RECT  32.251 66.636 32.351 66.654 ;
     RECT  31.343 68.076 32.351 68.094 ;
     RECT  30.24 9.396 32.387 9.414 ;
     RECT  32.315 53.64 32.387 53.658 ;
     RECT  32.315 56.196 32.387 56.214 ;
     RECT  32.287 64.026 32.387 64.044 ;
     RECT  30.299 69.696 32.387 69.714 ;
    LAYER M3 ;
     RECT  18.615 2.143 18.705 2.251 ;
     RECT  4.68 2.227 4.698 2.263 ;
     RECT  11.808 2.227 11.826 2.263 ;
     RECT  5.868 2.263 5.886 2.299 ;
     RECT  11.52 2.263 12.006 2.299 ;
     RECT  13.215 2.143 13.305 2.299 ;
     RECT  17.136 2.251 17.154 2.299 ;
     RECT  5.868 2.299 6.03 2.371 ;
     RECT  14.4 2.191 14.418 2.371 ;
     RECT  18.288 2.251 18.705 2.371 ;
     RECT  24.015 2.143 24.105 2.371 ;
     RECT  25.992 2.191 26.01 2.371 ;
     RECT  28.224 2.263 28.242 2.371 ;
     RECT  2.415 2.143 2.505 2.413 ;
     RECT  7.815 2.143 7.905 2.413 ;
     RECT  12.78 2.299 13.305 2.413 ;
     RECT  18.108 2.371 18.705 2.413 ;
     RECT  23.616 2.371 24.105 2.413 ;
     RECT  24.984 2.299 25.002 2.413 ;
     RECT  29.415 2.143 29.505 2.413 ;
     RECT  12.78 2.413 13.497 2.461 ;
     RECT  14.328 2.371 14.994 2.461 ;
     RECT  20.592 2.371 20.61 2.461 ;
     RECT  21.348 2.299 21.366 2.461 ;
     RECT  27.828 2.371 28.242 2.489 ;
     RECT  12.78 2.461 14.994 2.491 ;
     RECT  25.92 2.371 26.01 2.497 ;
     RECT  28.044 2.489 28.242 2.539 ;
     RECT  12.78 2.491 15.066 2.569 ;
     RECT  20.592 2.461 21.366 2.569 ;
     RECT  16.92 2.299 17.154 2.635 ;
     RECT  4.68 2.263 4.77 2.641 ;
     RECT  5.796 2.371 6.03 2.641 ;
     RECT  11.232 2.299 12.006 2.641 ;
     RECT  16.128 2.605 16.146 2.641 ;
     RECT  16.92 2.635 17.19 2.641 ;
     RECT  18.108 2.413 18.897 2.641 ;
     RECT  20.016 2.569 21.366 2.641 ;
     RECT  22.5 2.605 22.518 2.641 ;
     RECT  23.616 2.413 25.002 2.641 ;
     RECT  25.92 2.497 26.622 2.641 ;
     RECT  7.815 2.413 8.097 2.731 ;
     RECT  15.84 2.641 22.662 2.767 ;
     RECT  23.616 2.641 26.622 2.767 ;
     RECT  4.68 2.641 6.642 2.795 ;
     RECT  7.815 2.731 8.154 2.803 ;
     RECT  11.016 2.641 12.006 2.803 ;
     RECT  12.78 2.569 15.102 2.803 ;
     RECT  7.815 2.803 8.586 2.875 ;
     RECT  9.324 2.731 9.342 2.875 ;
     RECT  7.815 2.875 9.342 2.911 ;
     RECT  11.016 2.803 15.102 2.911 ;
     RECT  15.84 2.767 26.622 2.911 ;
     RECT  11.016 2.911 26.622 3.037 ;
     RECT  7.632 2.911 9.342 3.109 ;
     RECT  10.944 3.037 26.622 3.109 ;
     RECT  5.832 2.795 6.642 3.181 ;
     RECT  5.832 3.181 6.894 3.307 ;
     RECT  7.632 3.109 26.694 3.307 ;
     RECT  28.044 2.539 28.53 3.307 ;
     RECT  29.415 2.413 29.697 3.307 ;
     RECT  2.415 2.413 2.697 3.343 ;
     RECT  4.68 2.795 5.058 3.415 ;
     RECT  2.415 3.343 2.79 3.451 ;
     RECT  4.104 3.415 5.058 3.451 ;
     RECT  2.415 3.451 5.058 3.605 ;
     RECT  4.68 3.605 5.058 3.685 ;
     RECT  5.832 3.307 26.694 3.685 ;
     RECT  4.68 3.685 27.09 3.749 ;
     RECT  2.415 3.605 3.834 3.811 ;
     RECT  4.68 3.749 10.242 3.821 ;
     RECT  2.376 3.811 3.834 3.869 ;
     RECT  11.016 3.749 27.09 3.931 ;
     RECT  28.044 3.307 29.697 3.931 ;
     RECT  2.415 3.869 3.834 4.531 ;
     RECT  4.752 3.821 10.242 4.531 ;
     RECT  11.016 3.931 29.697 4.531 ;
     RECT  4.752 4.531 29.697 4.685 ;
     RECT  2.415 4.531 3.87 4.919 ;
     RECT  4.752 4.685 27.918 5.099 ;
     RECT  2.415 4.919 3.654 5.459 ;
     RECT  2.415 5.459 3.51 5.495 ;
     RECT  4.752 5.099 4.77 5.575 ;
     RECT  5.58 5.099 27.918 5.611 ;
     RECT  28.728 4.685 29.697 5.611 ;
     RECT  4.464 5.575 4.77 5.881 ;
     RECT  5.58 5.611 29.697 5.881 ;
     RECT  4.284 5.881 29.697 5.999 ;
     RECT  2.415 5.495 3.438 6.421 ;
     RECT  4.464 5.999 29.697 6.781 ;
     RECT  2.415 6.421 3.69 6.845 ;
     RECT  4.464 6.781 30.006 6.845 ;
     RECT  3.456 6.845 3.69 6.961 ;
     RECT  3.456 6.961 3.762 7.079 ;
     RECT  4.572 6.845 30.006 7.115 ;
     RECT  4.608 7.115 30.006 7.231 ;
     RECT  4.608 7.231 30.042 7.393 ;
     RECT  4.608 7.393 30.474 7.421 ;
     RECT  2.415 6.845 2.697 8.155 ;
     RECT  3.456 7.079 3.654 8.155 ;
     RECT  2.415 8.155 3.654 8.167 ;
     RECT  2.376 8.167 3.762 8.311 ;
     RECT  4.752 7.421 30.474 8.311 ;
     RECT  2.376 8.311 30.474 8.429 ;
     RECT  2.415 8.429 30.474 9.509 ;
     RECT  2.415 9.509 3.906 10.399 ;
     RECT  4.644 9.509 30.474 10.399 ;
     RECT  2.415 10.399 30.474 10.471 ;
     RECT  31.464 11.821 31.482 11.947 ;
     RECT  32.364 9.391 32.382 12.907 ;
     RECT  32.292 12.907 32.382 12.941 ;
     RECT  2.415 10.471 30.546 13.291 ;
     RECT  2.412 13.291 30.546 13.325 ;
     RECT  31.356 11.947 31.482 13.387 ;
     RECT  2.415 13.325 30.546 13.801 ;
     RECT  31.32 13.387 31.482 13.801 ;
     RECT  2.415 13.801 31.482 13.805 ;
     RECT  2.415 13.805 31.41 14.861 ;
     RECT  32.292 12.941 32.31 14.917 ;
     RECT  32.22 14.917 32.31 15.151 ;
     RECT  32.184 15.151 32.31 15.437 ;
     RECT  32.184 15.437 32.274 15.533 ;
     RECT  32.184 15.533 32.238 16.301 ;
     RECT  2.415 14.861 31.374 16.771 ;
     RECT  32.292 16.501 32.31 16.877 ;
     RECT  2.415 16.771 31.41 17.581 ;
     RECT  2.415 17.581 31.446 17.887 ;
     RECT  2.376 17.887 31.446 17.995 ;
     RECT  32.292 18.187 32.31 18.221 ;
     RECT  0.036 18.157 0.054 18.535 ;
     RECT  2.304 17.995 31.446 18.605 ;
     RECT  2.304 18.605 31.338 18.959 ;
     RECT  0.036 18.535 0.09 19.075 ;
     RECT  2.304 18.959 30.798 19.849 ;
     RECT  0.036 19.075 0.558 19.949 ;
     RECT  1.404 17.077 1.422 20.141 ;
     RECT  0.036 19.949 0.522 20.309 ;
     RECT  2.304 19.849 30.834 20.317 ;
     RECT  2.304 20.317 31.41 20.429 ;
     RECT  31.356 20.429 31.41 20.717 ;
     RECT  0.072 20.309 0.522 20.965 ;
     RECT  32.292 20.971 32.31 21.119 ;
     RECT  2.304 20.429 30.258 21.235 ;
     RECT  31.356 20.717 31.374 21.235 ;
     RECT  0.072 20.965 0.558 21.263 ;
     RECT  2.304 21.235 31.374 21.695 ;
     RECT  2.34 21.695 31.374 21.773 ;
     RECT  0.108 21.263 0.558 22.253 ;
     RECT  31.32 21.773 31.374 22.351 ;
     RECT  2.34 21.773 30.258 22.477 ;
     RECT  2.304 22.477 30.258 22.549 ;
     RECT  31.32 22.351 31.41 22.549 ;
     RECT  2.304 22.549 31.41 22.637 ;
     RECT  2.34 22.637 31.41 22.649 ;
     RECT  30.78 22.649 31.41 22.711 ;
     RECT  30.78 22.711 31.446 22.733 ;
     RECT  0.108 22.253 0.198 22.987 ;
     RECT  2.34 22.649 29.97 23.021 ;
     RECT  0.108 22.987 0.342 23.117 ;
     RECT  2.34 23.021 29.934 23.117 ;
     RECT  31.32 22.733 31.446 23.279 ;
     RECT  0.108 23.117 0.198 23.405 ;
     RECT  31.356 23.279 31.446 23.405 ;
     RECT  32.292 22.207 32.31 23.563 ;
     RECT  2.34 23.117 29.898 23.659 ;
     RECT  32.256 23.563 32.31 23.659 ;
     RECT  2.304 23.659 29.898 23.665 ;
     RECT  2.268 23.665 29.898 23.789 ;
     RECT  32.112 23.659 32.31 23.885 ;
     RECT  32.256 23.885 32.31 24.089 ;
     RECT  2.304 23.789 29.898 24.169 ;
     RECT  0.54 23.899 0.558 24.269 ;
     RECT  32.292 24.089 32.31 24.269 ;
     RECT  2.304 24.169 30.042 24.475 ;
     RECT  2.304 24.475 30.114 24.601 ;
     RECT  31.356 23.405 31.374 24.601 ;
     RECT  2.304 24.601 31.374 24.653 ;
     RECT  2.304 24.653 30.294 25.387 ;
     RECT  31.32 24.653 31.374 25.519 ;
     RECT  2.268 25.387 30.294 25.579 ;
     RECT  31.32 25.519 31.446 25.579 ;
     RECT  2.268 25.579 31.446 25.717 ;
     RECT  2.232 25.717 31.446 25.901 ;
     RECT  0.18 26.023 0.198 26.095 ;
     RECT  2.304 25.901 31.41 26.285 ;
     RECT  0.108 26.095 0.198 26.527 ;
     RECT  1.332 24.139 1.35 26.627 ;
     RECT  2.34 26.285 31.41 27.019 ;
     RECT  0.108 26.527 0.234 27.139 ;
     RECT  32.22 26.875 32.238 27.211 ;
     RECT  32.22 27.211 32.31 27.239 ;
     RECT  32.256 27.239 32.31 27.707 ;
     RECT  2.304 27.019 31.41 27.751 ;
     RECT  32.292 27.707 32.31 27.869 ;
     RECT  2.304 27.751 31.446 28.021 ;
     RECT  2.268 28.021 31.446 28.109 ;
     RECT  0.108 27.139 0.558 28.205 ;
     RECT  2.268 28.109 31.41 28.493 ;
     RECT  2.304 28.493 31.41 28.589 ;
     RECT  0.18 28.205 0.558 28.781 ;
     RECT  0.18 28.781 0.342 29.261 ;
     RECT  0.18 29.261 0.198 29.453 ;
     RECT  2.304 28.589 31.374 29.707 ;
     RECT  0.108 29.605 0.126 29.837 ;
     RECT  32.292 28.843 32.31 30.181 ;
     RECT  2.268 29.707 31.374 30.235 ;
     RECT  0.144 30.235 0.162 30.283 ;
     RECT  2.232 30.235 31.374 30.407 ;
     RECT  0.144 30.283 0.342 30.413 ;
     RECT  2.304 30.407 31.374 30.685 ;
     RECT  2.304 30.685 31.41 30.763 ;
     RECT  32.22 30.181 32.31 30.763 ;
     RECT  2.304 30.763 32.31 30.893 ;
     RECT  0.18 30.413 0.342 30.955 ;
     RECT  0.18 30.955 0.378 31.225 ;
     RECT  2.304 30.893 31.41 31.243 ;
     RECT  32.292 30.893 32.31 31.289 ;
     RECT  2.268 31.243 31.41 31.487 ;
     RECT  2.304 31.487 31.41 31.559 ;
     RECT  0.108 31.225 0.378 31.891 ;
     RECT  2.304 31.559 30.006 32.233 ;
     RECT  2.268 32.233 30.006 32.467 ;
     RECT  30.78 31.559 31.41 32.539 ;
     RECT  2.232 32.467 30.006 32.567 ;
     RECT  2.268 32.567 30.006 32.683 ;
     RECT  30.744 32.539 31.41 32.683 ;
     RECT  32.292 32.491 32.31 32.779 ;
     RECT  2.268 32.683 31.41 33.197 ;
     RECT  0.108 31.891 0.558 33.293 ;
     RECT  2.268 33.197 31.374 33.485 ;
     RECT  32.184 32.779 32.31 34.027 ;
     RECT  32.112 34.027 32.31 34.157 ;
     RECT  0.108 33.293 0.486 34.159 ;
     RECT  2.304 33.485 30.834 34.315 ;
     RECT  2.304 34.315 31.338 34.465 ;
     RECT  2.304 34.465 31.374 34.637 ;
     RECT  0.108 34.159 0.558 34.829 ;
     RECT  32.184 34.157 32.31 34.891 ;
     RECT  0.144 34.829 0.558 34.925 ;
     RECT  0.54 34.925 0.558 35.021 ;
     RECT  32.112 34.891 32.31 35.213 ;
     RECT  2.304 34.637 30.726 35.401 ;
     RECT  32.22 35.213 32.31 35.453 ;
     RECT  2.304 35.401 30.762 35.467 ;
     RECT  2.304 35.467 31.338 35.815 ;
     RECT  2.304 35.815 31.374 35.851 ;
     RECT  32.256 35.453 32.31 36.041 ;
     RECT  2.268 35.851 31.374 36.049 ;
     RECT  32.256 36.041 32.274 36.239 ;
     RECT  2.268 36.049 31.41 36.557 ;
     RECT  2.268 36.557 30.366 37.049 ;
     RECT  32.22 36.859 32.238 37.099 ;
     RECT  32.22 37.099 32.31 37.229 ;
     RECT  31.284 36.557 31.41 37.325 ;
     RECT  21.42 37.049 30.366 37.363 ;
     RECT  31.284 37.325 31.374 37.363 ;
     RECT  2.268 37.049 20.682 37.427 ;
     RECT  0.144 37.435 0.162 37.483 ;
     RECT  32.22 37.229 32.238 37.517 ;
     RECT  0.144 37.483 0.342 37.597 ;
     RECT  21.42 37.363 31.374 37.613 ;
     RECT  0.108 37.597 0.342 37.709 ;
     RECT  0.144 37.709 0.342 38.173 ;
     RECT  2.304 37.427 20.682 38.173 ;
     RECT  21.42 37.613 30.366 38.173 ;
     RECT  0.144 38.173 0.522 38.285 ;
     RECT  31.14 37.613 31.374 38.285 ;
     RECT  2.304 38.173 30.366 38.347 ;
     RECT  2.268 38.347 30.366 38.507 ;
     RECT  0.504 38.285 0.522 38.677 ;
     RECT  2.304 38.507 30.366 39.091 ;
     RECT  31.14 38.285 31.338 39.091 ;
     RECT  0.504 38.677 0.558 39.163 ;
     RECT  0.144 39.163 0.558 39.245 ;
     RECT  2.304 39.091 31.338 39.289 ;
     RECT  0.144 39.245 0.414 39.677 ;
     RECT  2.304 39.289 31.374 39.749 ;
     RECT  0.144 39.677 0.198 39.773 ;
     RECT  2.304 39.749 21.978 39.785 ;
     RECT  0.144 39.773 0.162 40.157 ;
     RECT  2.304 39.785 21.942 40.459 ;
     RECT  2.268 40.459 21.942 40.531 ;
     RECT  22.788 39.749 31.374 40.531 ;
     RECT  2.268 40.531 31.374 40.603 ;
     RECT  2.268 40.603 31.41 40.667 ;
     RECT  2.304 40.667 31.41 40.877 ;
     RECT  32.292 41.035 32.31 41.275 ;
     RECT  20.772 40.877 31.41 41.323 ;
     RECT  32.184 41.275 32.31 41.323 ;
     RECT  0.144 41.227 0.162 41.405 ;
     RECT  20.772 41.323 32.31 41.453 ;
     RECT  2.304 40.877 19.674 41.477 ;
     RECT  2.304 41.477 19.098 41.515 ;
     RECT  19.872 41.611 19.89 41.647 ;
     RECT  19.872 41.647 19.926 41.755 ;
     RECT  19.872 41.755 20.034 41.791 ;
     RECT  20.772 41.453 31.482 41.791 ;
     RECT  2.268 41.515 19.098 41.909 ;
     RECT  2.268 41.909 12.402 41.945 ;
     RECT  0.324 41.755 0.558 42.125 ;
     RECT  19.872 41.791 31.482 42.215 ;
     RECT  22.5 42.215 31.482 42.287 ;
     RECT  19.872 42.215 21.762 42.359 ;
     RECT  32.292 41.453 32.31 42.509 ;
     RECT  13.176 41.909 19.098 42.601 ;
     RECT  22.788 42.287 31.482 42.605 ;
     RECT  20.268 42.359 20.61 42.653 ;
     RECT  20.304 42.653 20.61 42.719 ;
     RECT  2.304 41.945 12.402 42.727 ;
     RECT  13.176 42.601 19.53 42.727 ;
     RECT  0.54 42.125 0.558 42.797 ;
     RECT  2.304 42.727 19.53 42.997 ;
     RECT  20.412 42.719 20.61 43.141 ;
     RECT  21.384 42.359 21.762 43.141 ;
     RECT  20.412 43.141 21.762 43.259 ;
     RECT  2.232 42.997 19.53 43.277 ;
     RECT  2.268 43.277 19.53 43.303 ;
     RECT  20.484 43.259 21.762 43.339 ;
     RECT  22.788 42.605 31.338 43.339 ;
     RECT  32.292 43.339 32.31 43.439 ;
     RECT  20.484 43.339 31.338 43.501 ;
     RECT  2.268 43.303 19.566 43.529 ;
     RECT  10.8 43.529 19.566 43.799 ;
     RECT  32.22 43.723 32.238 43.901 ;
     RECT  10.836 43.799 19.566 43.915 ;
     RECT  2.268 43.529 10.062 44.059 ;
     RECT  2.196 44.059 10.062 44.069 ;
     RECT  2.196 44.069 9.954 44.237 ;
     RECT  10.836 43.915 19.674 44.311 ;
     RECT  10.836 44.311 19.746 44.383 ;
     RECT  20.484 43.501 31.41 44.383 ;
     RECT  10.836 44.383 31.41 44.621 ;
     RECT  2.268 44.237 9.954 44.879 ;
     RECT  9.144 44.879 9.954 44.959 ;
     RECT  10.836 44.621 31.374 44.959 ;
     RECT  2.268 44.879 8.154 45.149 ;
     RECT  2.268 45.149 7.002 45.185 ;
     RECT  9.144 44.959 31.374 45.197 ;
     RECT  7.815 45.149 8.154 45.341 ;
     RECT  10.692 45.197 31.374 45.389 ;
     RECT  10.692 45.389 31.338 45.689 ;
     RECT  9.144 45.197 9.738 45.931 ;
     RECT  10.692 45.689 10.818 45.931 ;
     RECT  9.144 45.931 10.818 46.031 ;
     RECT  32.112 45.739 32.31 46.061 ;
     RECT  0.144 45.967 0.162 46.075 ;
     RECT  2.304 45.185 7.002 46.075 ;
     RECT  11.556 45.689 31.338 46.103 ;
     RECT  7.815 45.341 8.097 46.201 ;
     RECT  9.144 46.031 10.494 46.201 ;
     RECT  11.952 46.103 31.338 46.265 ;
     RECT  2.304 46.075 7.038 46.315 ;
     RECT  7.815 46.201 10.494 46.315 ;
     RECT  32.292 46.061 32.31 46.337 ;
     RECT  0.108 46.075 0.162 46.541 ;
     RECT  2.304 46.315 10.494 46.841 ;
     RECT  9.9 46.841 10.494 46.843 ;
     RECT  11.952 46.265 21.978 46.843 ;
     RECT  22.824 46.265 31.338 46.885 ;
     RECT  2.304 46.841 9.126 46.987 ;
     RECT  11.592 46.843 21.978 47.083 ;
     RECT  22.824 46.885 31.374 47.083 ;
     RECT  32.22 46.843 32.238 47.083 ;
     RECT  9.9 46.843 10.674 47.191 ;
     RECT  11.484 47.083 21.978 47.191 ;
     RECT  22.824 47.083 31.41 47.191 ;
     RECT  9.9 47.191 31.41 47.425 ;
     RECT  2.268 46.987 9.126 47.453 ;
     RECT  9.9 47.425 31.446 47.467 ;
     RECT  32.22 47.083 32.31 47.467 ;
     RECT  8.928 47.453 9.126 47.659 ;
     RECT  9.9 47.467 32.31 47.659 ;
     RECT  8.928 47.659 32.31 47.687 ;
     RECT  0.144 46.541 0.162 47.731 ;
     RECT  0.144 47.731 0.558 47.857 ;
     RECT  2.268 47.453 8.097 47.857 ;
     RECT  2.232 47.857 8.097 47.957 ;
     RECT  2.304 47.957 8.097 48.271 ;
     RECT  8.928 47.687 32.13 48.271 ;
     RECT  2.304 48.271 32.13 48.461 ;
     RECT  2.304 48.461 31.41 48.845 ;
     RECT  0.108 47.857 0.558 48.901 ;
     RECT  0.108 48.901 1.17 48.973 ;
     RECT  2.304 48.845 31.338 49.001 ;
     RECT  0.108 48.973 1.242 49.037 ;
     RECT  32.22 49.003 32.238 49.099 ;
     RECT  0.108 49.037 1.134 49.133 ;
     RECT  0.144 49.133 1.134 49.181 ;
     RECT  32.22 49.099 32.31 49.181 ;
     RECT  12.096 49.001 30.366 49.199 ;
     RECT  2.304 49.001 11.322 49.505 ;
     RECT  0.144 49.181 0.558 49.517 ;
     RECT  0.18 49.517 0.558 49.613 ;
     RECT  31.284 49.001 31.338 49.621 ;
     RECT  2.304 49.505 11.25 49.675 ;
     RECT  31.284 49.621 31.374 49.709 ;
     RECT  0.18 49.613 0.198 49.805 ;
     RECT  12.204 49.199 30.366 49.819 ;
     RECT  31.284 49.709 31.338 49.819 ;
     RECT  32.292 49.181 32.31 50.059 ;
     RECT  12.204 49.819 31.338 50.155 ;
     RECT  2.268 49.675 11.25 50.287 ;
     RECT  12.06 50.155 31.338 50.287 ;
     RECT  32.256 50.059 32.31 50.423 ;
     RECT  32.256 50.423 32.274 50.443 ;
     RECT  32.22 50.443 32.274 50.621 ;
     RECT  2.268 50.287 31.338 50.657 ;
     RECT  0.324 50.731 0.342 50.827 ;
     RECT  0.108 50.827 0.342 50.927 ;
     RECT  0.144 50.927 0.342 51.133 ;
     RECT  0.144 51.133 0.378 51.161 ;
     RECT  0.18 51.161 0.378 51.205 ;
     RECT  0.18 51.205 0.558 51.293 ;
     RECT  32.22 50.621 32.238 51.595 ;
     RECT  32.184 51.595 32.238 51.601 ;
     RECT  32.112 51.601 32.274 51.677 ;
     RECT  0.468 51.293 0.558 51.691 ;
     RECT  0.468 51.691 0.594 51.725 ;
     RECT  32.184 51.677 32.274 51.737 ;
     RECT  2.304 50.657 31.338 51.773 ;
     RECT  0.504 51.725 0.594 51.821 ;
     RECT  0.504 51.821 0.558 51.917 ;
     RECT  32.22 51.737 32.274 51.979 ;
     RECT  0.54 51.917 0.558 52.301 ;
     RECT  2.304 51.773 8.946 52.439 ;
     RECT  9.684 51.773 31.338 52.709 ;
     RECT  32.22 51.979 32.31 52.781 ;
     RECT  2.304 52.439 8.097 52.825 ;
     RECT  0.216 52.753 0.234 52.843 ;
     RECT  8.928 52.439 8.946 52.951 ;
     RECT  0.144 52.843 0.234 53.021 ;
     RECT  0.216 53.021 0.234 53.069 ;
     RECT  2.268 52.825 8.097 53.275 ;
     RECT  9.9 52.709 31.338 53.329 ;
     RECT  2.088 53.275 8.097 53.453 ;
     RECT  8.928 52.951 9.054 53.527 ;
     RECT  2.304 53.453 8.097 53.563 ;
     RECT  8.82 53.527 9.054 53.563 ;
     RECT  32.22 52.781 32.238 53.611 ;
     RECT  9.9 53.329 31.374 53.635 ;
     RECT  32.112 53.611 32.31 53.635 ;
     RECT  32.112 53.635 32.382 53.741 ;
     RECT  2.304 53.563 9.054 53.899 ;
     RECT  9.828 53.635 31.374 53.899 ;
     RECT  0.54 53.527 0.558 53.905 ;
     RECT  0.504 53.905 0.558 53.995 ;
     RECT  0.324 53.995 0.558 54.125 ;
     RECT  2.304 53.899 31.374 54.317 ;
     RECT  32.256 53.741 32.382 54.329 ;
     RECT  2.304 54.317 31.338 54.427 ;
     RECT  2.232 54.427 31.338 54.605 ;
     RECT  2.304 54.605 31.338 55.111 ;
     RECT  0.504 54.125 0.558 55.373 ;
     RECT  2.304 55.111 31.374 55.373 ;
     RECT  32.364 54.329 32.382 55.627 ;
     RECT  2.304 55.373 31.338 55.957 ;
     RECT  0.54 55.373 0.558 56.107 ;
     RECT  32.292 55.627 32.382 56.219 ;
     RECT  0.144 56.107 0.558 56.285 ;
     RECT  2.232 55.957 31.338 56.429 ;
     RECT  2.268 56.429 31.338 56.597 ;
     RECT  2.304 56.597 31.338 56.803 ;
     RECT  2.304 56.803 31.374 57.293 ;
     RECT  0.324 56.285 0.558 57.307 ;
     RECT  2.304 57.293 31.338 58.603 ;
     RECT  0.18 57.307 0.558 58.657 ;
     RECT  0.108 58.657 0.558 58.733 ;
     RECT  2.268 58.603 31.338 58.963 ;
     RECT  0.144 58.733 0.558 59.309 ;
     RECT  2.268 58.963 31.374 60.077 ;
     RECT  0.144 59.309 0.342 60.173 ;
     RECT  32.292 56.219 32.31 60.331 ;
     RECT  0.144 60.173 0.27 60.385 ;
     RECT  0.108 60.385 0.27 60.557 ;
     RECT  2.304 60.077 31.374 60.557 ;
     RECT  32.256 60.331 32.31 60.619 ;
     RECT  0.252 60.557 0.27 61.003 ;
     RECT  0.252 61.003 0.342 61.195 ;
     RECT  2.304 60.557 31.338 61.291 ;
     RECT  2.232 61.291 31.338 61.655 ;
     RECT  0.252 61.195 0.558 61.771 ;
     RECT  32.22 60.619 32.31 61.889 ;
     RECT  0.144 61.771 0.558 61.949 ;
     RECT  0.54 61.949 0.558 62.189 ;
     RECT  2.268 61.655 31.338 62.537 ;
     RECT  32.292 61.889 32.31 62.771 ;
     RECT  0.144 62.971 0.162 63.149 ;
     RECT  0.54 63.247 0.558 63.341 ;
     RECT  2.304 62.537 31.338 63.691 ;
     RECT  32.256 63.787 32.274 63.979 ;
     RECT  32.256 63.979 32.31 64.021 ;
     RECT  2.268 63.691 31.338 64.085 ;
     RECT  0.108 64.267 0.126 64.397 ;
     RECT  2.304 64.085 31.338 65.245 ;
     RECT  0.108 65.407 0.126 65.479 ;
     RECT  0.108 65.479 0.162 65.677 ;
     RECT  0.108 65.677 0.198 65.741 ;
     RECT  0.144 65.741 0.198 65.749 ;
     RECT  0.144 65.749 0.558 65.837 ;
     RECT  2.268 65.245 31.338 65.933 ;
     RECT  0.18 65.837 0.558 66.221 ;
     RECT  32.256 64.021 32.382 66.659 ;
     RECT  2.304 65.933 31.338 66.749 ;
     RECT  0.18 66.221 0.198 66.865 ;
     RECT  0.108 66.865 0.198 66.955 ;
     RECT  0.108 66.955 0.342 67.085 ;
     RECT  0.108 67.085 0.126 67.469 ;
     RECT  31.32 66.749 31.338 67.559 ;
     RECT  32.328 66.659 32.382 68.099 ;
     RECT  0.108 68.377 0.126 68.429 ;
     RECT  2.304 66.749 30.474 68.683 ;
     RECT  1.728 68.683 30.474 68.909 ;
     RECT  0.144 69.067 0.162 69.245 ;
     RECT  1.728 68.909 30.366 69.547 ;
     RECT  32.364 68.099 32.382 69.719 ;
     RECT  1.476 69.547 30.366 70.027 ;
     RECT  0.108 70.069 0.126 70.219 ;
     RECT  0.108 70.219 0.342 70.349 ;
     RECT  0.144 70.349 0.162 70.589 ;
     RECT  1.404 70.027 30.366 70.699 ;
     RECT  1.152 70.699 30.366 72.989 ;
     RECT  1.152 72.989 14.49 72.995 ;
     RECT  1.188 72.995 14.49 73.265 ;
     RECT  1.404 73.265 14.49 73.805 ;
     RECT  1.764 73.805 14.49 73.877 ;
     RECT  2.016 73.877 14.49 74.047 ;
     RECT  15.228 72.989 30.366 74.047 ;
     RECT  2.016 74.047 30.366 74.075 ;
     RECT  2.415 74.075 30.366 74.111 ;
     RECT  3.564 74.111 30.366 74.345 ;
     RECT  2.415 74.111 2.826 74.525 ;
     RECT  3.564 74.345 28.566 75.271 ;
     RECT  29.415 74.345 30.366 75.271 ;
     RECT  2.415 74.525 2.697 75.505 ;
     RECT  3.456 75.271 28.566 75.505 ;
     RECT  2.415 75.505 28.566 75.929 ;
     RECT  29.376 75.271 30.366 75.929 ;
     RECT  25.812 75.929 28.566 76.009 ;
     RECT  29.376 75.929 30.006 76.009 ;
     RECT  2.415 75.929 25.074 76.747 ;
     RECT  2.376 76.747 25.074 76.843 ;
     RECT  25.812 76.009 30.006 76.843 ;
     RECT  2.376 76.843 30.006 76.855 ;
     RECT  2.376 76.855 30.114 77.009 ;
     RECT  2.415 77.009 29.754 77.351 ;
     RECT  2.415 77.351 29.697 77.827 ;
     RECT  2.376 77.827 29.697 77.855 ;
     RECT  2.376 77.855 2.697 78.907 ;
     RECT  3.42 77.855 29.697 78.907 ;
     RECT  2.376 78.907 29.697 79.169 ;
     RECT  2.415 79.169 29.697 79.439 ;
     RECT  2.415 79.439 28.494 79.709 ;
     RECT  2.415 79.709 28.278 79.745 ;
     RECT  2.415 79.745 28.134 79.817 ;
     RECT  26.244 79.817 28.134 79.979 ;
     RECT  2.415 79.817 25.47 80.015 ;
     RECT  2.415 80.015 9.45 80.249 ;
     RECT  11.952 80.015 25.47 80.249 ;
     RECT  26.244 79.979 28.062 80.249 ;
     RECT  2.415 80.249 9.198 80.285 ;
     RECT  10.26 80.015 11.214 80.285 ;
     RECT  26.244 80.249 27.918 80.429 ;
     RECT  22.356 80.249 25.434 80.519 ;
     RECT  2.415 80.285 8.838 80.555 ;
     RECT  26.46 80.429 27.918 80.591 ;
     RECT  2.415 80.555 8.55 80.789 ;
     RECT  26.46 80.591 27.594 80.789 ;
     RECT  26.532 80.789 27.09 80.825 ;
     RECT  22.608 80.519 25.434 80.861 ;
     RECT  10.296 80.285 11.214 80.923 ;
     RECT  11.952 80.249 21.582 80.923 ;
     RECT  2.415 80.789 3.006 80.957 ;
     RECT  10.296 80.923 21.582 81.059 ;
     RECT  26.64 80.825 27.09 81.059 ;
     RECT  10.296 81.059 16.182 81.101 ;
     RECT  9.432 81.019 9.45 81.175 ;
     RECT  10.296 81.101 16.002 81.175 ;
     RECT  22.644 80.861 25.434 81.175 ;
     RECT  22.644 81.175 25.614 81.211 ;
     RECT  4.14 80.789 8.55 81.239 ;
     RECT  16.992 81.059 21.582 81.307 ;
     RECT  4.14 81.239 8.37 81.329 ;
     RECT  9.432 81.175 16.002 81.329 ;
     RECT  22.644 81.211 25.65 81.329 ;
     RECT  4.14 81.329 6.966 81.365 ;
     RECT  16.992 81.307 21.69 81.401 ;
     RECT  16.992 81.401 20.034 81.437 ;
     RECT  22.644 81.329 25.614 81.437 ;
     RECT  4.752 81.365 6.966 81.473 ;
     RECT  7.815 81.329 8.37 81.473 ;
     RECT  9.432 81.329 11.43 81.481 ;
     RECT  18.396 81.437 20.034 81.599 ;
     RECT  20.808 81.401 21.69 81.599 ;
     RECT  22.644 81.437 25.506 81.599 ;
     RECT  26.64 81.059 26.874 81.599 ;
     RECT  9.144 81.481 11.43 81.635 ;
     RECT  12.276 81.329 16.002 81.635 ;
     RECT  16.992 81.437 17.586 81.635 ;
     RECT  22.644 81.599 22.662 81.635 ;
     RECT  23.508 81.599 25.362 81.635 ;
     RECT  26.64 81.599 26.658 81.635 ;
     RECT  19.656 81.599 20.034 81.671 ;
     RECT  23.508 81.635 25.29 81.707 ;
     RECT  2.415 80.957 2.697 81.827 ;
     RECT  7.815 81.473 8.097 81.827 ;
     RECT  18.396 81.599 18.897 81.827 ;
     RECT  29.415 79.439 29.697 81.827 ;
     RECT  5.22 81.473 6.966 81.869 ;
     RECT  9.612 81.635 11.43 81.869 ;
     RECT  17.424 81.635 17.586 81.869 ;
     RECT  19.728 81.671 20.034 81.869 ;
     RECT  21.204 81.599 21.69 81.869 ;
     RECT  24.015 81.707 25.29 81.869 ;
     RECT  5.22 81.869 5.382 81.905 ;
     RECT  6.372 81.869 6.75 81.905 ;
     RECT  12.276 81.635 15.714 81.905 ;
     RECT  19.836 81.869 19.854 81.905 ;
     RECT  21.204 81.869 21.474 81.905 ;
     RECT  24.015 81.869 24.354 81.905 ;
     RECT  14.04 81.905 14.814 81.941 ;
     RECT  10.836 81.869 11.214 81.977 ;
     RECT  14.112 81.941 14.814 81.977 ;
     RECT  5.364 81.905 5.382 82.013 ;
     RECT  9.648 81.869 9.666 82.013 ;
     RECT  11.052 81.977 11.214 82.013 ;
     RECT  12.276 81.905 12.294 82.013 ;
     RECT  11.196 82.013 11.214 82.049 ;
     RECT  14.796 81.977 14.814 82.049 ;
     RECT  17.568 81.869 17.586 82.049 ;
     RECT  18.396 81.827 18.705 82.049 ;
     RECT  2.415 81.827 2.505 82.097 ;
     RECT  7.815 81.827 7.905 82.097 ;
     RECT  13.215 81.905 13.305 82.097 ;
     RECT  18.615 82.049 18.705 82.097 ;
     RECT  24.015 81.905 24.105 82.097 ;
     RECT  29.415 81.827 29.505 82.097 ;
    LAYER M4 ;
     RECT  2.365 3.84 2.408 3.864 ;
     RECT  2.401 13.296 2.408 13.32 ;
     RECT  0.06 19.824 2.408 71.208 ;
     RECT  2.408 2.148 2.512 82.092 ;
     RECT  2.512 2.418 2.704 81.822 ;
     RECT  2.704 48.432 2.765 71.352 ;
     RECT  2.704 3.36 2.819 5.736 ;
     RECT  2.704 6.816 2.819 10.872 ;
     RECT  2.704 12 2.837 27.912 ;
     RECT  2.765 48.432 2.837 48.456 ;
     RECT  2.765 50.064 2.837 71.352 ;
     RECT  2.704 74.496 2.837 74.52 ;
     RECT  2.837 50.16 2.867 71.352 ;
     RECT  2.819 3.792 2.873 5.736 ;
     RECT  2.704 46.032 2.873 47.352 ;
     RECT  2.867 50.16 2.873 59.208 ;
     RECT  2.867 60.192 3.059 71.352 ;
     RECT  2.873 3.792 3.107 5.688 ;
     RECT  2.873 50.16 3.125 53.784 ;
     RECT  2.837 12 3.155 27.048 ;
     RECT  3.155 14.592 3.299 27.048 ;
     RECT  2.819 6.816 3.305 6.84 ;
     RECT  3.299 19.344 3.443 27.048 ;
     RECT  2.704 77.52 3.491 79.032 ;
     RECT  2.704 80.352 3.557 80.952 ;
     RECT  3.107 3.792 3.635 5.16 ;
     RECT  2.819 8.496 3.683 10.872 ;
     RECT  2.704 28.944 3.733 44.52 ;
     RECT  3.697 73.488 3.733 73.512 ;
     RECT  2.873 46.56 3.769 47.352 ;
     RECT  2.704 75.552 3.769 76.2 ;
     RECT  3.299 14.592 3.779 18.312 ;
     RECT  3.733 28.944 3.805 44.568 ;
     RECT  3.443 19.392 3.841 27.048 ;
     RECT  3.805 49.104 3.841 49.128 ;
     RECT  3.125 50.16 3.841 50.184 ;
     RECT  3.059 64.368 3.877 71.352 ;
     RECT  3.683 8.544 3.881 10.872 ;
     RECT  3.635 3.792 3.923 3.96 ;
     RECT  3.769 46.56 3.925 47.976 ;
     RECT  3.841 49.104 3.925 50.184 ;
     RECT  3.877 64.368 3.925 71.832 ;
     RECT  3.733 72.96 3.925 74.232 ;
     RECT  3.769 75.552 3.925 76.392 ;
     RECT  3.805 28.944 3.973 45.528 ;
     RECT  3.925 64.368 4.019 76.392 ;
     RECT  3.059 60.192 4.057 63 ;
     RECT  3.155 12 4.069 12.552 ;
     RECT  4.019 64.368 4.097 75.864 ;
     RECT  2.873 54.768 4.129 59.208 ;
     RECT  4.057 60.192 4.129 63.288 ;
     RECT  4.097 64.368 4.129 74.184 ;
     RECT  3.925 46.56 4.165 50.184 ;
     RECT  3.557 80.928 4.169 80.952 ;
     RECT  3.779 14.592 4.261 16.536 ;
     RECT  3.125 51.312 4.273 53.784 ;
     RECT  4.129 54.768 4.273 74.184 ;
     RECT  4.069 11.856 4.307 12.552 ;
     RECT  4.261 14.304 4.345 16.536 ;
     RECT  4.165 46.512 4.357 50.184 ;
     RECT  4.345 14.208 4.403 16.536 ;
     RECT  3.973 28.416 4.417 45.528 ;
     RECT  4.357 46.512 4.417 50.232 ;
     RECT  4.273 51.312 4.417 74.184 ;
     RECT  4.307 11.856 4.421 12.024 ;
     RECT  3.841 19.392 4.453 27.384 ;
     RECT  4.417 28.416 4.453 74.184 ;
     RECT  4.421 11.856 4.529 11.88 ;
     RECT  4.453 5.664 4.597 5.688 ;
     RECT  4.453 6.816 4.597 6.84 ;
     RECT  3.779 17.52 4.633 18.312 ;
     RECT  4.453 19.392 4.633 74.184 ;
     RECT  3.881 10.032 4.637 10.872 ;
     RECT  3.491 77.52 4.669 77.544 ;
     RECT  3.491 78.624 4.669 79.032 ;
     RECT  3.923 3.792 4.709 3.816 ;
     RECT  4.597 5.616 4.739 5.688 ;
     RECT  4.739 5.664 4.745 5.688 ;
     RECT  4.403 14.496 4.777 16.536 ;
     RECT  4.633 17.52 4.777 74.184 ;
     RECT  4.669 77.52 4.883 79.032 ;
     RECT  4.597 6.816 4.921 7.416 ;
     RECT  3.881 8.544 4.921 8.568 ;
     RECT  4.777 14.496 4.961 74.184 ;
     RECT  4.097 75.552 5.029 75.864 ;
     RECT  4.921 6.816 5.123 8.568 ;
     RECT  4.961 14.496 5.123 17.112 ;
     RECT  4.957 4.272 5.141 4.392 ;
     RECT  4.883 78.624 5.173 79.032 ;
     RECT  4.885 80.4 5.173 80.424 ;
     RECT  4.961 18.096 5.249 74.184 ;
     RECT  5.249 19.248 5.281 74.184 ;
     RECT  5.029 75.552 5.281 76.392 ;
     RECT  5.281 19.248 5.315 76.392 ;
     RECT  5.315 63.504 5.363 76.392 ;
     RECT  5.123 14.496 5.413 16.968 ;
     RECT  5.315 19.248 5.459 62.52 ;
     RECT  5.077 5.712 5.461 5.736 ;
     RECT  5.123 6.816 5.461 8.52 ;
     RECT  5.173 78.624 5.461 80.424 ;
     RECT  5.461 78.624 5.537 81.576 ;
     RECT  5.537 78.624 5.555 81.096 ;
     RECT  5.363 63.504 5.603 74.136 ;
     RECT  4.637 10.032 5.605 10.056 ;
     RECT  5.605 10.032 5.651 10.536 ;
     RECT  5.413 14.256 5.789 16.968 ;
     RECT  4.883 77.52 5.857 77.544 ;
     RECT  5.363 75.264 6.001 76.392 ;
     RECT  5.461 5.712 6.179 8.52 ;
     RECT  5.389 12.528 6.181 13.032 ;
     RECT  5.789 14.496 6.181 16.968 ;
     RECT  6.181 14.496 6.277 17.064 ;
     RECT  5.249 18.096 6.277 18.264 ;
     RECT  6.277 14.496 6.323 18.264 ;
     RECT  6.323 17.616 6.325 18.264 ;
     RECT  5.459 19.248 6.325 30.36 ;
     RECT  5.459 31.392 6.365 62.52 ;
     RECT  5.555 79.056 6.365 81.096 ;
     RECT  5.141 4.368 6.397 4.392 ;
     RECT  6.179 5.712 6.397 7.944 ;
     RECT  5.603 63.504 6.437 71.832 ;
     RECT  6.181 12.528 6.469 13.08 ;
     RECT  6.437 65.76 6.509 71.832 ;
     RECT  5.651 10.032 6.541 10.248 ;
     RECT  6.365 31.392 6.545 60.456 ;
     RECT  6.397 4.368 6.563 7.944 ;
     RECT  6.469 12.528 6.563 13.128 ;
     RECT  6.323 14.496 6.581 16.44 ;
     RECT  6.325 17.616 6.581 30.36 ;
     RECT  6.541 9.648 6.611 10.248 ;
     RECT  6.581 17.616 6.653 26.808 ;
     RECT  6.365 79.056 6.653 80.28 ;
     RECT  5.857 77.52 6.685 78.072 ;
     RECT  6.653 79.056 6.685 79.512 ;
     RECT  6.581 16.032 6.707 16.44 ;
     RECT  5.603 72.864 6.709 74.136 ;
     RECT  6.001 75.264 6.709 76.536 ;
     RECT  6.505 3.312 6.757 3.336 ;
     RECT  6.563 4.368 6.757 6.408 ;
     RECT  6.581 14.496 6.757 15.048 ;
     RECT  6.545 31.392 6.761 50.184 ;
     RECT  6.581 28.272 6.829 30.36 ;
     RECT  6.509 65.856 6.829 71.832 ;
     RECT  6.709 72.864 6.829 76.536 ;
     RECT  6.563 12.528 6.901 12.552 ;
     RECT  6.611 10.032 6.937 10.248 ;
     RECT  6.901 11.952 6.937 12.552 ;
     RECT  6.829 65.856 7.237 76.536 ;
     RECT  6.685 77.52 7.237 79.512 ;
     RECT  6.757 14.256 7.261 15.048 ;
     RECT  6.563 7.44 7.333 7.944 ;
     RECT  7.261 14.208 7.573 15.048 ;
     RECT  6.707 16.032 7.573 16.056 ;
     RECT  7.237 65.856 7.621 79.512 ;
     RECT  6.577 81.6 7.669 81.624 ;
     RECT  6.757 3.312 7.808 6.408 ;
     RECT  7.333 7.44 7.808 8.904 ;
     RECT  6.937 10.032 7.808 12.552 ;
     RECT  7.573 14.208 7.808 16.056 ;
     RECT  7.621 17.664 7.808 17.688 ;
     RECT  6.653 18.672 7.808 26.808 ;
     RECT  6.829 28.272 7.808 31.224 ;
     RECT  6.761 32.208 7.808 50.184 ;
     RECT  6.545 51.216 7.808 60.456 ;
     RECT  6.365 61.44 7.808 62.52 ;
     RECT  6.437 63.504 7.808 64.44 ;
     RECT  7.621 65.568 7.808 79.512 ;
     RECT  7.669 80.928 7.808 81.624 ;
     RECT  7.808 2.148 7.912 82.092 ;
     RECT  7.912 2.418 8.104 81.822 ;
     RECT  8.104 38.16 8.165 47.208 ;
     RECT  8.104 6.096 8.201 7.944 ;
     RECT  8.104 3.744 8.243 3.768 ;
     RECT  8.104 31.92 8.243 36.264 ;
     RECT  8.104 9.12 8.291 12.552 ;
     RECT  8.104 65.568 8.291 71.736 ;
     RECT  8.104 72.768 8.309 77.64 ;
     RECT  8.291 9.12 8.345 11.928 ;
     RECT  8.104 18.48 8.417 24.12 ;
     RECT  8.291 65.568 8.417 70.584 ;
     RECT  8.104 55.824 8.597 64.44 ;
     RECT  8.309 73.344 8.741 77.64 ;
     RECT  8.104 48.768 8.813 53.928 ;
     RECT  8.104 27.888 8.921 30.936 ;
     RECT  8.813 49.824 8.957 53.928 ;
     RECT  8.417 65.568 8.963 70.152 ;
     RECT  8.104 14.208 9.059 16.536 ;
     RECT  8.957 50.112 9.065 53.928 ;
     RECT  8.813 48.768 9.101 48.84 ;
     RECT  8.597 55.824 9.101 60.024 ;
     RECT  8.165 38.592 9.107 47.208 ;
     RECT  8.104 25.344 9.137 26.808 ;
     RECT  9.107 38.592 9.137 41.928 ;
     RECT  9.065 51.024 9.137 53.928 ;
     RECT  8.201 6.24 9.169 7.944 ;
     RECT  8.345 9.12 9.169 10.68 ;
     RECT  8.104 78.672 9.169 80.136 ;
     RECT  8.417 18.48 9.173 23.976 ;
     RECT  9.137 51.024 9.173 53.112 ;
     RECT  9.169 78.672 9.205 80.28 ;
     RECT  8.104 81.36 9.205 81.624 ;
     RECT  9.173 18.48 9.209 21.528 ;
     RECT  8.104 4.944 9.277 4.968 ;
     RECT  9.169 6.24 9.277 10.68 ;
     RECT  8.291 71.712 9.281 71.736 ;
     RECT  8.597 61.248 9.301 64.44 ;
     RECT  9.313 2.832 9.349 2.856 ;
     RECT  9.173 22.752 9.353 23.976 ;
     RECT  9.277 4.944 9.385 10.68 ;
     RECT  8.345 11.904 9.385 11.928 ;
     RECT  9.349 2.832 9.395 3.432 ;
     RECT  9.385 4.944 9.397 11.928 ;
     RECT  8.741 73.344 9.397 77.592 ;
     RECT  8.243 32.832 9.421 36.264 ;
     RECT  8.963 67.824 9.443 70.152 ;
     RECT  9.137 25.344 9.445 26.76 ;
     RECT  9.353 22.8 9.529 23.976 ;
     RECT  9.445 25.056 9.529 26.76 ;
     RECT  9.493 18 9.565 18.024 ;
     RECT  9.443 69.936 9.565 70.152 ;
     RECT  9.529 22.8 9.569 26.76 ;
     RECT  9.059 14.208 9.605 16.056 ;
     RECT  9.397 4.944 9.637 12.024 ;
     RECT  8.921 30.096 9.637 30.936 ;
     RECT  9.395 3.312 9.683 3.432 ;
     RECT  9.205 78.672 9.709 81.624 ;
     RECT  9.565 69.936 9.745 70.68 ;
     RECT  9.569 24.48 9.785 26.76 ;
     RECT  9.637 30.096 9.821 31.32 ;
     RECT  9.421 32.496 9.821 36.264 ;
     RECT  9.637 4.656 9.853 12.024 ;
     RECT  9.101 57.36 9.853 60.024 ;
     RECT  9.301 61.248 9.853 64.584 ;
     RECT  9.107 43.104 9.889 47.208 ;
     RECT  9.101 48.816 9.965 48.84 ;
     RECT  9.565 17.04 10.019 18.024 ;
     RECT  9.853 4.656 10.069 12.264 ;
     RECT  9.101 55.824 10.069 56.376 ;
     RECT  9.853 57.36 10.069 64.584 ;
     RECT  9.137 38.688 10.105 41.928 ;
     RECT  9.889 43.104 10.105 47.448 ;
     RECT  9.637 54.528 10.105 54.648 ;
     RECT  10.105 54.096 10.117 54.648 ;
     RECT  10.069 55.824 10.117 64.584 ;
     RECT  10.105 38.688 10.145 47.448 ;
     RECT  10.117 54.096 10.145 64.584 ;
     RECT  10.069 4.512 10.165 12.264 ;
     RECT  9.173 51.36 10.165 53.112 ;
     RECT  10.145 54.096 10.165 56.376 ;
     RECT  9.785 24.48 10.211 25.896 ;
     RECT  9.605 14.256 10.213 16.056 ;
     RECT  10.019 17.04 10.213 17.064 ;
     RECT  9.821 33.168 10.213 36.264 ;
     RECT  10.145 57.696 10.249 64.584 ;
     RECT  8.963 65.568 10.249 66.84 ;
     RECT  10.165 4.464 10.253 12.264 ;
     RECT  10.213 33.168 10.259 37.656 ;
     RECT  10.253 4.512 10.261 12.264 ;
     RECT  8.921 27.888 10.289 29.064 ;
     RECT  10.259 33.168 10.289 36.264 ;
     RECT  9.683 3.312 10.357 3.336 ;
     RECT  9.209 19.008 10.357 21.528 ;
     RECT  9.569 22.8 10.357 23.448 ;
     RECT  9.745 69.936 10.357 71.304 ;
     RECT  9.397 72.384 10.357 77.592 ;
     RECT  10.165 51.36 10.361 56.376 ;
     RECT  9.709 78.624 10.361 81.624 ;
     RECT  10.357 19.008 10.393 23.448 ;
     RECT  10.357 69.936 10.429 77.592 ;
     RECT  10.361 78.624 10.429 81.48 ;
     RECT  10.393 18.432 10.433 23.448 ;
     RECT  9.443 67.824 10.465 68.904 ;
     RECT  10.433 22.8 10.499 23.448 ;
     RECT  10.429 48.768 10.537 48.792 ;
     RECT  10.465 67.824 10.547 68.952 ;
     RECT  10.249 57.696 10.549 66.84 ;
     RECT  10.547 67.824 10.549 68.904 ;
     RECT  9.821 30.096 10.577 30.12 ;
     RECT  10.549 57.696 10.595 68.904 ;
     RECT  10.429 69.936 10.649 81.48 ;
     RECT  10.285 50.304 10.681 50.328 ;
     RECT  10.361 51.36 10.681 56.28 ;
     RECT  10.213 14.256 10.691 17.064 ;
     RECT  10.595 62.304 10.691 68.904 ;
     RECT  10.289 33.168 10.829 34.488 ;
     RECT  10.499 22.8 10.835 23.208 ;
     RECT  10.691 62.304 10.835 62.376 ;
     RECT  10.649 70.08 10.835 81.48 ;
     RECT  10.433 18.432 10.865 21.528 ;
     RECT  10.211 24.528 10.897 25.896 ;
     RECT  10.829 34.08 10.901 34.488 ;
     RECT  10.289 35.712 10.937 36.264 ;
     RECT  10.681 50.304 10.937 56.28 ;
     RECT  10.691 63.6 11.009 68.904 ;
     RECT  10.261 4.512 11.189 13.08 ;
     RECT  10.835 23.136 11.189 23.208 ;
     RECT  10.357 2.736 11.221 3.336 ;
     RECT  10.259 37.632 11.221 37.656 ;
     RECT  10.145 38.736 11.221 47.448 ;
     RECT  10.537 48.432 11.221 48.792 ;
     RECT  10.937 50.304 11.221 51.816 ;
     RECT  10.691 14.4 11.317 17.064 ;
     RECT  10.865 18.432 11.317 21.384 ;
     RECT  11.221 37.632 11.333 48.792 ;
     RECT  10.937 52.896 11.363 56.28 ;
     RECT  11.363 53.088 11.369 56.28 ;
     RECT  10.937 35.808 11.401 36.264 ;
     RECT  11.333 37.632 11.401 38.472 ;
     RECT  11.189 4.512 11.405 12.6 ;
     RECT  10.835 78.624 11.405 81.48 ;
     RECT  11.317 14.4 11.411 21.384 ;
     RECT  9.821 31.248 11.441 31.272 ;
     RECT  10.595 57.696 11.441 61.08 ;
     RECT  11.333 40.272 11.509 48.792 ;
     RECT  11.401 35.808 11.549 38.472 ;
     RECT  11.509 40.272 11.555 48.84 ;
     RECT  11.009 63.6 11.603 68.376 ;
     RECT  11.555 40.272 11.621 47.976 ;
     RECT  11.621 42.768 11.657 47.976 ;
     RECT  11.221 50.16 11.657 51.816 ;
     RECT  10.897 24.528 11.693 26.808 ;
     RECT  11.693 24.528 11.699 25.704 ;
     RECT  11.369 53.088 11.699 53.976 ;
     RECT  11.657 42.768 11.795 43.32 ;
     RECT  11.603 63.6 11.795 68.184 ;
     RECT  11.693 26.688 11.797 26.808 ;
     RECT  10.289 27.888 11.797 28.44 ;
     RECT  11.221 2.304 11.837 3.336 ;
     RECT  11.797 26.688 11.843 28.44 ;
     RECT  11.837 2.832 11.869 3.336 ;
     RECT  10.835 70.08 11.893 77.592 ;
     RECT  11.405 78.624 11.893 81.384 ;
     RECT  11.369 55.296 11.905 56.28 ;
     RECT  10.835 62.304 11.905 62.328 ;
     RECT  11.795 63.6 11.905 63.912 ;
     RECT  11.843 27.216 11.941 28.44 ;
     RECT  11.411 14.4 11.945 19.656 ;
     RECT  10.901 34.464 11.945 34.488 ;
     RECT  11.941 27.216 11.987 29.256 ;
     RECT  11.987 27.216 12.017 29.016 ;
     RECT  11.905 62.304 12.017 63.912 ;
     RECT  11.549 36.432 12.053 38.04 ;
     RECT  11.657 44.352 12.053 47.976 ;
     RECT  11.189 23.184 12.197 23.208 ;
     RECT  11.699 53.088 12.325 53.832 ;
     RECT  11.905 48.96 12.337 48.984 ;
     RECT  11.657 50.16 12.337 51.672 ;
     RECT  11.405 4.896 12.409 12.6 ;
     RECT  11.945 16.032 12.409 19.656 ;
     RECT  11.945 14.4 12.481 14.808 ;
     RECT  11.795 64.896 12.625 68.184 ;
     RECT  12.625 64.896 12.661 68.904 ;
     RECT  11.893 70.08 12.661 81.384 ;
     RECT  12.409 16.032 12.757 19.896 ;
     RECT  12.733 31.344 12.877 31.368 ;
     RECT  11.905 55.296 12.901 56.472 ;
     RECT  12.481 14.352 12.985 14.808 ;
     RECT  11.699 24.528 12.985 25.464 ;
     RECT  12.017 27.36 12.985 29.016 ;
     RECT  12.409 4.896 13.021 12.84 ;
     RECT  12.985 14.352 13.045 15 ;
     RECT  12.757 16.032 13.045 19.944 ;
     RECT  12.985 24.528 13.045 25.656 ;
     RECT  13.045 14.208 13.093 15 ;
     RECT  13.045 15.984 13.093 19.944 ;
     RECT  12.877 34.128 13.093 34.152 ;
     RECT  12.053 36.432 13.093 37.656 ;
     RECT  12.997 38.784 13.093 38.808 ;
     RECT  11.621 40.272 13.201 41.784 ;
     RECT  11.869 2.832 13.208 3.72 ;
     RECT  13.021 4.896 13.208 13.08 ;
     RECT  13.093 14.208 13.208 19.944 ;
     RECT  11.411 20.928 13.208 21.384 ;
     RECT  13.045 23.856 13.208 25.656 ;
     RECT  12.985 27.072 13.208 29.112 ;
     RECT  11.941 30.24 13.208 30.264 ;
     RECT  12.877 31.344 13.208 31.944 ;
     RECT  13.093 34.128 13.208 38.808 ;
     RECT  13.201 39.84 13.208 41.784 ;
     RECT  11.795 42.864 13.208 43.32 ;
     RECT  12.053 44.352 13.208 47.304 ;
     RECT  12.337 48.96 13.208 51.672 ;
     RECT  12.325 53.04 13.208 53.832 ;
     RECT  12.901 54.96 13.208 56.472 ;
     RECT  11.441 57.696 13.208 61.032 ;
     RECT  12.017 62.304 13.208 62.328 ;
     RECT  12.017 63.6 13.208 63.912 ;
     RECT  12.661 64.896 13.208 81.384 ;
     RECT  13.208 2.148 13.312 82.092 ;
     RECT  13.312 2.418 13.504 81.822 ;
     RECT  13.504 37.008 13.667 38.184 ;
     RECT  13.504 18.384 13.673 20.52 ;
     RECT  13.504 63.6 13.673 69 ;
     RECT  13.504 39.84 13.715 48.216 ;
     RECT  13.504 30.864 13.745 31.944 ;
     RECT  13.715 45.696 13.781 48.216 ;
     RECT  13.504 55.44 13.859 56.424 ;
     RECT  13.504 2.496 13.889 17.208 ;
     RECT  13.504 22.176 13.889 28.968 ;
     RECT  13.889 22.176 13.997 25.464 ;
     RECT  13.715 39.84 14.141 44.712 ;
     RECT  13.889 27.072 14.147 28.968 ;
     RECT  13.997 22.176 14.249 23.88 ;
     RECT  13.504 70.08 14.281 81.822 ;
     RECT  13.504 57.936 14.321 60.408 ;
     RECT  13.889 2.496 14.357 17.112 ;
     RECT  14.141 41.184 14.357 44.712 ;
     RECT  14.249 23.664 14.465 23.88 ;
     RECT  13.673 63.696 14.483 69 ;
     RECT  13.667 38.16 14.485 38.184 ;
     RECT  14.357 2.496 14.531 13.32 ;
     RECT  14.485 38.16 14.531 38.76 ;
     RECT  14.357 41.184 14.537 43.896 ;
     RECT  14.321 58.992 14.581 60.408 ;
     RECT  13.504 61.584 14.581 62.52 ;
     RECT  14.581 58.992 14.645 62.52 ;
     RECT  14.141 39.84 14.681 39.864 ;
     RECT  13.781 46.176 14.681 48.216 ;
     RECT  13.504 35.952 14.713 35.976 ;
     RECT  13.673 18.672 14.773 20.52 ;
     RECT  13.745 30.864 14.773 31.368 ;
     RECT  13.504 33.024 14.773 34.056 ;
     RECT  14.681 46.176 14.789 46.2 ;
     RECT  13.504 53.568 14.789 54.024 ;
     RECT  14.773 33.024 14.819 34.344 ;
     RECT  14.281 70.08 14.819 81.864 ;
     RECT  14.789 53.808 14.821 54.024 ;
     RECT  14.147 27.072 14.861 27.096 ;
     RECT  14.773 30.768 14.861 31.368 ;
     RECT  13.504 50.736 14.861 51.672 ;
     RECT  14.821 53.808 14.861 54.12 ;
     RECT  14.483 63.792 14.861 69 ;
     RECT  14.357 14.352 14.897 17.112 ;
     RECT  13.504 49.584 14.917 49.608 ;
     RECT  14.861 50.736 14.917 50.76 ;
     RECT  14.893 51.888 14.963 51.912 ;
     RECT  14.773 18.24 14.969 20.52 ;
     RECT  14.147 28.272 15.001 28.968 ;
     RECT  14.531 38.736 15.005 38.76 ;
     RECT  14.819 33.024 15.013 33.048 ;
     RECT  13.997 25.44 15.037 25.464 ;
     RECT  13.667 37.008 15.037 37.032 ;
     RECT  14.861 65.376 15.059 69 ;
     RECT  14.531 2.496 15.077 12.84 ;
     RECT  14.969 20.496 15.077 20.52 ;
     RECT  14.537 41.184 15.077 42.168 ;
     RECT  15.059 67.824 15.109 69 ;
     RECT  14.819 70.08 15.109 70.824 ;
     RECT  14.819 34.128 15.113 34.344 ;
     RECT  14.969 18.24 15.145 19.512 ;
     RECT  14.861 63.792 15.149 64.392 ;
     RECT  14.681 47.568 15.185 48.216 ;
     RECT  15.109 67.824 15.251 70.824 ;
     RECT  15.001 28.272 15.253 29.64 ;
     RECT  14.713 35.424 15.253 35.976 ;
     RECT  14.645 60.288 15.257 62.52 ;
     RECT  15.253 27.312 15.301 29.64 ;
     RECT  15.149 64.176 15.437 64.2 ;
     RECT  14.917 49.584 15.473 50.76 ;
     RECT  14.897 14.352 15.509 16.056 ;
     RECT  14.861 31.296 15.541 31.368 ;
     RECT  15.013 32.496 15.541 33.048 ;
     RECT  15.077 2.64 15.587 12.84 ;
     RECT  15.037 25.44 15.613 26.232 ;
     RECT  15.253 35.28 15.635 35.976 ;
     RECT  14.249 22.176 15.637 22.2 ;
     RECT  14.465 23.664 15.637 23.688 ;
     RECT  14.861 53.952 15.637 54.12 ;
     RECT  13.859 55.44 15.637 55.56 ;
     RECT  15.541 31.296 15.653 33.048 ;
     RECT  15.637 53.952 15.683 55.56 ;
     RECT  15.637 22.176 15.689 23.688 ;
     RECT  14.645 58.992 15.721 59.016 ;
     RECT  15.473 50.544 15.725 50.76 ;
     RECT  15.257 60.288 15.725 61.8 ;
     RECT  14.819 71.952 15.725 81.864 ;
     RECT  15.725 71.952 15.731 81.096 ;
     RECT  15.653 31.296 15.779 32.52 ;
     RECT  15.037 37.008 15.781 37.32 ;
     RECT  15.683 54.816 15.797 55.56 ;
     RECT  15.781 37.008 15.833 38.136 ;
     RECT  15.793 39.888 15.865 39.912 ;
     RECT  15.077 41.184 15.865 41.64 ;
     RECT  15.731 80.256 15.869 81.096 ;
     RECT  15.689 23.328 15.925 23.688 ;
     RECT  15.613 25.344 15.925 26.232 ;
     RECT  15.301 27.312 15.925 30.264 ;
     RECT  14.537 43.776 15.925 43.896 ;
     RECT  15.253 45.12 15.925 45.144 ;
     RECT  15.925 23.328 15.971 23.976 ;
     RECT  15.925 43.776 15.971 45.144 ;
     RECT  15.971 43.776 16.013 44.472 ;
     RECT  15.731 71.952 16.081 79.128 ;
     RECT  16.013 43.776 16.085 43.896 ;
     RECT  15.721 58.752 16.085 59.016 ;
     RECT  15.971 23.952 16.157 23.976 ;
     RECT  15.059 65.376 16.333 66.648 ;
     RECT  15.251 67.824 16.333 69 ;
     RECT  16.081 71.904 16.405 79.128 ;
     RECT  15.779 31.824 16.409 32.52 ;
     RECT  16.369 42.768 16.451 42.792 ;
     RECT  15.113 34.128 16.453 34.152 ;
     RECT  15.509 14.352 16.477 14.424 ;
     RECT  15.509 15.696 16.477 16.056 ;
     RECT  15.185 48.192 16.477 48.216 ;
     RECT  16.405 38.784 16.499 38.808 ;
     RECT  15.865 39.888 16.513 41.64 ;
     RECT  16.513 39.888 16.549 41.688 ;
     RECT  15.587 2.64 16.621 11.448 ;
     RECT  15.587 12.432 16.621 12.84 ;
     RECT  16.477 14.352 16.621 16.056 ;
     RECT  15.145 17.184 16.621 19.512 ;
     RECT  15.251 70.08 16.621 70.824 ;
     RECT  16.405 71.808 16.621 79.128 ;
     RECT  16.453 33.984 16.625 34.152 ;
     RECT  16.621 70.08 16.733 79.128 ;
     RECT  15.925 25.344 16.765 30.264 ;
     RECT  15.725 50.544 16.765 50.568 ;
     RECT  16.621 14.352 16.787 19.512 ;
     RECT  16.333 65.376 16.885 69 ;
     RECT  15.635 35.904 16.909 35.976 ;
     RECT  16.765 25.344 16.931 31.128 ;
     RECT  16.909 35.856 16.933 35.976 ;
     RECT  15.833 37.008 16.933 37.32 ;
     RECT  16.933 35.856 16.945 37.32 ;
     RECT  16.621 2.64 16.981 12.84 ;
     RECT  16.787 14.352 16.981 17.736 ;
     RECT  16.837 53.04 16.981 53.064 ;
     RECT  16.945 35.856 17.029 37.512 ;
     RECT  15.797 54.816 17.053 54.84 ;
     RECT  16.625 34.128 17.057 34.152 ;
     RECT  17.029 35.856 17.075 37.992 ;
     RECT  16.085 43.776 17.089 43.8 ;
     RECT  16.741 58.656 17.089 58.68 ;
     RECT  17.075 37.296 17.093 37.992 ;
     RECT  16.733 70.08 17.093 78.984 ;
     RECT  16.981 2.64 17.125 17.736 ;
     RECT  16.729 21.648 17.125 21.672 ;
     RECT  16.931 25.344 17.125 26.856 ;
     RECT  16.787 18.768 17.161 19.512 ;
     RECT  16.549 39.168 17.165 41.688 ;
     RECT  17.125 21.024 17.171 21.672 ;
     RECT  17.125 23.616 17.171 23.64 ;
     RECT  15.725 60.288 17.197 60.984 ;
     RECT  17.125 2.256 17.201 17.736 ;
     RECT  17.171 21.024 17.201 21.048 ;
     RECT  17.165 39.168 17.201 39.384 ;
     RECT  16.765 50.544 17.221 51.24 ;
     RECT  17.201 39.168 17.267 39.192 ;
     RECT  15.869 80.4 17.269 81.096 ;
     RECT  17.089 43.104 17.273 43.8 ;
     RECT  16.885 64.608 17.273 69 ;
     RECT  17.221 50.544 17.305 51.912 ;
     RECT  16.981 53.04 17.305 53.592 ;
     RECT  17.161 18.768 17.309 19.944 ;
     RECT  17.305 34.8 17.413 34.824 ;
     RECT  17.075 35.856 17.413 36.312 ;
     RECT  17.165 40.848 17.489 41.688 ;
     RECT  16.873 57.264 17.521 57.288 ;
     RECT  17.305 50.544 17.557 53.592 ;
     RECT  17.125 24.768 17.593 26.856 ;
     RECT  17.413 34.8 17.597 36.312 ;
     RECT  17.557 49.488 17.603 53.592 ;
     RECT  17.089 58.656 17.605 58.968 ;
     RECT  17.197 60.288 17.605 61.608 ;
     RECT  17.053 54.816 17.629 55.272 ;
     RECT  17.273 65.376 17.665 69 ;
     RECT  16.931 27.936 17.941 31.128 ;
     RECT  16.409 32.496 17.953 32.52 ;
     RECT  17.171 23.619 17.989 23.64 ;
     RECT  17.593 24.72 17.989 26.856 ;
     RECT  17.941 27.936 18.085 31.368 ;
     RECT  17.953 32.496 18.085 33 ;
     RECT  17.093 37.488 18.133 37.992 ;
     RECT  17.273 43.104 18.133 43.416 ;
     RECT  17.989 23.619 18.181 26.856 ;
     RECT  18.085 27.936 18.181 33 ;
     RECT  17.489 40.848 18.181 40.872 ;
     RECT  17.665 65.376 18.181 69.048 ;
     RECT  17.093 70.08 18.181 78.744 ;
     RECT  17.269 80.304 18.181 81.096 ;
     RECT  17.201 2.256 18.277 2.28 ;
     RECT  17.201 3.36 18.277 17.736 ;
     RECT  17.917 62.784 18.277 62.808 ;
     RECT  17.309 18.816 18.313 19.944 ;
     RECT  17.953 22.032 18.313 22.056 ;
     RECT  18.181 23.619 18.313 33 ;
     RECT  17.521 56.448 18.325 57.288 ;
     RECT  18.277 2.256 18.373 17.736 ;
     RECT  18.313 18.816 18.373 20.712 ;
     RECT  18.181 79.728 18.385 81.096 ;
     RECT  17.597 35.328 18.421 36.312 ;
     RECT  18.133 37.44 18.421 37.992 ;
     RECT  18.133 45.696 18.469 45.72 ;
     RECT  16.477 47.904 18.469 48.216 ;
     RECT  18.325 56.448 18.469 57.432 ;
     RECT  17.605 58.656 18.469 61.608 ;
     RECT  18.277 62.784 18.469 62.952 ;
     RECT  18.469 62.784 18.565 63.288 ;
     RECT  18.373 2.256 18.608 20.712 ;
     RECT  18.313 22.032 18.608 33 ;
     RECT  18.421 35.328 18.608 39.096 ;
     RECT  18.181 40.08 18.608 40.872 ;
     RECT  18.133 42.192 18.608 43.416 ;
     RECT  18.313 44.448 18.608 44.472 ;
     RECT  18.469 45.504 18.608 45.72 ;
     RECT  18.469 47.904 18.608 48.504 ;
     RECT  17.603 49.488 18.608 50.568 ;
     RECT  17.603 51.888 18.608 53.592 ;
     RECT  17.629 54.72 18.608 55.272 ;
     RECT  18.469 56.448 18.608 61.608 ;
     RECT  18.565 62.736 18.608 63.288 ;
     RECT  18.181 65.376 18.608 78.744 ;
     RECT  18.385 79.728 18.608 81.624 ;
     RECT  18.608 2.148 18.712 82.092 ;
     RECT  18.712 2.418 18.904 81.822 ;
     RECT  18.904 64.416 18.965 70.344 ;
     RECT  18.904 41.904 19.043 46.632 ;
     RECT  18.904 77.376 19.043 81.624 ;
     RECT  18.904 4.464 19.091 24.552 ;
     RECT  19.043 41.904 19.139 46.2 ;
     RECT  18.904 55.872 19.181 63.24 ;
     RECT  18.904 25.824 19.289 31.128 ;
     RECT  19.091 4.464 19.325 21.144 ;
     RECT  19.181 55.872 19.361 55.896 ;
     RECT  18.904 52.464 19.397 52.92 ;
     RECT  19.181 56.88 19.397 63.24 ;
     RECT  19.139 45.024 19.433 46.2 ;
     RECT  18.904 2.88 19.505 3.432 ;
     RECT  19.397 58.608 19.505 63.24 ;
     RECT  19.043 77.472 19.505 81.528 ;
     RECT  19.325 4.464 19.541 19.992 ;
     RECT  19.541 14.16 19.571 19.992 ;
     RECT  19.505 77.568 19.577 77.928 ;
     RECT  19.571 14.352 19.613 19.992 ;
     RECT  18.904 32.304 19.613 40.872 ;
     RECT  19.613 33.072 19.649 40.872 ;
     RECT  19.577 77.568 19.649 77.688 ;
     RECT  19.505 58.608 19.721 63.192 ;
     RECT  18.965 64.944 19.757 70.344 ;
     RECT  18.904 54.336 19.763 54.888 ;
     RECT  19.541 4.464 19.829 13.032 ;
     RECT  19.613 14.352 19.865 17.16 ;
     RECT  19.505 79.44 19.865 81.528 ;
     RECT  18.904 71.472 19.897 76.296 ;
     RECT  19.721 58.608 19.901 62.76 ;
     RECT  19.865 14.352 19.937 15.432 ;
     RECT  19.397 56.88 19.937 57.624 ;
     RECT  19.649 33.6 19.955 40.872 ;
     RECT  19.955 34.032 19.973 40.872 ;
     RECT  19.973 35.328 20.003 40.872 ;
     RECT  19.397 52.896 20.009 52.92 ;
     RECT  19.937 57.456 20.009 57.624 ;
     RECT  19.757 64.944 20.041 69.768 ;
     RECT  19.829 4.464 20.045 7.416 ;
     RECT  19.865 17.136 20.045 17.16 ;
     RECT  19.897 71.472 20.045 76.392 ;
     RECT  18.904 47.856 20.053 49.08 ;
     RECT  20.041 64.704 20.101 69.768 ;
     RECT  19.433 45.456 20.149 46.2 ;
     RECT  20.053 47.232 20.149 49.08 ;
     RECT  19.937 14.352 20.153 14.376 ;
     RECT  18.904 50.448 20.153 50.568 ;
     RECT  19.091 22.8 20.221 24.552 ;
     RECT  19.613 18.144 20.293 19.992 ;
     RECT  19.325 21.12 20.293 21.144 ;
     RECT  19.289 25.824 20.293 30.792 ;
     RECT  20.003 35.856 20.293 40.872 ;
     RECT  19.139 41.904 20.293 43.944 ;
     RECT  20.221 22.704 20.339 24.552 ;
     RECT  20.293 35.856 20.365 43.944 ;
     RECT  20.101 64.608 20.405 69.768 ;
     RECT  20.009 57.504 20.437 57.624 ;
     RECT  19.901 59.184 20.483 62.76 ;
     RECT  20.405 66.624 20.513 69.768 ;
     RECT  20.365 35.856 20.533 44.424 ;
     RECT  20.149 45.456 20.533 49.08 ;
     RECT  20.293 18.144 20.585 21.144 ;
     RECT  20.339 22.704 20.585 22.824 ;
     RECT  20.293 25.824 20.585 31.896 ;
     RECT  20.513 66.864 20.585 69.768 ;
     RECT  20.585 25.824 20.675 31.416 ;
     RECT  19.829 8.544 20.723 13.032 ;
     RECT  19.505 3.168 20.725 3.432 ;
     RECT  20.437 57.504 20.729 58.056 ;
     RECT  20.585 67.104 20.761 69.768 ;
     RECT  20.723 12.336 20.797 13.032 ;
     RECT  20.483 60.384 20.801 62.76 ;
     RECT  20.797 12.336 20.821 13.128 ;
     RECT  20.389 52.272 20.837 52.296 ;
     RECT  19.763 54.336 20.869 54.6 ;
     RECT  20.045 4.464 20.873 7.176 ;
     RECT  20.821 12.336 20.909 13.704 ;
     RECT  20.761 67.104 20.909 70.152 ;
     RECT  20.801 60.432 20.977 62.76 ;
     RECT  20.725 2.832 21.013 3.432 ;
     RECT  20.873 4.464 21.013 6.024 ;
     RECT  20.585 20.544 21.013 21.144 ;
     RECT  20.339 24.48 21.013 24.552 ;
     RECT  20.675 25.824 21.013 27.384 ;
     RECT  20.533 35.856 21.013 49.08 ;
     RECT  20.977 60.432 21.013 62.856 ;
     RECT  20.873 7.104 21.049 7.176 ;
     RECT  20.723 8.544 21.049 11.256 ;
     RECT  21.013 60.432 21.049 63.528 ;
     RECT  20.405 64.608 21.049 65.64 ;
     RECT  19.649 77.568 21.049 77.64 ;
     RECT  21.013 20.544 21.059 21.624 ;
     RECT  20.045 71.472 21.061 74.136 ;
     RECT  19.973 34.032 21.085 34.104 ;
     RECT  21.049 60.432 21.089 65.64 ;
     RECT  21.061 71.328 21.107 74.136 ;
     RECT  20.045 75.264 21.109 76.392 ;
     RECT  21.107 72.576 21.121 74.136 ;
     RECT  21.109 75.12 21.121 76.392 ;
     RECT  21.013 35.472 21.197 49.08 ;
     RECT  21.049 77.568 21.229 78.264 ;
     RECT  19.865 79.44 21.229 80.952 ;
     RECT  21.121 72.576 21.233 76.392 ;
     RECT  20.585 18.144 21.253 19.368 ;
     RECT  21.013 24.48 21.269 27.384 ;
     RECT  21.089 60.432 21.269 63.192 ;
     RECT  21.229 77.568 21.347 81.336 ;
     RECT  21.085 34.032 21.373 34.2 ;
     RECT  21.197 35.472 21.373 47.064 ;
     RECT  21.269 61.536 21.395 63.192 ;
     RECT  21.089 64.224 21.395 65.64 ;
     RECT  21.253 17.952 21.445 19.368 ;
     RECT  20.869 53.568 21.445 54.744 ;
     RECT  21.059 20.544 21.491 20.568 ;
     RECT  21.059 21.6 21.541 21.624 ;
     RECT  21.373 34.032 21.589 47.064 ;
     RECT  21.395 61.584 21.629 62.472 ;
     RECT  21.541 21.6 21.637 21.672 ;
     RECT  21.445 17.616 21.661 19.368 ;
     RECT  21.269 26.256 21.661 27.384 ;
     RECT  20.675 28.416 21.661 31.416 ;
     RECT  21.661 26.256 21.701 31.416 ;
     RECT  21.347 79.968 21.701 81.336 ;
     RECT  21.589 33.648 21.733 47.064 ;
     RECT  21.233 72.576 21.737 75.144 ;
     RECT  21.701 26.784 21.769 31.416 ;
     RECT  21.269 60.432 21.773 60.552 ;
     RECT  20.909 12.336 21.877 13.608 ;
     RECT  21.637 21.6 21.877 21.72 ;
     RECT  21.733 33.264 21.877 47.064 ;
     RECT  21.395 64.944 21.877 65.64 ;
     RECT  21.589 66.72 21.877 66.744 ;
     RECT  21.701 79.968 21.917 81.096 ;
     RECT  21.877 33.072 21.923 47.064 ;
     RECT  20.729 57.504 21.925 57.576 ;
     RECT  21.269 24.48 21.989 25.08 ;
     RECT  21.445 53.568 21.989 54.888 ;
     RECT  20.909 67.728 21.989 70.152 ;
     RECT  21.877 21.6 22.021 22.152 ;
     RECT  21.989 54.144 22.021 54.888 ;
     RECT  21.737 72.576 22.025 74.712 ;
     RECT  21.347 77.568 22.025 78.504 ;
     RECT  21.989 70.128 22.117 70.152 ;
     RECT  21.107 71.328 22.117 71.352 ;
     RECT  22.093 52.704 22.163 52.728 ;
     RECT  22.117 70.128 22.163 71.352 ;
     RECT  21.949 16.56 22.165 16.584 ;
     RECT  21.661 17.616 22.165 19.848 ;
     RECT  22.021 21.216 22.165 22.152 ;
     RECT  21.233 76.176 22.205 76.392 ;
     RECT  22.165 21.216 22.211 22.2 ;
     RECT  21.877 64.944 22.277 66.744 ;
     RECT  21.949 23.328 22.349 23.352 ;
     RECT  21.049 7.104 22.405 11.256 ;
     RECT  21.877 12.336 22.405 14.328 ;
     RECT  21.629 61.584 22.421 62.328 ;
     RECT  22.165 16.56 22.453 19.848 ;
     RECT  22.405 7.104 22.457 14.328 ;
     RECT  19.937 15.408 22.489 15.432 ;
     RECT  22.453 16.512 22.489 19.848 ;
     RECT  21.013 2.832 22.529 6.024 ;
     RECT  20.483 59.184 22.529 59.208 ;
     RECT  22.025 72.576 22.529 72.6 ;
     RECT  22.277 64.944 22.561 66.168 ;
     RECT  22.529 3.168 22.637 3.432 ;
     RECT  21.989 67.728 22.673 68.76 ;
     RECT  22.457 12.336 22.693 14.328 ;
     RECT  22.489 15.408 22.693 19.848 ;
     RECT  22.529 4.8 22.741 6.024 ;
     RECT  22.457 7.104 22.741 11.16 ;
     RECT  22.025 73.776 22.741 74.712 ;
     RECT  22.637 3.408 22.745 3.432 ;
     RECT  22.561 64.896 22.777 66.168 ;
     RECT  21.661 51.6 22.789 51.624 ;
     RECT  22.163 70.272 22.817 71.352 ;
     RECT  22.741 73.776 22.817 75.24 ;
     RECT  22.205 76.368 22.817 76.392 ;
     RECT  22.789 51.6 22.835 52.008 ;
     RECT  22.211 21.216 22.853 21.72 ;
     RECT  21.923 33.264 22.885 47.064 ;
     RECT  21.197 48.192 22.885 49.08 ;
     RECT  21.925 56.88 22.885 57.576 ;
     RECT  22.813 58.704 22.885 58.872 ;
     RECT  22.777 64.368 22.889 66.168 ;
     RECT  22.817 75.216 22.889 75.24 ;
     RECT  22.693 12.336 22.957 19.848 ;
     RECT  22.853 21.216 22.957 21.48 ;
     RECT  21.989 25.056 22.957 25.08 ;
     RECT  21.769 26.784 22.957 31.896 ;
     RECT  22.885 33.264 22.957 49.08 ;
     RECT  21.917 80.256 22.993 81.096 ;
     RECT  22.957 25.056 23.029 25.704 ;
     RECT  22.993 80.256 23.077 81.528 ;
     RECT  22.021 54.144 23.137 55.848 ;
     RECT  22.885 56.832 23.137 58.872 ;
     RECT  22.835 51.696 23.173 52.008 ;
     RECT  21.773 60.528 23.173 60.552 ;
     RECT  22.421 61.584 23.173 61.848 ;
     RECT  23.029 25.056 23.209 25.752 ;
     RECT  22.957 26.784 23.209 49.08 ;
     RECT  23.209 25.056 23.245 49.08 ;
     RECT  20.153 50.544 23.245 50.568 ;
     RECT  23.137 54.144 23.245 58.872 ;
     RECT  22.673 67.728 23.317 68.712 ;
     RECT  22.817 71.328 23.317 71.352 ;
     RECT  23.173 51.696 23.353 52.056 ;
     RECT  23.245 53.568 23.353 58.872 ;
     RECT  23.269 75.264 23.425 75.288 ;
     RECT  23.245 25.056 23.533 50.568 ;
     RECT  22.025 77.568 23.641 78.264 ;
     RECT  23.557 22.752 23.677 22.776 ;
     RECT  22.741 4.8 23.749 11.16 ;
     RECT  23.641 77.568 23.749 78.648 ;
     RECT  23.077 79.824 23.749 81.528 ;
     RECT  23.749 3.984 23.785 11.16 ;
     RECT  22.957 12.336 23.785 21.48 ;
     RECT  23.677 22.752 23.821 22.824 ;
     RECT  23.533 24.912 23.821 50.568 ;
     RECT  23.353 51.696 23.821 58.872 ;
     RECT  23.785 3.984 23.845 21.48 ;
     RECT  23.845 3.408 23.965 21.48 ;
     RECT  22.817 73.776 23.965 73.8 ;
     RECT  23.425 75.264 23.965 75.96 ;
     RECT  23.821 24.912 24.001 58.872 ;
     RECT  23.749 77.568 24.001 81.528 ;
     RECT  23.965 3.408 24.008 21.768 ;
     RECT  23.821 22.752 24.008 23.16 ;
     RECT  24.001 24.624 24.008 58.872 ;
     RECT  23.173 60.528 24.008 61.848 ;
     RECT  22.889 64.944 24.008 65.688 ;
     RECT  23.317 67.584 24.008 68.712 ;
     RECT  22.817 70.272 24.008 70.296 ;
     RECT  23.317 71.328 24.008 72.264 ;
     RECT  23.965 73.776 24.008 75.96 ;
     RECT  24.001 77.28 24.008 81.528 ;
     RECT  24.008 2.148 24.112 82.092 ;
     RECT  24.112 2.418 24.304 81.822 ;
     RECT  24.304 74.496 24.419 79.272 ;
     RECT  24.419 74.496 24.473 77.016 ;
     RECT  24.304 80.256 24.473 80.952 ;
     RECT  24.304 18.816 24.509 65.16 ;
     RECT  24.509 19.776 24.545 65.16 ;
     RECT  24.473 74.688 24.545 77.016 ;
     RECT  24.304 3.408 24.617 3.432 ;
     RECT  24.304 70.752 24.761 73.416 ;
     RECT  24.419 78.048 24.761 79.272 ;
     RECT  24.761 78.048 24.905 78.888 ;
     RECT  24.761 72.912 24.947 73.416 ;
     RECT  24.545 76.368 25.049 77.016 ;
     RECT  24.545 19.776 25.121 51.72 ;
     RECT  24.905 78.048 25.139 78.36 ;
     RECT  25.121 26.688 25.193 51.72 ;
     RECT  24.304 4.512 25.283 17.64 ;
     RECT  25.283 4.512 25.337 6.024 ;
     RECT  25.337 5.568 25.373 6.024 ;
     RECT  24.761 70.752 25.373 71.736 ;
     RECT  24.473 80.4 25.409 80.952 ;
     RECT  25.283 7.152 25.429 17.64 ;
     RECT  25.429 7.152 25.477 18.216 ;
     RECT  24.545 74.688 25.513 75 ;
     RECT  25.513 74.064 25.525 75 ;
     RECT  25.373 5.664 25.571 6.024 ;
     RECT  25.525 74.064 25.571 75.288 ;
     RECT  25.477 7.152 25.621 18.696 ;
     RECT  25.621 7.152 25.667 18.744 ;
     RECT  24.947 72.912 25.697 72.936 ;
     RECT  25.193 49.008 25.765 51.72 ;
     RECT  24.545 52.704 25.765 65.16 ;
     RECT  25.121 19.776 25.769 25.416 ;
     RECT  25.667 7.152 25.805 18.696 ;
     RECT  24.304 67.488 25.805 67.512 ;
     RECT  25.765 49.008 25.841 65.16 ;
     RECT  25.805 18.672 25.877 18.696 ;
     RECT  25.841 49.008 25.877 61.08 ;
     RECT  25.571 74.688 25.913 75.288 ;
     RECT  25.805 7.152 25.949 17.64 ;
     RECT  25.139 78.048 25.949 78.12 ;
     RECT  25.949 16.56 26.021 17.64 ;
     RECT  25.841 62.064 26.099 65.16 ;
     RECT  24.304 68.688 26.101 68.712 ;
     RECT  25.373 70.752 26.101 71.352 ;
     RECT  25.769 19.824 26.125 25.416 ;
     RECT  25.193 26.688 26.125 47.928 ;
     RECT  26.101 68.688 26.165 69.384 ;
     RECT  26.101 70.704 26.165 71.352 ;
     RECT  25.861 66.72 26.197 67.32 ;
     RECT  25.949 7.152 26.237 15.384 ;
     RECT  26.237 7.152 26.243 10.872 ;
     RECT  25.571 5.664 26.273 5.784 ;
     RECT  26.099 62.16 26.273 65.16 ;
     RECT  25.877 60.192 26.291 61.08 ;
     RECT  26.273 62.16 26.309 63.288 ;
     RECT  26.273 64.608 26.309 65.16 ;
     RECT  25.409 80.4 26.531 80.424 ;
     RECT  26.125 19.824 26.557 47.928 ;
     RECT  25.877 49.008 26.557 58.968 ;
     RECT  25.337 4.512 26.597 4.536 ;
     RECT  26.557 72.384 26.627 72.408 ;
     RECT  26.165 68.688 26.629 69.24 ;
     RECT  26.291 60.192 26.669 61.032 ;
     RECT  26.021 16.56 26.705 17.112 ;
     RECT  26.237 12 26.723 15.384 ;
     RECT  26.723 14.832 26.771 15.384 ;
     RECT  26.165 71.328 26.809 71.352 ;
     RECT  26.723 12 26.813 13.704 ;
     RECT  26.771 15.168 26.813 15.384 ;
     RECT  25.049 76.848 26.885 77.016 ;
     RECT  26.557 19.824 26.953 58.968 ;
     RECT  26.669 60.192 26.953 60.984 ;
     RECT  26.953 19.824 26.993 60.984 ;
     RECT  26.701 73.392 27.013 73.416 ;
     RECT  25.913 74.688 27.013 74.712 ;
     RECT  26.309 65.04 27.025 65.16 ;
     RECT  26.197 66.144 27.025 67.32 ;
     RECT  26.089 75.792 27.065 75.816 ;
     RECT  26.813 15.36 27.101 15.384 ;
     RECT  27.025 65.04 27.155 67.32 ;
     RECT  27.013 73.392 27.157 74.712 ;
     RECT  26.629 68.4 27.169 69.24 ;
     RECT  25.949 78.048 27.203 78.072 ;
     RECT  26.273 5.76 27.241 5.784 ;
     RECT  26.705 16.56 27.277 16.824 ;
     RECT  26.309 62.16 27.301 63 ;
     RECT  27.155 66.72 27.313 67.32 ;
     RECT  27.169 68.352 27.313 69.24 ;
     RECT  27.301 62.16 27.353 63.24 ;
     RECT  27.155 65.04 27.353 65.592 ;
     RECT  26.243 7.152 27.389 10.2 ;
     RECT  27.353 62.16 27.389 62.712 ;
     RECT  27.389 10.176 27.421 10.2 ;
     RECT  27.389 7.152 27.461 9.096 ;
     RECT  27.421 10.176 27.491 11.016 ;
     RECT  27.461 7.152 27.497 7.224 ;
     RECT  27.277 16.512 27.497 16.824 ;
     RECT  27.353 65.04 27.497 65.544 ;
     RECT  26.993 19.92 27.533 60.984 ;
     RECT  27.313 66.72 27.533 69.24 ;
     RECT  27.461 8.4 27.635 9.096 ;
     RECT  27.491 10.176 27.641 10.872 ;
     RECT  27.533 67.248 27.673 69.24 ;
     RECT  27.277 70.272 27.673 70.296 ;
     RECT  27.241 5.472 27.713 5.784 ;
     RECT  27.673 63.792 27.731 63.816 ;
     RECT  27.533 60.96 27.733 60.984 ;
     RECT  27.673 67.248 27.781 70.296 ;
     RECT  26.809 71.328 27.781 71.784 ;
     RECT  27.157 72.912 27.781 74.712 ;
     RECT  27.781 67.248 27.821 74.712 ;
     RECT  27.821 72.336 27.827 74.712 ;
     RECT  27.635 8.4 27.857 8.472 ;
     RECT  27.733 60.96 27.875 61.08 ;
     RECT  27.817 79.248 27.875 79.272 ;
     RECT  27.733 64.368 27.893 64.968 ;
     RECT  27.641 10.176 27.929 10.536 ;
     RECT  27.533 19.92 27.929 59.832 ;
     RECT  27.497 16.512 27.965 16.584 ;
     RECT  27.929 58.56 27.965 59.832 ;
     RECT  27.929 19.92 28.001 57.528 ;
     RECT  26.813 12 28.069 13.128 ;
     RECT  26.885 76.992 28.069 77.016 ;
     RECT  27.875 61.008 28.073 61.08 ;
     RECT  28.069 11.952 28.109 13.128 ;
     RECT  27.389 62.208 28.109 62.712 ;
     RECT  27.889 79.392 28.115 79.992 ;
     RECT  27.857 8.448 28.145 8.472 ;
     RECT  28.001 20.448 28.253 56.808 ;
     RECT  27.821 67.248 28.253 71.352 ;
     RECT  27.827 72.912 28.285 74.712 ;
     RECT  27.673 3.936 28.325 3.96 ;
     RECT  28.285 72.912 28.355 74.76 ;
     RECT  27.713 5.712 28.397 5.784 ;
     RECT  28.253 67.248 28.433 70.632 ;
     RECT  28.109 62.256 28.465 62.712 ;
     RECT  28.177 18 28.609 18.024 ;
     RECT  28.465 62.256 28.825 62.952 ;
     RECT  27.497 7.152 29.005 7.176 ;
     RECT  27.929 10.224 29.029 10.536 ;
     RECT  28.033 75.792 29.041 75.816 ;
     RECT  28.069 76.896 29.041 77.016 ;
     RECT  28.109 11.952 29.077 12.792 ;
     RECT  27.965 58.56 29.077 59.496 ;
     RECT  29.005 7.152 29.185 7.896 ;
     RECT  27.965 16.512 29.221 16.536 ;
     RECT  29.221 16.512 29.365 16.68 ;
     RECT  26.593 2.544 29.408 2.568 ;
     RECT  28.453 3.84 29.408 3.864 ;
     RECT  28.397 5.712 29.408 5.736 ;
     RECT  29.185 7.104 29.408 7.896 ;
     RECT  29.029 9.696 29.408 10.536 ;
     RECT  29.077 11.952 29.408 13.128 ;
     RECT  29.365 16.512 29.408 16.968 ;
     RECT  28.609 18 29.408 18.216 ;
     RECT  28.253 20.64 29.408 56.808 ;
     RECT  29.077 58.512 29.408 59.496 ;
     RECT  28.141 61.104 29.408 61.128 ;
     RECT  28.825 62.256 29.408 63.288 ;
     RECT  27.893 64.896 29.408 64.968 ;
     RECT  28.429 66.096 29.408 66.12 ;
     RECT  28.433 67.584 29.408 70.152 ;
     RECT  28.355 72.912 29.408 74.712 ;
     RECT  29.041 75.792 29.408 77.016 ;
     RECT  29.408 2.148 29.512 82.092 ;
     RECT  29.512 2.418 29.704 81.822 ;
     RECT  29.704 33.936 29.873 38.184 ;
     RECT  29.704 7.104 29.945 7.128 ;
     RECT  29.704 26.88 30.697 32.856 ;
     RECT  29.873 33.936 30.697 37.608 ;
     RECT  30.697 26.88 30.733 37.608 ;
     RECT  29.704 39.312 30.733 57.192 ;
     RECT  29.704 13.104 30.769 25.704 ;
     RECT  30.733 26.832 30.769 37.608 ;
     RECT  30.769 13.104 31.129 37.608 ;
     RECT  30.733 39.12 31.129 57.192 ;
     RECT  31.129 13.104 31.201 57.192 ;
     RECT  29.704 58.32 31.201 64.392 ;
     RECT  31.201 13.104 32.281 64.392 ;
     RECT  32.281 12.912 32.364 64.392 ;
     RECT  32.364 12.912 32.393 12.936 ;
    LAYER M5 ;
     RECT  2.4 2.137 2.52 2.151 ;
     RECT  7.8 2.137 7.92 2.151 ;
     RECT  13.2 2.137 13.32 2.151 ;
     RECT  18.6 2.137 18.72 2.151 ;
     RECT  24 2.137 24.12 2.151 ;
     RECT  29.4 2.137 29.52 2.151 ;
     RECT  15.36 2.629 15.384 2.915 ;
     RECT  13.2 2.151 13.512 2.917 ;
     RECT  2.4 2.151 2.712 3.349 ;
     RECT  18.6 2.151 18.912 3.349 ;
     RECT  9.36 2.821 9.384 3.397 ;
     RECT  10.368 2.725 10.392 3.397 ;
     RECT  24 2.151 24.312 3.397 ;
     RECT  13.2 2.917 13.848 3.443 ;
     RECT  7.8 2.151 8.112 3.733 ;
     RECT  2.4 3.349 2.808 3.781 ;
     RECT  29.4 2.151 29.712 3.829 ;
     RECT  2.4 3.781 3.624 3.925 ;
     RECT  7.8 3.733 8.232 3.925 ;
     RECT  23.856 3.397 24.312 4.501 ;
     RECT  22.176 3.349 22.2 4.595 ;
     RECT  9.36 3.397 10.392 4.645 ;
     RECT  11.76 3.157 11.784 4.645 ;
     RECT  18 3.349 18.912 4.645 ;
     RECT  15.984 3.877 16.008 4.741 ;
     RECT  17.088 4.645 18.912 4.741 ;
     RECT  20.064 4.453 20.328 5.171 ;
     RECT  13.2 3.443 13.512 5.221 ;
     RECT  23.856 4.501 25.128 5.317 ;
     RECT  23.376 5.317 25.128 5.461 ;
     RECT  2.4 3.925 3.912 5.605 ;
     RECT  5.088 4.261 5.112 5.605 ;
     RECT  15.984 4.741 18.912 5.605 ;
     RECT  20.304 5.171 20.328 5.653 ;
     RECT  15.984 5.605 19.128 5.747 ;
     RECT  28.464 3.829 29.712 5.747 ;
     RECT  21.888 5.317 21.912 5.893 ;
     RECT  23.376 5.461 25.224 5.989 ;
     RECT  18 5.747 19.128 6.035 ;
     RECT  9.36 4.645 11.784 6.083 ;
     RECT  7.152 3.925 8.232 6.085 ;
     RECT  2.4 5.605 5.112 6.229 ;
     RECT  13.2 5.221 14.472 6.229 ;
     RECT  21.888 5.893 22.296 6.229 ;
     RECT  23.376 5.989 25.56 6.229 ;
     RECT  2.4 6.229 5.592 6.613 ;
     RECT  6.864 6.085 8.232 6.709 ;
     RECT  9.36 6.083 10.68 6.709 ;
     RECT  2.4 6.613 5.64 6.805 ;
     RECT  6.864 6.709 10.68 6.805 ;
     RECT  15.984 5.747 16.824 6.899 ;
     RECT  15.984 6.899 16.776 7.331 ;
     RECT  18.48 6.035 19.128 7.381 ;
     RECT  20.304 5.653 20.664 7.381 ;
     RECT  21.888 6.229 25.56 7.429 ;
     RECT  12.912 6.229 14.472 7.861 ;
     RECT  29.4 5.747 29.712 7.861 ;
     RECT  21.888 7.429 26.376 7.955 ;
     RECT  11.76 6.083 11.784 7.957 ;
     RECT  12.912 7.861 14.808 7.957 ;
     RECT  18.48 7.381 20.664 7.957 ;
     RECT  18.24 7.957 20.664 8.003 ;
     RECT  16.752 7.331 16.776 8.339 ;
     RECT  11.76 7.957 14.808 8.579 ;
     RECT  20.304 8.003 20.664 8.579 ;
     RECT  18.24 8.003 18.912 8.965 ;
     RECT  12.816 8.579 14.808 9.061 ;
     RECT  20.64 8.579 20.664 9.061 ;
     RECT  27.456 8.437 27.48 9.061 ;
     RECT  17.616 8.965 18.912 9.205 ;
     RECT  20.64 9.061 20.856 9.349 ;
     RECT  21.888 7.955 26.232 9.349 ;
     RECT  17.616 9.205 19.608 9.731 ;
     RECT  29.04 7.861 29.712 9.731 ;
     RECT  2.4 6.805 10.68 9.925 ;
     RECT  17.952 9.731 19.608 9.925 ;
     RECT  20.64 9.349 26.232 9.925 ;
     RECT  27.456 9.061 27.624 10.213 ;
     RECT  17.952 9.925 26.232 10.883 ;
     RECT  2.4 9.925 10.728 11.029 ;
     RECT  11.76 8.579 11.784 11.029 ;
     RECT  12.816 9.061 15.432 11.029 ;
     RECT  17.952 10.883 25.752 11.653 ;
     RECT  2.4 11.029 15.432 11.797 ;
     RECT  27.456 10.213 28.104 11.987 ;
     RECT  17.424 11.653 25.752 12.035 ;
     RECT  27.456 11.987 27.48 12.035 ;
     RECT  2.4 11.797 15.576 12.563 ;
     RECT  17.424 12.035 19.608 12.563 ;
     RECT  20.688 12.035 25.752 12.947 ;
     RECT  17.424 12.563 19.368 13.139 ;
     RECT  20.832 12.947 25.752 13.141 ;
     RECT  26.736 12.517 26.76 13.141 ;
     RECT  20.832 13.141 26.76 13.667 ;
     RECT  20.832 13.667 25.512 13.715 ;
     RECT  17.424 13.139 18.912 14.149 ;
     RECT  2.4 12.563 10.728 14.821 ;
     RECT  11.76 12.563 14.616 14.821 ;
     RECT  26.544 13.667 26.76 14.867 ;
     RECT  26.544 14.867 26.712 14.915 ;
     RECT  26.64 14.915 26.712 14.963 ;
     RECT  26.688 14.963 26.712 15.347 ;
     RECT  21.264 13.715 25.512 16.165 ;
     RECT  17.424 14.149 19.56 16.501 ;
     RECT  2.4 14.821 14.616 17.077 ;
     RECT  16.752 16.501 19.56 17.077 ;
     RECT  21.264 16.165 25.656 17.699 ;
     RECT  21.264 17.699 25.512 18.179 ;
     RECT  16.752 17.077 19.608 18.181 ;
     RECT  2.4 17.077 14.808 18.229 ;
     RECT  2.4 18.229 15.48 18.275 ;
     RECT  16.752 18.181 19.656 18.275 ;
     RECT  21.264 18.179 21.576 18.565 ;
     RECT  23.04 18.179 25.512 18.709 ;
     RECT  2.4 18.275 14.472 18.851 ;
     RECT  15.456 18.275 15.48 18.947 ;
     RECT  20.736 18.565 21.576 19.379 ;
     RECT  2.4 18.851 11.832 19.909 ;
     RECT  12.816 18.851 14.472 19.909 ;
     RECT  23.04 18.709 25.656 19.909 ;
     RECT  26.64 19.813 26.664 19.909 ;
     RECT  23.04 19.909 26.664 20.437 ;
     RECT  21.456 19.379 21.576 20.533 ;
     RECT  23.04 20.437 26.76 20.579 ;
     RECT  17.424 18.275 19.656 20.629 ;
     RECT  21.168 20.533 21.576 20.629 ;
     RECT  17.424 20.629 21.576 21.013 ;
     RECT  2.4 19.909 14.472 21.155 ;
     RECT  26.64 20.579 26.76 21.155 ;
     RECT  26.64 21.155 26.712 21.203 ;
     RECT  0.24 21.205 0.264 21.397 ;
     RECT  0.192 21.397 0.264 21.493 ;
     RECT  17.136 21.013 21.576 21.589 ;
     RECT  17.136 21.589 21.672 21.683 ;
     RECT  0.144 21.493 0.264 21.925 ;
     RECT  0.144 21.925 0.312 21.971 ;
     RECT  26.688 21.203 26.712 21.971 ;
     RECT  17.424 21.683 21.672 22.117 ;
     RECT  17.424 22.117 21.912 22.165 ;
     RECT  23.04 20.579 25.656 22.165 ;
     RECT  17.424 22.165 25.656 22.259 ;
     RECT  0.192 21.971 0.312 22.693 ;
     RECT  0.192 22.693 0.36 22.835 ;
     RECT  15.648 22.165 15.672 22.835 ;
     RECT  0.192 22.835 0.312 22.933 ;
     RECT  2.4 21.155 11.784 22.979 ;
     RECT  0.144 22.933 0.312 23.123 ;
     RECT  17.424 22.259 25.512 23.363 ;
     RECT  0.24 23.123 0.312 23.507 ;
     RECT  17.424 23.363 21.912 23.605 ;
     RECT  17.136 23.605 21.912 23.651 ;
     RECT  15.936 23.317 15.96 23.987 ;
     RECT  23.04 23.363 25.512 23.987 ;
     RECT  0.24 23.507 0.264 24.467 ;
     RECT  9.36 22.979 11.784 24.563 ;
     RECT  2.4 22.979 8.376 25.333 ;
     RECT  9.36 24.563 10.392 25.333 ;
     RECT  17.139 23.651 21.912 25.429 ;
     RECT  0.144 25.477 0.168 25.525 ;
     RECT  0.144 25.525 0.264 25.715 ;
     RECT  11.52 24.563 11.784 25.715 ;
     RECT  0.144 25.715 0.168 25.763 ;
     RECT  23.04 23.987 25.416 25.763 ;
     RECT  17.136 25.429 21.912 26.149 ;
     RECT  16.896 26.149 21.912 26.533 ;
     RECT  11.568 25.715 11.784 26.677 ;
     RECT  12.768 21.155 14.472 26.677 ;
     RECT  23.136 25.763 25.416 26.677 ;
     RECT  15.936 26.533 21.912 27.061 ;
     RECT  23.136 26.677 25.656 27.061 ;
     RECT  11.568 26.677 14.472 27.301 ;
     RECT  15.936 27.061 26.232 27.301 ;
     RECT  11.568 27.301 26.232 27.395 ;
     RECT  21.888 27.395 26.232 27.971 ;
     RECT  16.896 27.395 20.664 28.163 ;
     RECT  11.568 27.395 11.976 28.307 ;
     RECT  17.04 28.163 20.664 28.405 ;
     RECT  21.888 27.971 26.184 28.405 ;
     RECT  17.04 28.405 26.184 28.787 ;
     RECT  21.84 28.787 26.184 29.029 ;
     RECT  21.84 29.029 26.232 29.267 ;
     RECT  0.144 29.221 0.168 29.269 ;
     RECT  0.144 29.269 0.264 29.411 ;
     RECT  17.04 28.787 20.664 29.461 ;
     RECT  12.96 27.395 15.384 29.747 ;
     RECT  23.232 29.267 26.232 29.843 ;
     RECT  11.76 28.307 11.976 30.275 ;
     RECT  12.96 29.747 15.336 30.275 ;
     RECT  21.84 29.267 22.2 30.275 ;
     RECT  21.84 30.275 21.912 30.565 ;
     RECT  12.96 30.275 15.24 31.285 ;
     RECT  16.416 29.461 20.664 31.285 ;
     RECT  23.232 29.843 25.512 31.285 ;
     RECT  12.96 31.285 20.664 31.379 ;
     RECT  23.232 31.285 25.608 31.861 ;
     RECT  0.24 29.411 0.264 32.053 ;
     RECT  0.144 32.053 0.264 32.195 ;
     RECT  23.232 31.861 25.896 32.531 ;
     RECT  2.4 25.333 10.392 33.107 ;
     RECT  21.696 30.565 21.912 33.107 ;
     RECT  0.144 32.195 0.168 33.157 ;
     RECT  0.144 33.157 0.216 33.205 ;
     RECT  2.4 33.107 9.384 33.683 ;
     RECT  32.208 33.973 32.232 34.163 ;
     RECT  0.144 33.205 0.552 34.355 ;
     RECT  0.144 34.355 0.216 34.403 ;
     RECT  0.192 34.403 0.216 35.317 ;
     RECT  13.008 31.379 20.664 35.363 ;
     RECT  21.696 33.107 21.72 35.365 ;
     RECT  20.64 35.363 20.664 35.413 ;
     RECT  21.696 35.365 22.152 35.413 ;
     RECT  23.52 32.531 25.896 35.845 ;
     RECT  23.52 35.845 26.76 35.939 ;
     RECT  0.192 35.317 0.312 36.325 ;
     RECT  11.76 30.275 11.784 36.421 ;
     RECT  13.008 35.363 19.176 36.421 ;
     RECT  23.856 35.939 26.76 36.515 ;
     RECT  20.64 35.413 22.152 36.563 ;
     RECT  21.504 36.563 22.152 36.899 ;
     RECT  9.36 33.683 9.384 36.997 ;
     RECT  10.368 33.107 10.392 36.997 ;
     RECT  23.856 36.515 26.712 36.997 ;
     RECT  23.28 36.997 26.712 37.091 ;
     RECT  22.08 36.899 22.152 37.525 ;
     RECT  23.28 37.091 26.184 37.525 ;
     RECT  9.36 36.997 10.392 37.667 ;
     RECT  11.76 36.421 19.176 37.859 ;
     RECT  22.08 37.525 26.184 38.003 ;
     RECT  0.144 36.325 0.312 38.149 ;
     RECT  0.144 38.149 0.36 38.243 ;
     RECT  2.4 33.683 8.376 38.819 ;
     RECT  20.496 38.149 20.52 38.819 ;
     RECT  22.128 38.003 26.184 38.819 ;
     RECT  0.192 38.243 0.36 39.013 ;
     RECT  11.76 37.859 18.912 39.061 ;
     RECT  0.192 39.013 0.456 39.301 ;
     RECT  11.76 39.061 19.032 39.347 ;
     RECT  10.368 37.667 10.392 39.445 ;
     RECT  11.76 39.347 18.912 39.445 ;
     RECT  22.128 38.819 22.248 39.733 ;
     RECT  21.504 39.733 22.248 39.779 ;
     RECT  9.36 37.667 9.384 39.923 ;
     RECT  10.368 39.445 18.912 39.923 ;
     RECT  20.304 39.637 20.328 40.165 ;
     RECT  21.504 39.779 21.528 40.165 ;
     RECT  23.28 38.819 26.184 40.165 ;
     RECT  0.192 39.301 0.552 40.307 ;
     RECT  0.192 40.307 0.456 40.405 ;
     RECT  23.28 40.165 26.232 40.405 ;
     RECT  2.4 38.819 8.112 40.499 ;
     RECT  23.28 40.405 26.52 40.595 ;
     RECT  11.76 39.923 18.912 40.741 ;
     RECT  20.304 40.165 21.528 40.741 ;
     RECT  11.76 40.741 21.528 40.883 ;
     RECT  23.328 40.595 26.52 41.075 ;
     RECT  23.712 41.075 26.52 41.077 ;
     RECT  11.76 40.883 21.096 41.123 ;
     RECT  0.144 40.405 0.456 41.219 ;
     RECT  20.736 41.123 21.096 41.411 ;
     RECT  2.4 40.499 6.504 41.651 ;
     RECT  11.76 41.123 19.368 41.651 ;
     RECT  15.216 41.651 19.368 41.939 ;
     RECT  20.832 41.411 21.096 41.941 ;
     RECT  0.144 41.219 0.168 42.035 ;
     RECT  2.4 41.651 6.216 42.227 ;
     RECT  20.832 41.941 21.672 42.227 ;
     RECT  2.4 42.227 5.304 42.275 ;
     RECT  23.712 41.077 26.76 42.517 ;
     RECT  23.712 42.517 27.048 42.565 ;
     RECT  21.648 42.227 21.672 42.709 ;
     RECT  7.8 40.499 8.112 42.757 ;
     RECT  15.216 41.939 18.912 42.803 ;
     RECT  11.76 41.651 14.04 42.997 ;
     RECT  20.304 42.613 20.328 43.045 ;
     RECT  3.84 42.275 5.304 43.189 ;
     RECT  21.648 42.709 22.248 43.189 ;
     RECT  23.376 42.565 27.048 43.237 ;
     RECT  10.368 39.923 10.392 43.285 ;
     RECT  7.8 42.757 9.096 43.331 ;
     RECT  3.84 43.189 6.264 43.379 ;
     RECT  10.224 43.285 10.392 43.379 ;
     RECT  17.136 42.803 18.912 43.379 ;
     RECT  21.6 43.189 22.248 43.379 ;
     RECT  18.192 43.379 18.912 43.427 ;
     RECT  3.84 43.379 5.064 43.669 ;
     RECT  6.24 43.379 6.264 43.765 ;
     RECT  7.8 43.331 8.112 43.765 ;
     RECT  19.92 43.045 20.328 43.813 ;
     RECT  23.28 43.237 27.048 43.813 ;
     RECT  10.224 43.379 10.248 43.861 ;
     RECT  3.744 43.669 5.064 43.955 ;
     RECT  6.24 43.765 8.112 43.955 ;
     RECT  19.92 43.813 20.568 43.955 ;
     RECT  3.744 43.955 4.872 44.003 ;
     RECT  0.144 42.997 0.168 44.051 ;
     RECT  21.6 43.379 21.672 44.099 ;
     RECT  3.744 44.003 4.824 44.195 ;
     RECT  18.6 43.427 18.912 44.245 ;
     RECT  11.472 42.997 14.04 44.341 ;
     RECT  15.216 42.803 15.576 44.437 ;
     RECT  18.6 44.245 19.128 44.437 ;
     RECT  6.816 43.955 8.112 44.531 ;
     RECT  3.744 44.195 4.536 44.579 ;
     RECT  9.696 43.861 10.248 44.581 ;
     RECT  11.376 44.341 14.04 44.581 ;
     RECT  21.648 44.099 21.672 44.629 ;
     RECT  9.696 44.581 14.04 44.867 ;
     RECT  9.936 44.867 14.04 44.963 ;
     RECT  10.8 44.963 14.04 45.059 ;
     RECT  3.936 44.579 4.536 45.107 ;
     RECT  15.216 44.437 15.96 45.155 ;
     RECT  20.544 43.955 20.568 45.205 ;
     RECT  21.648 44.629 22.2 45.205 ;
     RECT  7.392 44.531 8.112 45.301 ;
     RECT  23.28 43.813 27.336 45.349 ;
     RECT  5.04 45.445 5.064 45.541 ;
     RECT  20.544 45.205 22.2 45.541 ;
     RECT  23.28 45.349 27.96 45.541 ;
     RECT  20.544 45.541 27.96 45.635 ;
     RECT  20.544 45.635 27.336 45.779 ;
     RECT  20.544 45.779 26.76 45.877 ;
     RECT  29.4 9.731 29.712 45.877 ;
     RECT  30.768 45.733 30.792 46.019 ;
     RECT  3.936 45.107 3.96 46.069 ;
     RECT  5.04 45.541 5.112 46.069 ;
     RECT  28.464 45.877 29.712 46.115 ;
     RECT  7.392 45.301 8.568 46.355 ;
     RECT  10.224 46.309 10.248 46.741 ;
     RECT  10.224 46.741 10.584 46.787 ;
     RECT  12.288 45.059 14.04 46.787 ;
     RECT  20.16 45.877 26.76 46.787 ;
     RECT  29.4 46.115 29.712 46.837 ;
     RECT  7.392 46.355 8.112 46.883 ;
     RECT  3.936 46.069 5.112 47.027 ;
     RECT  20.16 46.787 26.712 47.075 ;
     RECT  29.4 46.837 30.216 47.075 ;
     RECT  22.08 47.075 26.712 47.219 ;
     RECT  10.56 46.787 10.584 47.221 ;
     RECT  18.48 44.437 19.128 47.221 ;
     RECT  20.16 47.075 21.096 47.221 ;
     RECT  0.144 46.405 0.168 47.363 ;
     RECT  18.48 47.221 21.096 47.363 ;
     RECT  22.08 47.219 26.664 47.507 ;
     RECT  6.192 47.365 6.216 47.699 ;
     RECT  12.288 46.787 13.512 47.845 ;
     RECT  15.216 45.155 15.576 47.845 ;
     RECT  22.08 47.507 25.944 47.939 ;
     RECT  3.936 47.027 4.872 48.277 ;
     RECT  32.208 47.509 32.232 48.467 ;
     RECT  18.48 47.363 20.856 48.515 ;
     RECT  10.56 47.221 11.304 48.805 ;
     RECT  12.288 47.845 15.576 48.805 ;
     RECT  22.08 47.939 25.896 48.997 ;
     RECT  0.144 48.997 0.168 49.187 ;
     RECT  3.936 48.277 5.112 49.189 ;
     RECT  17.136 43.379 17.16 49.477 ;
     RECT  18.48 48.515 19.08 49.477 ;
     RECT  3.936 49.189 6.072 49.525 ;
     RECT  10.56 48.805 15.576 49.619 ;
     RECT  3.888 49.525 6.072 49.763 ;
     RECT  7.8 46.883 8.112 50.101 ;
     RECT  17.136 49.477 19.08 50.437 ;
     RECT  20.064 48.515 20.856 50.437 ;
     RECT  2.4 42.275 2.712 51.205 ;
     RECT  3.888 49.763 6.024 51.205 ;
     RECT  17.136 50.437 20.856 51.251 ;
     RECT  7.8 50.101 9.048 51.349 ;
     RECT  10.56 49.619 13.512 51.349 ;
     RECT  7.68 51.349 13.512 51.635 ;
     RECT  9.792 51.635 13.512 51.683 ;
     RECT  14.928 49.619 15.576 51.923 ;
     RECT  17.136 51.251 17.256 51.923 ;
     RECT  18.48 51.251 20.856 51.923 ;
     RECT  7.68 51.635 8.112 52.499 ;
     RECT  11.52 51.683 13.512 52.885 ;
     RECT  17.136 51.923 17.16 52.885 ;
     RECT  9.792 51.683 9.816 52.981 ;
     RECT  18.6 51.923 20.856 53.557 ;
     RECT  2.4 51.205 6.552 53.747 ;
     RECT  9.792 52.981 10.2 53.747 ;
     RECT  2.4 53.747 2.808 53.795 ;
     RECT  15.216 51.923 15.576 53.941 ;
     RECT  0.144 53.845 0.168 54.131 ;
     RECT  4.272 53.747 6.552 54.565 ;
     RECT  7.8 52.499 8.112 54.565 ;
     RECT  18.6 53.557 20.904 54.755 ;
     RECT  15.216 53.941 15.672 54.851 ;
     RECT  4.272 54.565 8.112 55.237 ;
     RECT  17.136 52.885 17.4 55.237 ;
     RECT  18.6 54.755 20.856 55.237 ;
     RECT  11.328 52.885 13.512 55.331 ;
     RECT  9.792 53.747 10.152 55.427 ;
     RECT  2.4 53.795 2.712 55.813 ;
     RECT  3.696 55.237 8.112 55.813 ;
     RECT  2.4 55.813 8.112 55.907 ;
     RECT  11.52 55.331 13.512 56.389 ;
     RECT  9.792 55.427 9.864 56.869 ;
     RECT  22.08 48.997 26.616 56.869 ;
     RECT  2.4 55.907 3.72 56.917 ;
     RECT  4.704 55.907 6.264 56.917 ;
     RECT  2.4 56.917 6.264 56.965 ;
     RECT  7.392 55.907 8.112 56.965 ;
     RECT  0.144 56.533 0.168 57.539 ;
     RECT  21.936 56.869 26.616 57.587 ;
     RECT  2.4 56.965 8.112 57.731 ;
     RECT  7.296 57.731 8.112 58.117 ;
     RECT  7.296 58.117 8.664 58.549 ;
     RECT  7.296 58.549 8.712 58.645 ;
     RECT  9.792 56.869 10.104 58.645 ;
     RECT  17.136 55.237 20.856 58.645 ;
     RECT  7.296 58.645 10.152 59.075 ;
     RECT  2.4 57.731 6.168 59.363 ;
     RECT  10.08 59.075 10.152 59.605 ;
     RECT  11.52 56.389 13.848 59.605 ;
     RECT  10.08 59.605 13.848 60.277 ;
     RECT  15.216 54.851 15.576 60.277 ;
     RECT  7.296 59.075 8.712 60.467 ;
     RECT  10.08 60.277 15.576 60.899 ;
     RECT  28.32 49.189 28.344 60.949 ;
     RECT  2.4 59.363 6.12 61.043 ;
     RECT  16.752 58.645 20.856 61.045 ;
     RECT  22.08 57.587 26.616 61.045 ;
     RECT  27.84 60.949 28.344 61.045 ;
     RECT  7.632 60.467 8.712 61.237 ;
     RECT  0.144 61.093 0.168 61.283 ;
     RECT  10.08 60.899 13.848 61.619 ;
     RECT  15.216 60.899 15.576 61.619 ;
     RECT  15.216 61.619 15.24 62.101 ;
     RECT  3.696 61.043 6.12 62.341 ;
     RECT  30.768 62.437 30.792 62.675 ;
     RECT  2.4 61.043 2.712 62.677 ;
     RECT  3.696 62.341 6.36 62.677 ;
     RECT  7.632 61.237 9.096 62.677 ;
     RECT  10.08 61.619 13.512 62.677 ;
     RECT  16.752 61.045 26.616 62.965 ;
     RECT  16.752 62.965 26.664 63.205 ;
     RECT  27.744 61.045 28.344 63.205 ;
     RECT  2.4 62.677 6.36 63.493 ;
     RECT  7.632 62.677 13.512 63.493 ;
     RECT  2.4 63.493 13.512 63.685 ;
     RECT  15.12 62.101 15.24 63.685 ;
     RECT  2.4 63.685 15.24 64.451 ;
     RECT  16.752 63.205 28.344 64.885 ;
     RECT  29.4 47.075 29.712 64.885 ;
     RECT  2.4 64.451 6.36 65.027 ;
     RECT  7.632 64.451 15.24 65.027 ;
     RECT  2.4 65.027 5.592 65.123 ;
     RECT  13.104 65.027 15.24 65.603 ;
     RECT  7.632 65.027 11.784 65.845 ;
     RECT  14.784 65.603 15.24 66.131 ;
     RECT  16.752 64.885 29.712 66.179 ;
     RECT  3.792 65.123 5.592 66.227 ;
     RECT  7.344 65.845 11.784 66.373 ;
     RECT  7.2 66.373 11.784 66.469 ;
     RECT  13.104 65.603 13.512 66.469 ;
     RECT  2.4 65.123 2.808 66.661 ;
     RECT  23.088 66.179 29.712 66.755 ;
     RECT  0.144 66.805 0.168 67.091 ;
     RECT  7.2 66.469 13.512 67.093 ;
     RECT  15.12 66.131 15.24 67.189 ;
     RECT  4.176 66.227 5.592 67.285 ;
     RECT  6.96 67.093 13.512 67.285 ;
     RECT  23.088 66.755 26.664 67.331 ;
     RECT  15.024 67.189 15.24 67.955 ;
     RECT  4.176 67.285 13.512 68.245 ;
     RECT  26.496 67.331 26.664 68.341 ;
     RECT  27.696 66.755 29.712 68.341 ;
     RECT  16.752 66.179 22.104 68.675 ;
     RECT  4.176 68.245 13.656 68.821 ;
     RECT  16.752 68.675 20.904 69.011 ;
     RECT  26.496 68.341 29.712 69.011 ;
     RECT  2.4 66.661 2.904 69.349 ;
     RECT  3.936 68.821 13.992 69.349 ;
     RECT  23.088 67.331 25.416 69.349 ;
     RECT  26.496 69.011 26.616 69.349 ;
     RECT  15.216 67.955 15.24 69.587 ;
     RECT  27.84 69.011 29.712 70.021 ;
     RECT  16.752 69.011 20.856 70.069 ;
     RECT  22.08 68.675 22.104 70.117 ;
     RECT  23.088 69.349 26.616 70.117 ;
     RECT  27.792 70.021 29.712 70.163 ;
     RECT  2.4 69.349 13.992 70.405 ;
     RECT  22.08 70.117 26.616 70.691 ;
     RECT  27.792 70.163 28.344 70.691 ;
     RECT  23.088 70.691 26.616 70.739 ;
     RECT  2.4 70.405 14.808 71.315 ;
     RECT  15.984 70.069 20.856 71.317 ;
     RECT  15.984 71.317 21.096 71.843 ;
     RECT  27.84 70.691 28.344 72.325 ;
     RECT  2.4 71.315 13.992 72.421 ;
     RECT  15.984 71.843 20.856 72.853 ;
     RECT  15.984 72.853 21.096 72.947 ;
     RECT  26.496 70.739 26.616 73.237 ;
     RECT  27.792 72.325 28.344 73.237 ;
     RECT  2.4 72.421 14.808 73.571 ;
     RECT  15.984 72.947 19.848 73.571 ;
     RECT  15.984 73.571 17.352 73.861 ;
     RECT  20.832 72.947 21.096 74.053 ;
     RECT  22.08 70.691 22.104 74.053 ;
     RECT  23.088 70.739 25.416 74.053 ;
     RECT  26.496 73.237 28.344 74.053 ;
     RECT  20.832 74.053 28.344 74.195 ;
     RECT  15.936 73.861 17.352 74.629 ;
     RECT  22.752 74.195 28.344 74.771 ;
     RECT  15.264 74.629 17.352 75.013 ;
     RECT  18.336 73.571 19.848 75.013 ;
     RECT  20.832 74.195 21.432 75.155 ;
     RECT  22.752 74.771 27.864 75.251 ;
     RECT  2.4 73.571 13.992 75.299 ;
     RECT  23.088 75.251 27.864 75.299 ;
     RECT  6.768 75.299 13.656 75.731 ;
     RECT  26.496 75.299 27.864 75.781 ;
     RECT  15.264 75.013 19.848 76.309 ;
     RECT  2.4 75.299 5.544 76.403 ;
     RECT  7.248 75.731 13.656 76.403 ;
     RECT  14.784 76.309 19.848 76.403 ;
     RECT  20.832 75.155 21.144 76.403 ;
     RECT  11.904 76.403 13.656 76.451 ;
     RECT  11.904 76.451 13.608 76.979 ;
     RECT  14.784 76.403 16.104 76.979 ;
     RECT  17.568 76.403 19.848 77.027 ;
     RECT  7.248 76.403 10.824 77.075 ;
     RECT  14.784 76.979 14.808 77.555 ;
     RECT  7.68 77.075 10.824 77.651 ;
     RECT  17.568 77.027 17.592 77.987 ;
     RECT  26.496 75.781 28.104 78.083 ;
     RECT  2.4 76.403 3.48 78.131 ;
     RECT  16.08 76.979 16.104 78.131 ;
     RECT  20.832 76.403 20.856 78.469 ;
     RECT  4.848 76.403 5.544 78.613 ;
     RECT  14.544 78.373 14.568 78.613 ;
     RECT  15.552 78.565 15.576 78.613 ;
     RECT  4.08 78.613 5.544 78.707 ;
     RECT  9.264 77.651 10.824 78.901 ;
     RECT  11.904 76.979 13.512 78.901 ;
     RECT  4.08 78.707 5.208 79.043 ;
     RECT  27.84 78.083 28.104 79.283 ;
     RECT  20.832 78.469 21.336 79.475 ;
     RECT  9.264 78.901 13.512 79.621 ;
     RECT  14.544 78.613 15.576 79.621 ;
     RECT  9.264 79.621 15.576 79.717 ;
     RECT  18.6 77.027 19.848 79.717 ;
     RECT  7.68 77.651 8.28 79.859 ;
     RECT  9.264 79.717 15.72 79.859 ;
     RECT  18.192 79.717 19.848 79.859 ;
     RECT  23.088 75.299 25.368 79.859 ;
     RECT  28.08 79.283 28.104 80.003 ;
     RECT  10.704 79.859 14.232 80.051 ;
     RECT  9.264 79.859 9.288 80.245 ;
     RECT  2.4 78.131 2.712 80.341 ;
     RECT  4.896 79.043 5.208 80.389 ;
     RECT  4.896 80.389 5.496 80.435 ;
     RECT  10.704 80.051 10.728 80.435 ;
     RECT  12.192 80.051 14.232 80.435 ;
     RECT  15.456 79.859 15.72 80.435 ;
     RECT  18.192 79.859 19.224 80.435 ;
     RECT  26.496 78.083 26.52 80.435 ;
     RECT  21.312 79.475 21.336 80.531 ;
     RECT  12.24 80.435 13.512 80.579 ;
     RECT  2.4 80.341 3.432 80.963 ;
     RECT  7.68 79.859 8.112 80.963 ;
     RECT  9.216 80.245 9.288 80.963 ;
     RECT  23.184 79.859 25.368 80.963 ;
     RECT  18.48 80.435 19.032 81.011 ;
     RECT  9.264 80.963 9.288 81.059 ;
     RECT  12.288 80.579 13.512 81.155 ;
     RECT  23.184 80.963 24.312 81.539 ;
     RECT  5.472 80.435 5.496 81.587 ;
     RECT  18.6 81.011 19.032 81.635 ;
     RECT  15.456 80.435 15.48 81.875 ;
     RECT  2.4 80.963 2.712 82.089 ;
     RECT  7.8 80.963 8.112 82.089 ;
     RECT  13.2 81.155 13.512 82.089 ;
     RECT  18.6 81.635 18.912 82.089 ;
     RECT  24 81.539 24.312 82.089 ;
     RECT  29.4 70.163 29.712 82.089 ;
     RECT  2.4 82.089 2.52 82.103 ;
     RECT  7.8 82.089 7.92 82.103 ;
     RECT  13.2 82.089 13.32 82.103 ;
     RECT  18.6 82.089 18.72 82.103 ;
     RECT  24 82.089 24.12 82.103 ;
     RECT  29.4 82.089 29.52 82.103 ;
     RECT  8.112 2.821 9.36 3.733 ;
     RECT  9.384 2.821 10.368 3.397 ;
     RECT  10.392 3.157 11.76 4.645 ;
     RECT  11.784 3.157 13.2 6.229 ;
     RECT  8.232 3.733 9.36 6.709 ;
     RECT  3.912 4.261 5.088 5.605 ;
     RECT  18.912 4.453 20.064 5.171 ;
     RECT  22.176 4.595 22.2 5.317 ;
     RECT  16.008 4.645 17.088 4.741 ;
     RECT  18.912 5.171 20.304 5.605 ;
     RECT  14.472 5.221 15.984 7.331 ;
     RECT  21.912 5.317 23.376 5.893 ;
     RECT  19.128 5.605 20.304 7.381 ;
     RECT  20.664 5.653 21.888 9.061 ;
     RECT  16.824 5.747 18 6.035 ;
     RECT  22.296 5.893 23.376 6.229 ;
     RECT  10.68 6.083 11.76 9.925 ;
     RECT  5.592 6.229 6.864 6.613 ;
     RECT  11.784 6.229 12.912 7.957 ;
     RECT  5.64 6.613 6.864 6.805 ;
     RECT  16.776 6.899 16.824 7.957 ;
     RECT  14.472 7.331 14.808 7.861 ;
     RECT  26.232 7.955 26.376 8.437 ;
     RECT  16.776 7.957 18.24 8.339 ;
     RECT  18.912 8.003 20.304 8.579 ;
     RECT  17.616 8.339 18.24 8.965 ;
     RECT  26.232 8.437 27.456 10.883 ;
     RECT  11.784 8.579 12.816 11.029 ;
     RECT  18.912 8.579 20.64 9.205 ;
     RECT  20.856 9.061 21.888 9.349 ;
     RECT  27.624 9.061 29.04 9.731 ;
     RECT  19.608 9.205 20.64 9.925 ;
     RECT  27.624 9.731 29.4 10.213 ;
     RECT  10.728 9.925 11.76 11.029 ;
     RECT  28.104 10.213 29.4 11.987 ;
     RECT  19.608 12.035 20.688 12.563 ;
     RECT  25.752 12.517 26.736 13.141 ;
     RECT  10.728 12.563 11.76 14.821 ;
     RECT  19.368 12.563 20.688 12.947 ;
     RECT  19.368 12.947 20.832 13.139 ;
     RECT  18.912 13.139 20.832 13.715 ;
     RECT  25.512 13.667 26.544 14.915 ;
     RECT  18.912 13.715 19.56 14.149 ;
     RECT  25.512 14.915 26.64 14.963 ;
     RECT  25.512 14.963 26.688 15.347 ;
     RECT  25.512 15.347 25.656 16.165 ;
     RECT  25.512 17.699 25.656 18.709 ;
     RECT  21.576 18.179 23.04 21.589 ;
     RECT  15.48 18.229 16.752 18.275 ;
     RECT  14.472 18.275 15.456 18.947 ;
     RECT  19.656 18.565 20.736 19.379 ;
     RECT  11.832 18.851 12.816 19.909 ;
     RECT  19.656 19.379 21.456 20.533 ;
     RECT  25.656 19.813 26.64 19.909 ;
     RECT  19.656 20.533 21.168 20.629 ;
     RECT  25.656 20.579 26.64 21.203 ;
     RECT  11.784 21.155 12.768 26.677 ;
     RECT  25.656 21.203 26.688 21.971 ;
     RECT  21.672 21.589 23.04 22.117 ;
     RECT  0.144 21.971 0.192 22.933 ;
     RECT  21.912 22.117 23.04 22.165 ;
     RECT  14.472 22.165 15.648 22.835 ;
     RECT  14.472 22.835 15.672 23.317 ;
     RECT  8.376 22.979 9.36 25.333 ;
     RECT  14.472 23.317 15.936 23.987 ;
     RECT  15.96 23.317 17.424 23.605 ;
     RECT  21.912 23.363 23.04 25.763 ;
     RECT  15.96 23.605 17.136 23.651 ;
     RECT  15.96 23.651 17.139 23.987 ;
     RECT  17.136 23.987 17.139 25.429 ;
     RECT  0.24 24.467 0.264 25.477 ;
     RECT  10.392 24.563 11.52 25.715 ;
     RECT  0.168 25.477 0.264 25.525 ;
     RECT  10.392 25.715 11.568 28.307 ;
     RECT  21.912 25.763 23.136 27.061 ;
     RECT  14.472 26.533 15.936 27.301 ;
     RECT  11.976 27.395 12.96 30.275 ;
     RECT  15.384 27.395 16.896 28.163 ;
     RECT  20.664 27.395 21.888 28.405 ;
     RECT  26.184 27.971 26.232 29.029 ;
     RECT  15.384 28.163 17.04 29.461 ;
     RECT  10.392 28.307 11.76 39.445 ;
     RECT  20.664 28.787 21.84 30.565 ;
     RECT  22.2 29.267 23.232 30.275 ;
     RECT  15.384 29.461 16.416 29.747 ;
     RECT  15.336 29.747 16.416 30.275 ;
     RECT  25.512 29.843 25.608 31.285 ;
     RECT  11.784 30.275 12.96 31.379 ;
     RECT  15.24 30.275 16.416 31.285 ;
     RECT  21.912 30.275 23.232 32.531 ;
     RECT  20.664 30.565 21.696 35.413 ;
     RECT  11.784 31.379 13.008 36.421 ;
     RECT  0.168 32.195 0.264 33.157 ;
     RECT  9.384 33.107 10.368 36.997 ;
     RECT  0.216 33.157 0.264 33.205 ;
     RECT  8.376 33.683 9.36 38.819 ;
     RECT  0.216 34.355 0.312 35.317 ;
     RECT  19.176 35.363 20.64 36.563 ;
     RECT  22.152 35.365 23.52 35.939 ;
     RECT  22.152 35.939 23.856 36.997 ;
     RECT  22.152 36.997 23.28 37.525 ;
     RECT  9.384 37.667 10.368 39.923 ;
     RECT  18.912 37.859 19.176 38.149 ;
     RECT  18.912 38.149 20.496 38.819 ;
     RECT  8.112 38.819 9.36 39.923 ;
     RECT  18.912 38.819 20.52 39.061 ;
     RECT  22.248 38.819 23.28 39.779 ;
     RECT  19.032 39.061 20.52 39.347 ;
     RECT  18.912 39.347 20.52 39.637 ;
     RECT  18.912 39.637 20.304 40.741 ;
     RECT  20.328 39.637 20.52 39.733 ;
     RECT  20.328 39.733 21.504 40.165 ;
     RECT  10.392 39.923 11.76 42.997 ;
     RECT  6.504 40.499 7.8 41.651 ;
     RECT  21.096 40.883 21.528 41.941 ;
     RECT  23.376 41.075 23.712 42.565 ;
     RECT  19.368 41.123 20.736 41.411 ;
     RECT  19.368 41.411 20.832 41.939 ;
     RECT  14.04 41.651 15.216 46.787 ;
     RECT  18.912 41.939 20.832 42.227 ;
     RECT  0.144 42.035 0.168 42.997 ;
     RECT  5.304 42.227 6.216 43.189 ;
     RECT  18.912 42.227 21.648 42.613 ;
     RECT  2.712 42.275 3.84 43.669 ;
     RECT  18.912 42.613 20.304 43.045 ;
     RECT  20.328 42.613 21.648 43.189 ;
     RECT  22.248 42.709 23.376 43.237 ;
     RECT  9.096 42.757 10.368 43.285 ;
     RECT  10.392 42.997 11.472 43.379 ;
     RECT  18.912 43.045 19.92 43.955 ;
     RECT  20.328 43.189 21.6 43.813 ;
     RECT  22.248 43.237 23.28 43.379 ;
     RECT  9.096 43.285 10.224 43.331 ;
     RECT  9.696 43.331 10.224 43.861 ;
     RECT  5.064 43.379 6.24 43.955 ;
     RECT  10.248 43.379 11.472 44.341 ;
     RECT  17.16 43.379 18.192 43.427 ;
     RECT  21.672 43.379 23.28 44.629 ;
     RECT  17.16 43.427 18.6 44.437 ;
     RECT  2.712 43.669 3.744 44.579 ;
     RECT  20.568 43.813 21.6 44.099 ;
     RECT  4.872 43.955 5.064 44.003 ;
     RECT  18.912 43.955 20.544 44.245 ;
     RECT  4.824 44.003 5.064 44.195 ;
     RECT  20.568 44.099 21.648 45.205 ;
     RECT  4.536 44.195 5.064 45.107 ;
     RECT  19.128 44.245 20.544 45.877 ;
     RECT  10.248 44.341 11.376 44.581 ;
     RECT  15.96 44.437 17.136 45.155 ;
     RECT  17.16 44.437 18.48 49.477 ;
     RECT  2.712 44.579 3.936 49.525 ;
     RECT  22.2 44.629 23.28 45.541 ;
     RECT  10.224 44.963 10.8 45.059 ;
     RECT  10.224 45.059 10.248 46.309 ;
     RECT  3.96 45.107 5.064 45.445 ;
     RECT  27.96 45.349 29.4 45.635 ;
     RECT  3.96 45.445 5.04 46.069 ;
     RECT  27.336 45.635 29.4 45.779 ;
     RECT  29.712 45.733 30.768 46.019 ;
     RECT  28.464 45.779 29.4 45.877 ;
     RECT  19.128 45.877 20.16 47.221 ;
     RECT  29.712 46.019 30.216 46.837 ;
     RECT  13.512 46.787 15.216 47.845 ;
     RECT  4.872 47.027 5.112 47.365 ;
     RECT  21.096 47.075 22.08 47.363 ;
     RECT  11.304 47.221 12.288 48.805 ;
     RECT  20.856 47.363 22.08 53.557 ;
     RECT  4.872 47.365 6.192 47.699 ;
     RECT  25.944 47.507 26.616 47.939 ;
     RECT  4.872 47.699 6.072 48.277 ;
     RECT  25.896 47.939 26.616 48.997 ;
     RECT  5.112 48.277 6.072 49.189 ;
     RECT  19.08 48.515 20.064 50.437 ;
     RECT  28.344 49.189 29.4 64.885 ;
     RECT  2.712 49.525 3.888 51.205 ;
     RECT  13.512 49.619 14.928 51.923 ;
     RECT  6.024 49.763 6.072 51.205 ;
     RECT  9.048 50.101 10.56 51.349 ;
     RECT  6.552 51.205 7.8 51.349 ;
     RECT  17.256 51.251 18.48 51.923 ;
     RECT  6.552 51.349 7.68 52.499 ;
     RECT  9.816 51.683 11.52 52.885 ;
     RECT  17.16 51.923 18.6 52.885 ;
     RECT  6.552 52.499 7.8 54.565 ;
     RECT  9.816 52.885 11.328 52.981 ;
     RECT  17.4 52.885 18.6 55.237 ;
     RECT  10.2 52.981 11.328 53.747 ;
     RECT  20.904 53.557 22.08 54.755 ;
     RECT  2.808 53.747 4.272 53.795 ;
     RECT  10.152 53.747 11.328 55.331 ;
     RECT  2.712 53.795 4.272 55.237 ;
     RECT  15.672 53.941 17.136 54.851 ;
     RECT  20.856 54.755 22.08 56.869 ;
     RECT  2.712 55.237 3.696 55.813 ;
     RECT  10.152 55.331 11.52 55.427 ;
     RECT  9.864 55.427 11.52 56.869 ;
     RECT  3.72 55.907 4.704 56.917 ;
     RECT  6.264 55.907 7.392 56.965 ;
     RECT  13.848 56.389 15.216 60.277 ;
     RECT  10.104 56.869 11.52 58.645 ;
     RECT  20.856 56.869 21.936 57.587 ;
     RECT  20.856 57.587 22.08 61.045 ;
     RECT  6.168 57.731 7.296 59.363 ;
     RECT  8.664 58.117 9.792 58.549 ;
     RECT  8.712 58.549 9.792 58.645 ;
     RECT  10.152 58.645 11.52 59.605 ;
     RECT  15.576 58.645 16.752 61.619 ;
     RECT  8.712 59.075 10.08 61.237 ;
     RECT  6.12 59.363 7.296 60.467 ;
     RECT  6.12 60.467 7.632 62.341 ;
     RECT  13.848 60.899 15.216 61.619 ;
     RECT  26.616 60.949 27.84 61.045 ;
     RECT  2.712 61.043 3.696 62.677 ;
     RECT  26.616 61.045 27.744 62.965 ;
     RECT  9.096 61.237 10.08 62.677 ;
     RECT  15.12 61.619 15.216 62.101 ;
     RECT  15.24 61.619 16.752 69.587 ;
     RECT  6.36 62.341 7.632 63.493 ;
     RECT  29.712 62.437 30.768 62.675 ;
     RECT  26.664 62.965 27.744 63.205 ;
     RECT  6.36 64.451 7.632 65.027 ;
     RECT  7.2 65.027 7.632 65.845 ;
     RECT  11.784 65.027 13.104 66.469 ;
     RECT  2.808 65.123 3.792 66.227 ;
     RECT  13.512 65.603 14.784 66.131 ;
     RECT  7.2 65.845 7.344 66.373 ;
     RECT  13.512 66.131 15.12 67.189 ;
     RECT  22.104 66.179 23.088 70.117 ;
     RECT  2.808 66.227 4.176 66.661 ;
     RECT  2.904 66.661 4.176 68.821 ;
     RECT  26.664 66.755 27.696 68.341 ;
     RECT  5.592 67.093 6.96 67.285 ;
     RECT  13.512 67.189 15.024 67.955 ;
     RECT  25.416 67.331 26.496 69.349 ;
     RECT  13.512 67.955 15.216 68.245 ;
     RECT  13.656 68.245 15.216 68.821 ;
     RECT  20.904 68.675 22.08 69.011 ;
     RECT  2.904 68.821 3.936 69.349 ;
     RECT  13.992 68.821 15.216 69.587 ;
     RECT  20.856 69.011 22.08 71.317 ;
     RECT  26.616 69.011 27.84 70.021 ;
     RECT  13.992 69.587 16.752 70.069 ;
     RECT  26.616 70.021 27.792 70.691 ;
     RECT  13.992 70.069 15.984 70.405 ;
     RECT  28.344 70.163 29.4 74.771 ;
     RECT  14.808 70.405 15.984 71.315 ;
     RECT  22.104 70.691 23.088 74.053 ;
     RECT  26.616 70.691 27.84 72.325 ;
     RECT  25.416 70.739 26.496 74.053 ;
     RECT  13.992 71.315 15.984 72.421 ;
     RECT  21.096 71.317 22.08 71.843 ;
     RECT  20.856 71.843 22.08 72.853 ;
     RECT  26.616 72.325 27.792 73.237 ;
     RECT  14.808 72.421 15.984 73.571 ;
     RECT  21.096 72.853 22.08 74.053 ;
     RECT  19.848 72.947 20.832 79.475 ;
     RECT  13.992 73.571 15.984 73.861 ;
     RECT  17.352 73.571 18.336 75.013 ;
     RECT  13.992 73.861 15.936 74.629 ;
     RECT  21.432 74.195 22.752 75.155 ;
     RECT  13.992 74.629 15.264 75.299 ;
     RECT  27.864 74.771 29.4 75.781 ;
     RECT  5.544 75.299 6.768 75.731 ;
     RECT  13.656 75.299 15.264 76.309 ;
     RECT  25.368 75.299 26.496 80.435 ;
     RECT  28.104 75.781 29.4 80.003 ;
     RECT  13.656 76.309 14.784 76.451 ;
     RECT  3.48 76.403 4.848 78.131 ;
     RECT  10.824 76.403 11.904 78.901 ;
     RECT  16.104 76.403 17.568 77.987 ;
     RECT  13.608 76.451 14.784 76.979 ;
     RECT  13.512 76.979 14.784 77.555 ;
     RECT  14.808 76.979 16.08 77.555 ;
     RECT  17.592 77.027 18.6 77.987 ;
     RECT  13.512 77.555 16.08 78.131 ;
     RECT  8.28 77.651 9.264 79.859 ;
     RECT  26.52 78.083 27.84 79.283 ;
     RECT  2.712 78.131 4.848 78.613 ;
     RECT  13.512 78.131 15.576 78.373 ;
     RECT  13.512 78.373 14.544 79.621 ;
     RECT  14.568 78.373 15.576 78.565 ;
     RECT  14.568 78.565 15.552 78.613 ;
     RECT  2.712 78.613 4.08 79.043 ;
     RECT  2.712 79.043 4.896 80.341 ;
     RECT  19.848 79.475 21.312 79.859 ;
     RECT  8.112 79.859 9.264 80.245 ;
     RECT  9.288 79.859 10.704 80.435 ;
     RECT  14.232 79.859 15.456 80.435 ;
     RECT  10.728 80.051 12.192 80.435 ;
     RECT  8.112 80.245 9.216 80.963 ;
     RECT  3.432 80.341 4.896 80.435 ;
     RECT  8.112 80.963 9.264 81.059 ;
  END
END ot_hbm_coll_face_pipe512
END LIBRARY
